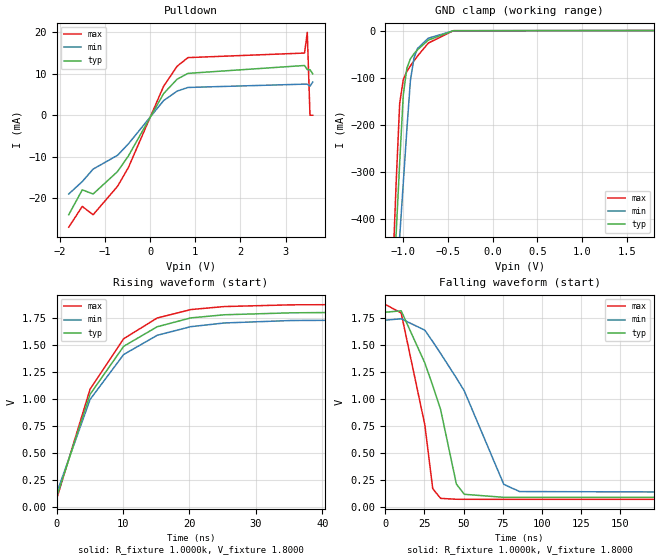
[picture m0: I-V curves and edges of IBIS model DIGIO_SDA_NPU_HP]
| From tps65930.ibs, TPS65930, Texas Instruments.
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|   Model DIGIO_SDA_NPU_HP
[Model]  DIGIO_SDA_NPU_HP
Model_type I/O_open_drain
Polarity   Non-Inverting
Enable   Active-Low
Vinl =   0.6300V
Vinh =   1.1700V
C_comp   1.3888pF   2.2766pF   1.3653pF
[Temperature Range]   25.0000   0.1250k   -40.0000
[Pullup Reference]   1.8000V   1.7280V   1.8720V
[Pulldown Reference]   0.0V   0.0V   0.0V
[POWER Clamp Reference]   1.8000V   1.7280V   1.8720V
[GND Clamp Reference]   0.0V   0.0V   0.0V
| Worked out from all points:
|   slope of the pulldown table from 0 to 0.27 V, typ, clamps not added: 56.7 ohm
|   GND clamp passes 1 mA (typ) near -0.48 V on its own axis
|   rising waveform, R_fixture 1.0000k, V_fixture 1.8000: 20-80 % time 7.98ns typ, 8.21ns min, 7.84ns max; typ from 0.089 V to 1.8 V
|   falling waveform, R_fixture 1.0000k, V_fixture 1.8000: 20-80 % time 20.7ns typ, 33.5ns min, 13.6ns max; typ from 1.8 V to 0.089 V
[Pulldown]
|Voltage   I(typ)   I(min)   I(max)
-1.8V     -24mA      -19mA      -27mA
-1.5V     -18mA      -16mA      -22mA
-1.26V    -19mA      -13mA      -24mA
-720mV    -13.59mA   -9.66mA    -17.16mA
-480mV    -9.841mA   -6.917mA   -12.63mA
300mV     5.219mA    3.531mA    6.988mA
600mV     8.705mA    5.824mA    11.83mA
840mV     10.1mA     6.7mA      13.9mA
3.42V     12mA       7.5mA      15mA
3.48V     11mA       7.5mA      20mA
3.54V     11mA       7mA        0A
3.6V      10mA       8mA        0A
[GND_clamp]
|Voltage   I(typ)   I(min)   I(max)
-1.8V     -3.217A    -2.637A    -3.872A
-1.12V    -586.2mA   -666.6mA   -520.9mA
-1.08V    -433.2mA   -552.2mA   -325.7mA
-1.04V    -280.6mA   -438.1mA   -154.5mA
-1V       -137.3mA   -324.2mA   -104.4mA
-960mV    -80.09mA   -210.6mA   -86.92mA
-920mV    -60.05mA   -105.9mA   -74.96mA
-880mV    -49.17mA   -57.98mA   -64.18mA
-840mV    -40.79mA   -38.01mA   -53.95mA
-720mV    -20.35mA   -16.3mA    -26.7mA
-440mV    -395.2uA   -580uA     -319uA
1.8V      20.09nA    79.65nA    15.47nA
[Ramp]
| variable   typ   min   max
dV/dt_r  1.0268/7.8959n   0.9617/8.1255n   1.0813/7.7656n
dV/dt_f  1.0268/20.4605n   0.9617/33.1830n   1.0813/13.5006n
R_load = 1.0000k
[Rising Waveform]
R_fixture= 1.0000k
V_fixture= 1.8000
V_fixture_min= 1.7280
V_fixture_max= 1.8720
|time   V(typ)   V(min)   V(max)
0s        88.62mV    124.1mV    69.75mV
5.051ns   1.041V     993.6mV    1.089V
10.1ns    1.485V     1.409V     1.555V
15.15ns   1.666V     1.587V     1.747V
20.2ns    1.748V     1.667V     1.825V
25.25ns   1.777V     1.701V     1.853V
35.35ns   1.795V     1.724V     1.869V
45.45ns   1.8V       1.727V     1.871V
500ns     1.8V       1.727V     1.872V
[Falling Waveform]
R_fixture= 1.0000k
V_fixture= 1.8000
V_fixture_min= 1.7280
V_fixture_max= 1.8720
|time   V(typ)   V(min)   V(max)
0s        1.8V       1.727V     1.872V
10.1ns    1.814V     1.74V      1.794V
25.25ns   1.331V     1.634V     758.1mV
30.3ns    1.122V     1.529V     168.4mV
35.35ns   899.7mV    1.419V     78.6mV
45.45ns   210.2mV    1.192V     70.51mV
50.51ns   116.2mV    1.072V     70.07mV
75.76ns   88.36mV    208.3mV    69.78mV
85.86ns   88.85mV    141.8mV    69.78mV
500ns     88.59mV    124.1mV    69.77mV
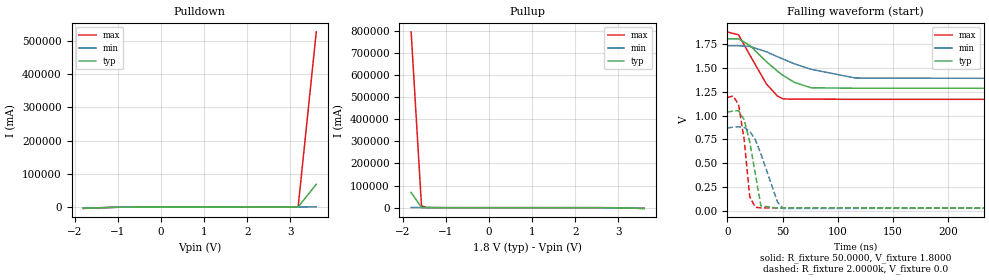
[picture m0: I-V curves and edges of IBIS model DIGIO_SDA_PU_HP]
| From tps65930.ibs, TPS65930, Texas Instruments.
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|   Model DIGIO_SDA_PU_HP
[Model]  DIGIO_SDA_PU_HP
Model_type Output
Polarity   Non-Inverting
Vinl =   0.6300V
Vinh =   1.1700V
C_comp   1.3888pF   2.2766pF   1.3653pF
[Temperature Range]   25.0000   0.1250k   -40.0000
[Pullup Reference]   1.8000V   1.7280V   1.8720V
[Pulldown Reference]   0.0V   0.0V   0.0V
[POWER Clamp Reference]   1.8000V   1.7280V   1.8720V
[GND Clamp Reference]   0.0V   0.0V   0.0V
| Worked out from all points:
|   slope of the pulldown table from 0 to 0.27 V, typ, clamps not added: 56.6 ohm
|   slope of the pullup table from 0 to 0.27 V, typ, clamps not added: 1.35 kohm
|   falling waveform, R_fixture 50.0000, V_fixture 1.8000: 20-80 % time 30.5ns typ, 48.1ns min, 20.8ns max; typ from 1.8 V to 1.28 V
|   falling waveform, R_fixture 2.0000k, V_fixture 0.0: 20-80 % time 9.79ns typ, 14.9ns min, 6.97ns max; typ from 1.03 V to 0.034 V
[Pulldown]
|Voltage   I(typ)   I(min)   I(max)
-1.8V     -3.242A    -2.657A    -3.9A
-1.08V    -451.5mA   -564.9mA   -348.9mA
-1.02V    -222.2mA   -393.4mA   -143.4mA
-960mV    -97.11mA   -222.5mA   -108.3mA
-900mV    -70.41mA   -87.93mA   -89.97mA
-600mV    -19.06mA   -14.77mA   -23.76mA
2.82V     20.66mA    12.68mA    22.74mA
2.94V     105.5mA    50.35mA    124.5mA
3.06V     288.1mA    171.1mA    333.6mA
3.12V     395.6mA    256mA      451.7mA
3.18V     508.5mA    350.3mA    574.2mA
3.6V      68.75A     1.194A     526A
[Pullup]
|Voltage   I(typ)   I(min)   I(max)
-1.8V     68.74A     978.5mA    794.4A
-1.56V    859.4mA    526.7mA    8.216A
-1.44V    613.7mA    323.4mA    854.8mA
-1.32V    384.4mA    148.2mA    583.6mA
-1.14V    94.32mA    12.8mA     228.5mA
-900mV    1.005mA    657.8uA    2.043mA
2.46V     -13.11mA   -18.23mA   -7.345mA
2.64V     -41.51mA   -92.9mA    -37.84mA
2.82V     -205.2mA   -587.1mA   -84.05mA
2.88V     -434mA     -758.8mA   -110.9mA
3V        -893.7mA   -1.103A    -561mA
3.6V      -3.218A    -2.849A    -3.516A
[Ramp]
| variable   typ   min   max
dV/dt_r  0.3744/7.4199n   0.2800/7.7792n   0.4731/6.8095n
dV/dt_f  1.0051/20.5753n   0.9382/33.9197n   1.0598/13.5810n
R_load = 1.0000k
[Falling Waveform]
R_fixture= 50.0000
V_fixture= 1.8000
V_fixture_min= 1.7280
V_fixture_max= 1.8720
|time   V(typ)   V(min)   V(max)
0s        1.8V       1.728V     1.872V
10.1ns    1.8V       1.728V     1.842V
20.2ns    1.733V     1.721V     1.633V
35.35ns   1.561V     1.665V     1.328V
45.45ns   1.461V     1.613V     1.201V
50.51ns   1.417V     1.588V     1.173V
60.61ns   1.346V     1.54V      1.171V
75.76ns   1.289V     1.482V     1.171V
116ns     1.285V     1.391V     1.169V
500ns     1.283V     1.382V     1.169V
[Falling Waveform]
R_fixture= 2.0000k
V_fixture= 0.0
V_fixture_min= 0.0
V_fixture_max= 0.0
|time   V(typ)   V(min)   V(max)
0s        1.034V     869.1mV    1.187V
5.051ns   1.048V     878.6mV    1.204V
10.1ns    1.05V      882.8mV    1.114V
15.15ns   956.8mV    876.1mV    749.8mV
20.2ns    726.7mV    835.4mV    153.1mV
25.25ns   392.6mV    748.1mV    42.46mV
30.3ns    57.51mV    599mV      35.75mV
45.45ns   33.68mV    94.1mV     35.86mV
50.51ns   36.51mV    29.85mV    34.25mV
500ns     34.49mV    37.28mV    34.61mV
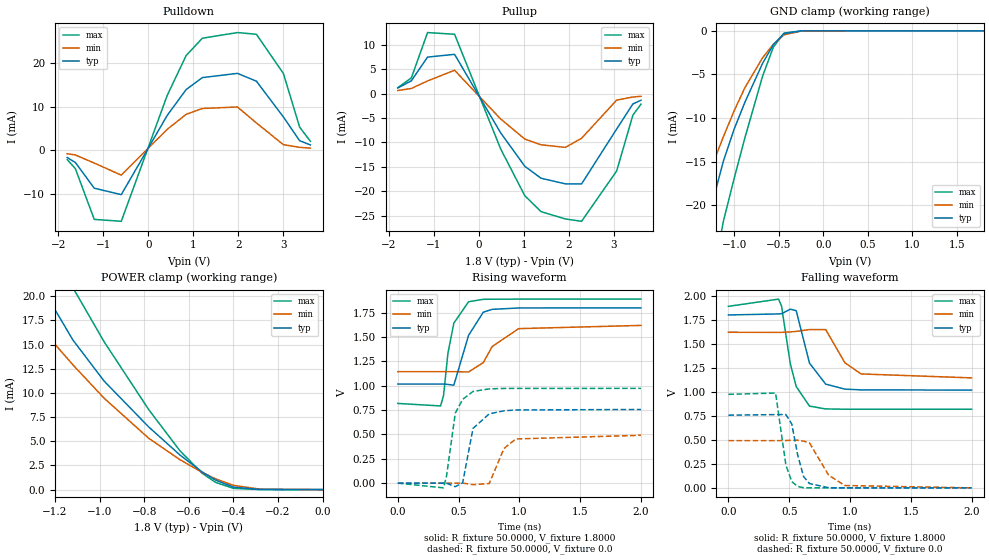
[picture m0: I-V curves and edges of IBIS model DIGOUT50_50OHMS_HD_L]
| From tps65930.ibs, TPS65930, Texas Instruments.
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|   Model DIGOUT50_50OHMS_HD_L
[Model]   DIGOUT50_50OHMS_HD_L
Model_type   3-state
Polarity   Non-Inverting
Enable   Active-Low
Vmeas =   0.9000V
Cref =   30.0000fF
Rref =   100.0000M
Vref =   0.0V
C_comp   0.9042pF   0.8577pF   0.9422pF
[Temperature Range]   25.0000   0.1250k   -40.0000
[Pullup Reference]   1.8000V   1.6200V   1.8900V
[Pulldown Reference]   0.0V   0.0V   0.0V
[POWER Clamp Reference]   1.8000V   1.6200V   1.8900V
[GND Clamp Reference]   0.0V   0.0V   0.0V
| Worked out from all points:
|   slope of the pulldown table from 0 to 0.27 V, typ, clamps not added: 50.5 ohm
|   slope of the pullup table from 0 to 0.27 V, typ, clamps not added: 57.9 ohm
|   GND clamp passes 1 mA (typ) near -0.52 V on its own axis
|   POWER clamp passes 1 mA (typ) near -0.48 V on its own axis
|   rising waveform, R_fixture 50.0000, V_fixture 1.8000: 20-80 % time 103ps typ, 191ps min, 81.3ps max; typ from 1.02 V to 1.8 V
|   rising waveform, R_fixture 50.0000, V_fixture 0.0: 20-80 % time 77.2ps typ, 101ps min, 80.4ps max; typ from 0 V to 0.757 V
|   falling waveform, R_fixture 50.0000, V_fixture 1.8000: 20-80 % time 114ps typ, 146ps min, 101ps max; typ from 1.8 V to 1.02 V
|   falling waveform, R_fixture 50.0000, V_fixture 0.0: 20-80 % time 79ps typ, 131ps min, 64.1ps max; typ from 0.757 V to 0 V
[Pulldown]
|Voltage   I(typ)   I(min)   I(max)
-1.8V     -1.678mA   -799.1uA   -2.152mA
-1.62V    -2.808mA   -1.084mA   -4.212mA
-1.2V     -8.722mA   -2.942mA   -15.89mA
-600mV    -10.2mA    -5.722mA   -16.33mA
420mV     8.006mA    4.812mA    12.6mA
840mV     13.94mA    8.244mA    21.76mA
1.2V      16.7mA     9.604mA    25.75mA
1.98V     17.67mA    9.943mA    27.05mA
2.4V      15.88mA    6.281mA    26.66mA
3V        7.647mA    1.287mA    17.65mA
3.36V     2.201mA    669.4uA    5.339mA
3.6V      1.22mA     501uA      2.046mA
[Pullup]
|Voltage   I(typ)   I(min)   I(max)
-1.8V     1.134mA    623.8uA    1.206mA
-1.5V     2.605mA    1.039mA    3.194mA
-1.14V    7.463mA    2.573mA    12.49mA
-540mV    8.033mA    4.77mA     12.14mA
480mV     -8.001mA   -5.177mA   -11.28mA
1.02V     -14.9mA    -9.331mA   -20.93mA
1.38V     -17.35mA   -10.5mA    -24.19mA
1.92V     -18.5mA    -11.03mA   -25.69mA
2.28V     -18.52mA   -9.169mA   -26.17mA
3.06V     -7.259mA   -1.342mA   -15.86mA
3.42V     -2.128mA   -710uA     -4.414mA
3.6V      -1.368mA   -569.8uA   -2.173mA
[GND_clamp]
|Voltage   I(typ)   I(min)   I(max)
-1.8V     -44.84mA   -30.91mA   -71.88mA
-1.48V    -29.89mA   -21.84mA   -45.51mA
-1.32V    -22.78mA   -17.43mA   -33.28mA
-1.28V    -21.09mA   -16.34mA   -30.5mA
-1.12V    -14.94mA   -12.14mA   -21.83mA
-1V       -11.29mA   -9.191mA   -16.95mA
-880mV    -8.217mA   -6.543mA   -12.31mA
-680mV    -3.723mA   -3.082mA   -5.189mA
-560mV    -1.583mA   -1.542mA   -1.867mA
-440mV    -312.2uA   -459.9uA   -257.5uA
-240mV    -649.1nA   -5.533uA   -133.4nA
1.8V      96.68pA    1.983uA    56.09pA
[POWER_clamp]
|Voltage   I(typ)   I(min)   I(max)
-1.8V     45.7mA     31.78mA    72.79mA
-1.42V    27.95mA    21mA       41.38mA
-1.26V    20.94mA    16.61mA    29.22mA
-1.12V    15.48mA    12.91mA    20.89mA
-980mV    11.23mA    9.456mA    15.3mA
-780mV    6.486mA    5.314mA    8.281mA
-640mV    3.584mA    3.099mA    4.022mA
-540mV    1.825mA    1.782mA    1.689mA
-480mV    980.7uA    1.113mA    750.8uA
-400mV    258.7uA    440.4uA    131uA
-280mV    9.388uA    45.01uA    1.622uA
0V        528.2pA    2.408nA    1.834nA
[Ramp]
| variable   typ   min   max
dV/dt_r   0.4540/88.5825p   0.2944/99.3483p   0.5841/79.6594p
dV/dt_f   0.4692/0.1205n   0.2840/0.1433n   0.6429/99.7342p
R_load =   50.0000
[Rising Waveform]
R_fixture=   50.0000
V_fixture=   1.8000
V_fixture_min=  1.6200
V_fixture_max=  1.8900
|time   V(typ)   V(min)   V(max)
0s        1.018V     1.145V     818.5mV
351.5ps   1.018V     1.145V     793.1mV
375.8ps   1.018V     1.145V     898.3mV
412.1ps   1.014V     1.145V     1.334V
460.6ps   1.006V     1.145V     1.643V
581.8ps   1.518V     1.142V     1.863V
703ps     1.756V     1.238V     1.888V
775.8ps   1.785V     1.403V     1.889V
993.9ps   1.799V     1.587V     1.89V
2ns       1.8V       1.62V      1.89V
[Rising Waveform]
R_fixture=   50.0000
V_fixture=   0.0
V_fixture_min=  0.0
V_fixture_max=  0.0
|time   V(typ)   V(min)   V(max)
0s        25.11nV    451.7nV    37.2nV
375.8ps   532.3uV    -26.23uV   -48.38mV
400ps     -759.5uV   -19.93uV   68.31mV
472.7ps   -36.47mV   39.97uV    719.7mV
533.3ps   3.654mV    389.4uV    860.6mV
618.2ps   561.9mV    -15.63mV   941.7mV
751.5ps   711.2mV    -4.566mV   968.2mV
872.7ps   743.1mV    355.2mV    972.4mV
969.7ps   751.5mV    453.7mV    973.2mV
2ns       756.7mV    491.7mV    973.5mV
[Falling Waveform]
R_fixture=   50.0000
V_fixture=   1.8000
V_fixture_min=  1.6200
V_fixture_max=  1.8900
|time   V(typ)   V(min)   V(max)
0s        1.8V       1.62V      1.89V
412.1ps   1.811V     1.619V     1.965V
436.4ps   1.813V     1.619V     1.895V
509.1ps   1.86V      1.624V     1.292V
557.6ps   1.845V     1.629V     1.055V
666.7ps   1.299V     1.648V     851.2mV
800ps     1.08V      1.648V     821.8mV
957.6ps   1.028V     1.303V     818.7mV
1.091ns   1.02V      1.186V     818.5mV
2ns       1.018V     1.145V     818.5mV
[Falling Waveform]
R_fixture=   50.0000
V_fixture=   0.0
V_fixture_min=  0.0
V_fixture_max=  0.0
|time   V(typ)   V(min)   V(max)
0s        756.7mV    491.7mV    973.5mV
387.9ps   762.6mV    491.4mV    987.2mV
472.7ps   763.3mV    492.8mV    236.8mV
521.2ps   664.3mV    496.1mV    65.09mV
569.7ps   342.7mV    495.5mV    14.7mV
618.2ps   117.9mV    486.6mV    1.581mV
666.7ps   44.71mV    468.2mV    151.1uV
824.2ps   1.447mV    131.7mV    -3.651uV
957.6ps   76.7uV     24.51mV    46.05nV
2ns       23.18nV    282.7nV    37.29nV
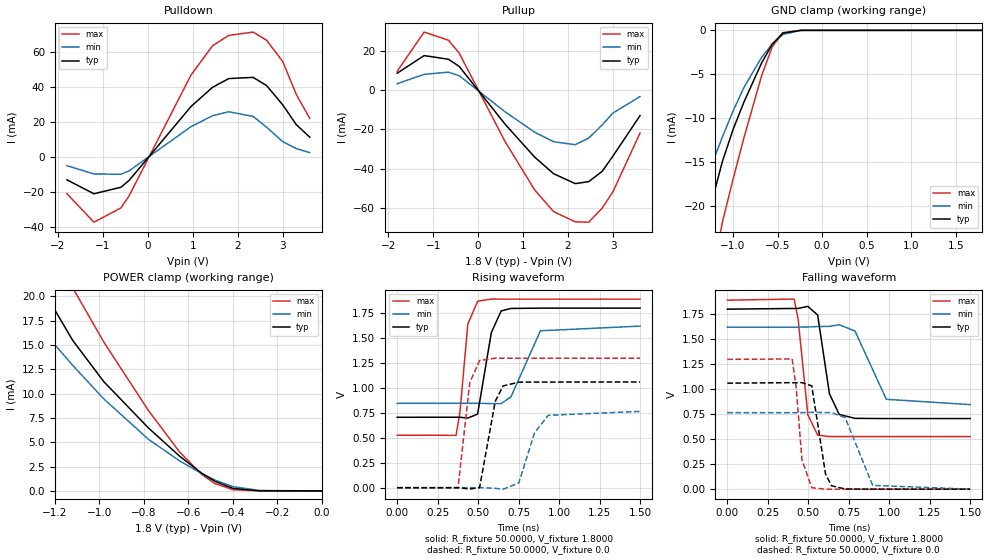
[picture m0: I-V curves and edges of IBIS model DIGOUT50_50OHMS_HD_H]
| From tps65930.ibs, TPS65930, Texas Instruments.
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|   Model DIGOUT50_50OHMS_HD_H
[Model]   DIGOUT50_50OHMS_HD_H
Model_type   3-state
Polarity   Non-Inverting
Enable   Active-Low
Vmeas =   0.9000V
Cref =   30.0000fF
Rref =   100.0000M
Vref =   0.0V
C_comp   0.2875pF   0.2678pF   0.3616pF
[Temperature Range]   25.0000   0.1250k   -40.0000
[Pullup Reference]   1.8000V   1.6200V   1.8900V
[Pulldown Reference]   0.0V   0.0V   0.0V
[POWER Clamp Reference]   1.8000V   1.6200V   1.8900V
[GND Clamp Reference]   0.0V   0.0V   0.0V
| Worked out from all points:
|   slope of the pulldown table from 0 to 0.27 V, typ, clamps not added: 31.1 ohm
|   slope of the pullup table from 0 to 0.27 V, typ, clamps not added: 34 ohm
|   GND clamp passes 1 mA (typ) near -0.52 V on its own axis
|   POWER clamp passes 1 mA (typ) near -0.48 V on its own axis
|   rising waveform, R_fixture 50.0000, V_fixture 1.8000: 20-80 % time 62.5ps typ, 94ps min, 44.6ps max; typ from 0.706 V to 1.8 V
|   rising waveform, R_fixture 50.0000, V_fixture 0.0: 20-80 % time 57.1ps typ, 88.1ps min, 45.6ps max; typ from 0 V to 1.06 V
|   falling waveform, R_fixture 50.0000, V_fixture 1.8000: 20-80 % time 56.5ps typ, 104ps min, 50ps max; typ from 1.8 V to 0.706 V
|   falling waveform, R_fixture 50.0000, V_fixture 0.0: 20-80 % time 53.9ps typ, 83.6ps min, 40.3ps max; typ from 1.06 V to 0 V
[Pulldown]
|Voltage   I(typ)   I(min)   I(max)
-1.8V     -13.13mA   -5.04mA    -21.03mA
-1.2V     -21.09mA   -9.761mA   -37.33mA
-600mV    -17.38mA   -9.966mA   -29.19mA
-420mV    -13.54mA   -8.035mA   -22.37mA
960mV     28.78mA    17.27mA    46.76mA
1.44V     39.77mA    23.5mA     63.52mA
1.8V      44.72mA    25.74mA    69.39mA
2.34V     45.4mA     23.1mA     71.27mA
2.64V     40.72mA    16.94mA    66.59mA
3V        29.65mA    8.647mA    54.4mA
3.3V      18.4mA     4.726mA    35.65mA
3.6V      11.22mA    2.42mA     21.93mA
[Pullup]
|Voltage   I(typ)   I(min)   I(max)
-1.8V     8.765mA    3.386mA    9.77mA
-1.2V     17.77mA    8.175mA    29.79mA
-660mV    15.9mA     9.298mA    25.65mA
-420mV    12.23mA    7.466mA    18.99mA
600mV     -17.3mA    -10.96mA   -26.2mA
1.26V     -34.19mA   -21.43mA   -50.98mA
1.68V     -42.63mA   -26.28mA   -62.04mA
2.16V     -47.69mA   -27.79mA   -67.22mA
2.46V     -46.68mA   -24.38mA   -67.41mA
2.76V     -41.39mA   -17.66mA   -60.2mA
3V        -33.55mA   -11.56mA   -51.75mA
3.6V      -12.93mA   -3.176mA   -21.85mA
[GND_clamp]
|Voltage   I(typ)   I(min)   I(max)
-1.8V     -44.84mA   -30.91mA   -71.88mA
-1.48V    -29.89mA   -21.84mA   -45.51mA
-1.32V    -22.78mA   -17.43mA   -33.28mA
-1.28V    -21.09mA   -16.34mA   -30.5mA
-1.12V    -14.94mA   -12.14mA   -21.83mA
-1V       -11.29mA   -9.191mA   -16.95mA
-880mV    -8.217mA   -6.543mA   -12.31mA
-680mV    -3.723mA   -3.082mA   -5.189mA
-560mV    -1.583mA   -1.542mA   -1.867mA
-440mV    -312.2uA   -459.9uA   -257.5uA
-240mV    -649.1nA   -5.533uA   -133.4nA
1.8V      96.68pA    1.983uA    56.09pA
[POWER_clamp]
|Voltage   I(typ)   I(min)   I(max)
-1.8V     45.7mA     31.78mA    72.79mA
-1.42V    27.95mA    21mA       41.38mA
-1.26V    20.94mA    16.61mA    29.22mA
-1.12V    15.48mA    12.91mA    20.89mA
-980mV    11.23mA    9.456mA    15.3mA
-780mV    6.486mA    5.314mA    8.281mA
-640mV    3.584mA    3.099mA    4.022mA
-540mV    1.825mA    1.782mA    1.689mA
-480mV    980.7uA    1.113mA    750.8uA
-400mV    258.7uA    440.4uA    131uA
-280mV    9.388uA    45.01uA    1.622uA
0V        528.2pA    2.408nA    1.834nA
[Ramp]
| variable   typ   min   max
dV/dt_r   0.6357/60.1719p   0.4588/87.5739p   0.7790/46.5678p
dV/dt_f   0.6564/67.9770p   0.4646/0.1029n   0.8185/49.8339p
R_load =   50.0000
[Rising Waveform]
R_fixture=   50.0000
V_fixture=   1.8000
V_fixture_min=  1.6200
V_fixture_max=  1.8900
|time   V(typ)   V(min)   V(max)
0s        706mV      845.6mV    525.9mV
363.6ps   706.2mV    845.6mV    525.1mV
387.9ps   706.1mV    845.6mV    756.7mV
436.4ps   698mV      845.6mV    1.64V
497ps     738.3mV    845.7mV    1.869V
581.8ps   1.555V     843.3mV    1.891V
642.4ps   1.772V     843mV      1.89V
703ps     1.797V     911.1mV    1.89V
884.8ps   1.8V       1.573V     1.89V
1.5ns     1.8V       1.62V      1.89V
[Rising Waveform]
R_fixture=   50.0000
V_fixture=   0.0
V_fixture_min=  0.0
V_fixture_max=  0.0
|time   V(typ)   V(min)   V(max)
0s        12.83nV    343.8nV    15.92nV
375.8ps   315.5uV    -9.993uV   -1.894mV
448.5ps   -12.77mV   10.77uV    1.053V
509.1ps   899.7uV    196.7uV    1.275V
606.1ps   866.6mV    -6.454mV   1.299V
654.5ps   1.02V      -14.7mV    1.298V
751.5ps   1.058V     48.32mV    1.298V
848.5ps   1.059V     551.4mV    1.298V
933.3ps   1.059V     725.8mV    1.298V
1.5ns     1.06V      764.7mV    1.298V
[Falling Waveform]
R_fixture=   50.0000
V_fixture=   1.8000
V_fixture_min=  1.6200
V_fixture_max=  1.8900
|time   V(typ)   V(min)   V(max)
0s        1.8V       1.62V      1.89V
412.1ps   1.807V     1.62V      1.901V
436.4ps   1.807V     1.62V      1.706V
497ps     1.828V     1.622V     743.7mV
557.6ps   1.741V     1.626V     540.4mV
630.3ps   954.3mV    1.628V     525.9mV
690.9ps   746.7mV    1.644V     525.9mV
787.9ps   708mV      1.582V     525.9mV
981.8ps   706mV      898.4mV    525.9mV
1.5ns     706mV      845.6mV    525.9mV
[Falling Waveform]
R_fixture=   50.0000
V_fixture=   0.0
V_fixture_min=  0.0
V_fixture_max=  0.0
|time   V(typ)   V(min)   V(max)
0s        1.06V      764.7mV    1.298V
400ps     1.065V     764.5mV    1.302V
424.2ps   1.064V     764.5mV    1.029V
460.6ps   1.065V     765.1mV    294.2mV
521.2ps   1.033V     768.3mV    14.09mV
606.1ps   152.8mV    765.9mV    -93.18uV
642.4ps   34.07mV    765.9mV    -62.4uV
727.3ps   1.505mV    715.9mV    -4.784uV
897ps     20.57uV    37.71mV    422nV
1.5ns     30.86nV    3.222uV    15.96nV
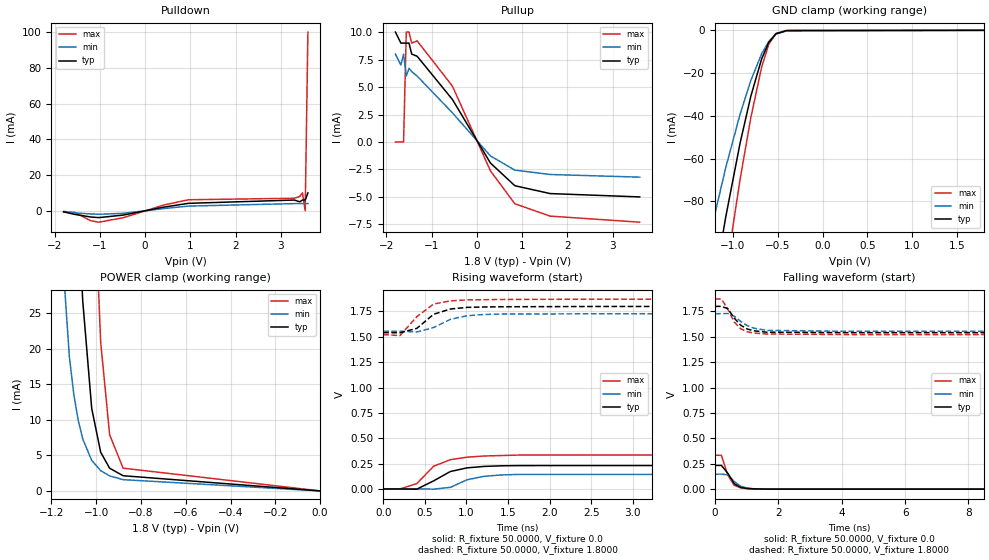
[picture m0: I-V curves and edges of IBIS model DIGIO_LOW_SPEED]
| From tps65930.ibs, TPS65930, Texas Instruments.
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|   Model DIGIO_LOW_SPEED
[Model]  DIGIO_LOW_SPEED
Model_type I/O
Polarity   Non-Inverting
Enable   Active-Low
Vinl =   0.6300V
Vinh =   1.1700V
C_comp   1.0177pF   1.9063pF   1.0043pF
[Temperature Range]   25.0000   0.1250k   -40.0000
[Pullup Reference]   1.8000V   1.7280V   1.8720V
[Pulldown Reference]   0.0V   0.0V   0.0V
[POWER Clamp Reference]   1.8000V   1.7280V   1.8720V
[GND Clamp Reference]   0.0V   0.0V   0.0V
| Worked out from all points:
|   slope of the pulldown table from 0 to 0.27 V, typ, clamps not added: 199 ohm
|   slope of the pullup table from 0 to 0.27 V, typ, clamps not added: 155 ohm
|   GND clamp passes 1 mA (typ) near -0.49 V on its own axis
|   POWER clamp passes 1 mA (typ) near -0.68 V on its own axis
|   rising waveform, R_fixture 50.0000, V_fixture 0.0: 20-80 % time 366ps typ, 328ps min, 322ps max; typ from 0 V to 0.234 V
|   rising waveform, R_fixture 50.0000, V_fixture 1.8000: 20-80 % time 290ps typ, 331ps min, 283ps max; typ from 1.54 V to 1.8 V
|   falling waveform, R_fixture 50.0000, V_fixture 0.0: 20-80 % time 320ps typ, 332ps min, 278ps max; typ from 0.234 V to 0 V
|   falling waveform, R_fixture 50.0000, V_fixture 1.8000: 20-80 % time 462ps typ, 545ps min, 426ps max; typ from 1.8 V to 1.54 V
[Pulldown]
|Voltage   I(typ)   I(min)   I(max)
-1.8V     -600uA     -700uA     -400uA
-1.56V    -2mA       -1.2mA     -900uA
-1.2V     -3.5mA     -1.77mA    -5.6mA
-1.02V    -3.83mA    -1.97mA    -6.4mA
-480mV    -2.414mA   -1.442mA   -3.883mA
420mV     2.056mA    1.253mA    3.24mA
960mV     4.161mA    2.612mA    6.16mA
3.3V      6mA        4mA        7mA
3.42V     5mA        4mA        8mA
3.48V     6mA        4mA        10mA
3.54V     6mA        4mA        0A
3.6V      10mA       4mA        100mA
[Pullup]
|Voltage   I(typ)   I(min)   I(max)
-1.8V     10mA       8mA        0A
-1.68V    9mA        7mA        0A
-1.62V    9mA        8mA        0A
-1.56V    9mA        6mA        10mA
-1.5V     9mA        6.7mA      10mA
-1.44V    8mA        6.4mA      9mA
-1.32V    7.8mA      6mA        9.2mA
-540mV    3.866mA    2.651mA    5.08mA
300mV     -1.916mA   -1.27mA    -2.627mA
840mV     -3.982mA   -2.56mA    -5.624mA
1.62V     -4.696mA   -2.959mA   -6.747mA
3.6V      -5mA       -3.2mA     -7.3mA
[GND_clamp]
|Voltage   I(typ)   I(min)   I(max)
-1.8V     -286.5mA   -213.5mA   -357.5mA
-1.6V     -226.1mA   -167.3mA   -285.5mA
-1.4V     -169.1mA   -124.3mA   -216.2mA
-1.24V    -126.4mA   -92.74mA   -163.3mA
-1.08V    -87.19mA   -64.13mA   -113.7mA
-920mV    -52.68mA   -39.16mA   -69.65mA
-800mV    -30.76mA   -23.41mA   -40.77mA
-680mV    -13.43mA   -10.98mA   -17.24mA
-600mV    -5.635mA   -5.197mA   -6.575mA
-520mV    -1.587mA   -1.839mA   -1.5mA
-400mV    -106.6uA   -219.9uA   -61.31uA
1.8V      18.31nA    90.01nA    14.64nA
[POWER_clamp]
|Voltage   I(typ)   I(min)   I(max)
-1.8V     70.11A     2.031A     796.1A
-1.18V    166.1mA    52.5mA     317.3mA
-1.16V    132.1mA    37.48mA    274.5mA
-1.12V    77.4mA     18.98mA    197.8mA
-1.1V     56.34mA    13.61mA    163mA
-1.08V    39.48mA    9.886mA    130.5mA
-1.06V    26.72mA    7.311mA    100.6mA
-1.02V    11.62mA    4.305mA    51.57mA
-980mV    5.447mA    2.851mA    20.97mA
-940mV    3.199mA    2.117mA    7.911mA
-880mV    2.141mA    1.586mA    3.206mA
0V        18.31nA    51.45nA    21.51nA
[Ramp]
| variable   typ   min   max
dV/dt_r  0.1402/0.3624n   88.5000m/0.3245n   0.2009/0.3191n
dV/dt_f  0.1554/0.4574n   0.1044/0.5400n   0.2100/0.4222n
R_load = 50.0000
[Rising Waveform]
R_fixture= 50.0000
V_fixture= 0.0
V_fixture_min= 0.0
V_fixture_max= 0.0
|time   V(typ)   V(min)   V(max)
0s        0V         0V         0V
202ps     213.6uV    20.47uV    324.7uV
404ps     -1.909mV   210uV      52.96mV
606ps     79.79mV    -1.659mV   224.1mV
808ps     172.3mV    16.01mV    288.7mV
1.01ns    208.3mV    91.31mV    313.7mV
1.212ns   222.3mV    124.6mV    325mV
1.414ns   228.2mV    138mV      329.5mV
1.616ns   230.5mV    143.2mV    334mV
20ns      233.7mV    147.5mV    334.8mV
[Rising Waveform]
R_fixture= 50.0000
V_fixture= 1.8000
V_fixture_min= 1.7280
V_fixture_max= 1.8720
|time   V(typ)   V(min)   V(max)
0s        1.541V     1.554V     1.522V
202ps     1.54V      1.555V     1.512V
404ps     1.583V     1.547V     1.698V
606ps     1.722V     1.591V     1.823V
808ps     1.774V     1.672V     1.854V
1.01ns    1.79V      1.708V     1.864V
1.212ns   1.794V     1.72V      1.866V
1.414ns   1.796V     1.724V     1.868V
2.626ns   1.799V     1.727V     1.871V
20ns      1.8V       1.728V     1.872V
[Falling Waveform]
R_fixture= 50.0000
V_fixture= 0.0
V_fixture_min= 0.0
V_fixture_max= 0.0
|time   V(typ)   V(min)   V(max)
0s        233.7mV    147.5mV    334.8mV
202ps     234mV      148.3mV    332.9mV
404ps     156.2mV    140.3mV    137.4mV
606ps     53.54mV    75.2mV     38.02mV
808ps     17.3mV     28.79mV    12.39mV
1.01ns    6.816mV    11.31mV    4.352mV
1.212ns   2.966mV    4.04mV     1.904mV
1.616ns   844.9uV    1.014mV    425.8uV
2.02ns    334uV      500.1uV    107.1uV
20ns      0V         656.5nV    0V
[Falling Waveform]
R_fixture= 50.0000
V_fixture= 1.8000
V_fixture_min= 1.7280
V_fixture_max= 1.8720
|time   V(typ)   V(min)   V(max)
0s        1.8V       1.728V     1.872V
202ps     1.8V       1.728V     1.872V
404ps     1.777V     1.729V     1.773V
606ps     1.685V     1.703V     1.646V
808ps     1.615V     1.652V     1.58V
1.01ns    1.578V     1.612V     1.55V
1.212ns   1.56V      1.586V     1.538V
1.616ns   1.546V     1.564V     1.528V
4.242ns   1.541V     1.554V     1.522V
20ns      1.541V     1.554V     1.522V
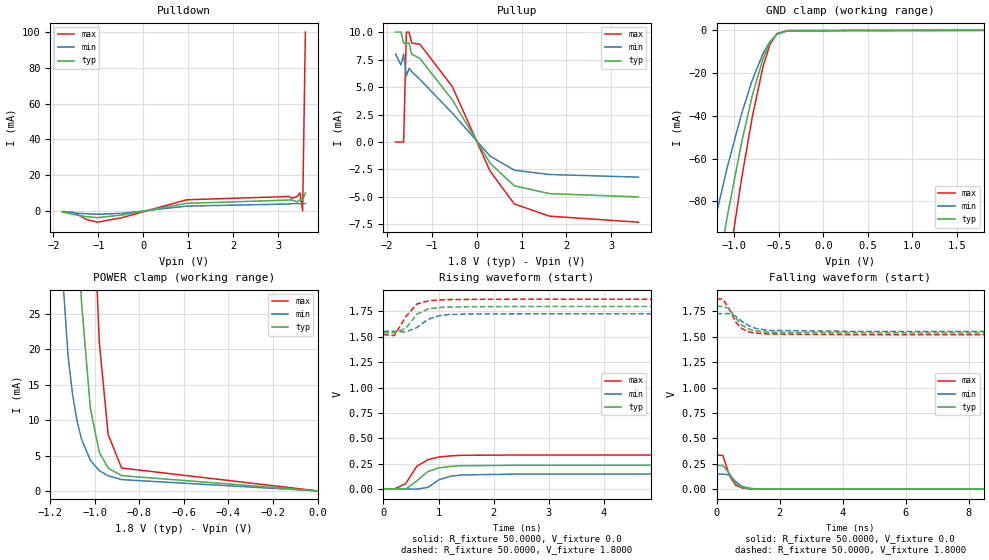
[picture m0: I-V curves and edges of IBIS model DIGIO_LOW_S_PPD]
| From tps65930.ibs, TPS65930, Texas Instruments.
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|   Model DIGIO_LOW_S_PPD
[Model]  DIGIO_LOW_S_PPD
Model_type I/O
Polarity   Non-Inverting
Enable   Active-Low
Vinl =   0.6300V
Vinh =   1.1700V
C_comp   1.0177pF   1.9063pF   1.0043pF
[Temperature Range]   25.0000   0.1250k   -40.0000
[Pullup Reference]   1.8000V   1.7280V   1.8720V
[Pulldown Reference]   0.0V   0.0V   0.0V
[POWER Clamp Reference]   1.8000V   1.7280V   1.8720V
[GND Clamp Reference]   0.0V   0.0V   0.0V
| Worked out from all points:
|   slope of the pulldown table from 0 to 0.27 V, typ, clamps not added: 200 ohm
|   slope of the pullup table from 0 to 0.27 V, typ, clamps not added: 155 ohm
|   GND clamp passes 1 mA (typ) near -0.49 V on its own axis
|   POWER clamp passes 1 mA (typ) near -0.67 V on its own axis
|   rising waveform, R_fixture 50.0000, V_fixture 0.0: 20-80 % time 367ps typ, 328ps min, 320ps max; typ from 0 V to 0.234 V
|   rising waveform, R_fixture 50.0000, V_fixture 1.8000: 20-80 % time 290ps typ, 331ps min, 283ps max; typ from 1.54 V to 1.8 V
|   falling waveform, R_fixture 50.0000, V_fixture 0.0: 20-80 % time 320ps typ, 327ps min, 278ps max; typ from 0.234 V to 0 V
|   falling waveform, R_fixture 50.0000, V_fixture 1.8000: 20-80 % time 462ps typ, 546ps min, 426ps max; typ from 1.8 V to 1.54 V
[Pulldown]
|Voltage   I(typ)   I(min)   I(max)
-1.8V     -600uA     -800uA     -400uA
-1.56V    -2mA       -1.2mA     -900uA
-1.26V    -3.3mA     -1.68mA    -4.9mA
-1.02V    -3.82mA    -1.97mA    -6.39mA
-480mV    -2.411mA   -1.439mA   -3.878mA
960mV     4.152mA    2.604mA    6.148mA
3.24V     6mA        3.8mA      8mA
3.3V      6mA        4mA        7mA
3.42V     5mA        4mA        8mA
3.48V     6mA        4mA        10mA
3.54V     6mA        4mA        0A
3.6V      10mA       4mA        100mA
[Pullup]
|Voltage   I(typ)   I(min)   I(max)
-1.8V     10mA       8mA        0A
-1.68V    10mA       7mA        0A
-1.62V    9mA        8mA        0A
-1.56V    9mA        6mA        10mA
-1.5V     9mA        6.7mA      10mA
-1.44V    8mA        6.4mA      9mA
-1.26V    7.6mA      5.7mA      8.9mA
-540mV    3.843mA    2.633mA    5.051mA
300mV     -1.93mA    -1.281mA   -2.647mA
840mV     -3.991mA   -2.567mA   -5.637mA
1.62V     -4.698mA   -2.96mA    -6.75mA
3.6V      -5mA       -3.2mA     -7.3mA
[GND_clamp]
|Voltage   I(typ)   I(min)   I(max)
-1.8V     -286.5mA   -213.5mA   -357.5mA
-1.6V     -226.1mA   -167.3mA   -285.5mA
-1.4V     -169.1mA   -124.3mA   -216.2mA
-1.24V    -126.4mA   -92.75mA   -163.3mA
-1.08V    -87.2mA    -64.14mA   -113.8mA
-920mV    -52.69mA   -39.16mA   -69.66mA
-800mV    -30.77mA   -23.42mA   -40.78mA
-680mV    -13.44mA   -10.99mA   -17.25mA
-600mV    -5.641mA   -5.201mA   -6.582mA
-520mV    -1.592mA   -1.843mA   -1.506mA
-400mV    -110.4uA   -223.1uA   -66.3uA
1.8V      17.11uA    14.47uA    22.48uA
[POWER_clamp]
|Voltage   I(typ)   I(min)   I(max)
-1.8V     70.11A     2.031A     796.1A
-1.18V    166.2mA    52.53mA    317.4mA
-1.16V    132.1mA    37.51mA    274.5mA
-1.12V    77.44mA    19.01mA    197.9mA
-1.1V     56.37mA    13.64mA    163mA
-1.08V    39.51mA    9.914mA    130.5mA
-1.06V    26.75mA    7.339mA    100.7mA
-1.02V    11.65mA    4.332mA    51.61mA
-980mV    5.479mA    2.877mA    21.01mA
-940mV    3.23mA     2.143mA    7.953mA
-880mV    2.172mA    1.611mA    3.246mA
0V        17.11uA    13.85uA    23.39uA
[Ramp]
| variable   typ   min   max
dV/dt_r  0.1402/0.3631n   88.5000m/0.3250n   0.2009/0.3173n
dV/dt_f  0.1554/0.4574n   0.1044/0.5408n   0.2100/0.4222n
R_load = 50.0000
[Rising Waveform]
R_fixture= 50.0000
V_fixture= 0.0
V_fixture_min= 0.0
V_fixture_max= 0.0
|time   V(typ)   V(min)   V(max)
0s        0V         0V         0V
202ps     213.6uV    20.5uV     308.6uV
404ps     -1.909mV   210uV      52.66mV
606ps     80.02mV    -1.658mV   223.9mV
808ps     172.3mV    16.01mV    289.5mV
1.01ns    208.1mV    91.28mV    315.3mV
1.212ns   222.1mV    124.5mV    325.9mV
1.414ns   228.9mV    137.9mV    331.7mV
2.424ns   233.5mV    147mV      334.7mV
20ns      233.7mV    147.5mV    334.8mV
[Rising Waveform]
R_fixture= 50.0000
V_fixture= 1.8000
V_fixture_min= 1.7280
V_fixture_max= 1.8720
|time   V(typ)   V(min)   V(max)
0s        1.541V     1.554V     1.522V
202ps     1.54V      1.555V     1.512V
404ps     1.583V     1.547V     1.697V
606ps     1.722V     1.591V     1.823V
808ps     1.774V     1.672V     1.854V
1.01ns    1.789V     1.708V     1.863V
1.212ns   1.794V     1.72V      1.867V
1.616ns   1.797V     1.725V     1.869V
2.626ns   1.799V     1.727V     1.871V
20ns      1.8V       1.728V     1.872V
[Falling Waveform]
R_fixture= 50.0000
V_fixture= 0.0
V_fixture_min= 0.0
V_fixture_max= 0.0
|time   V(typ)   V(min)   V(max)
0s        233.7mV    147.5mV    334.8mV
202ps     234mV      148.3mV    332.9mV
404ps     156.2mV    140.3mV    136.9mV
606ps     53.59mV    75.21mV    37.98mV
808ps     17.36mV    27.75mV    12.54mV
1.01ns    6.851mV    10.46mV    4.54mV
1.212ns   2.987mV    3.882mV    1.931mV
1.414ns   1.435mV    1.799mV    890.8uV
2.222ns   173.4uV    384.9uV    45.82uV
20ns      0V         689nV      0V
[Falling Waveform]
R_fixture= 50.0000
V_fixture= 1.8000
V_fixture_min= 1.7280
V_fixture_max= 1.8720
|time   V(typ)   V(min)   V(max)
0s        1.8V       1.728V     1.872V
202ps     1.8V       1.728V     1.872V
404ps     1.777V     1.729V     1.773V
606ps     1.685V     1.703V     1.646V
808ps     1.615V     1.652V     1.58V
1.01ns    1.578V     1.613V     1.55V
1.212ns   1.56V      1.586V     1.538V
1.616ns   1.546V     1.564V     1.528V
4.242ns   1.541V     1.554V     1.522V
20ns      1.541V     1.554V     1.522V
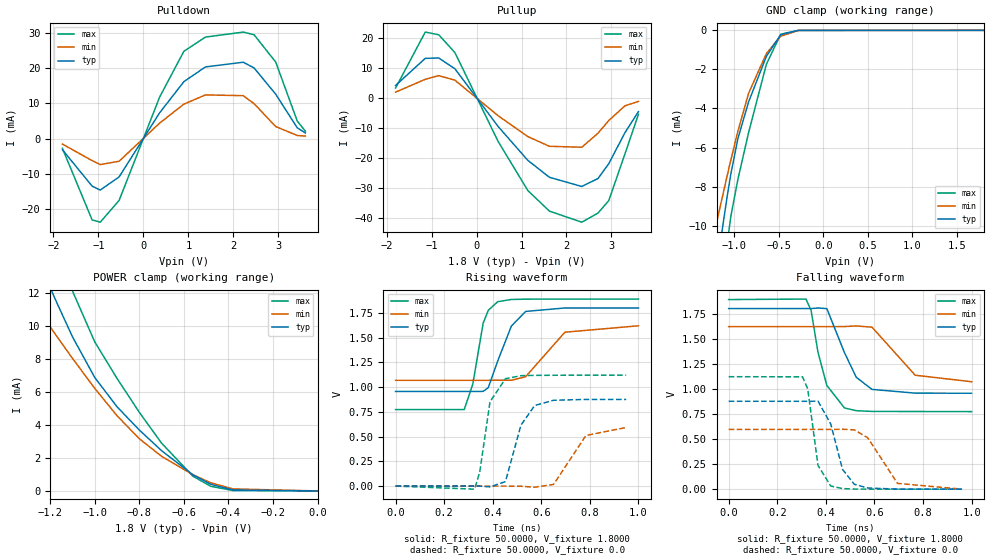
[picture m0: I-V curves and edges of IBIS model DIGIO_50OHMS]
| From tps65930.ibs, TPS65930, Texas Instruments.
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|   Model DIGIO_50OHMS
[Model]   DIGIO_50OHMS
Model_type   I/O
Polarity   Non-Inverting
Enable   Active-Low
Vinl =   0.6900V
Vinh =   1.0500V
Vmeas =   0.9000V
Cref =   30.0000pF
Rref =   100.0000M
Vref =   0.0V
C_comp   1.3575pF   1.3538pF   1.3884pF
[Temperature Range]   25.0000   0.1250k   -40.0000
[Pullup Reference]   1.8000V   1.6200V   1.8900V
[Pulldown Reference]   0.0V   0.0V   0.0V
[POWER Clamp Reference]   1.8000V   1.6200V   1.8900V
[GND Clamp Reference]   0.0V   0.0V   0.0V
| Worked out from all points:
|   slope of the pulldown table from 0 to 0.27 V, typ, clamps not added: 48.4 ohm
|   slope of the pullup table from 0 to 0.27 V, typ, clamps not added: 49.1 ohm
|   GND clamp passes 1 mA (typ) near -0.60 V on its own axis
|   POWER clamp passes 1 mA (typ) near -0.56 V on its own axis
|   rising waveform, R_fixture 50.0000, V_fixture 1.8000: 20-80 % time 78.9ps typ, 107ps min, 48.7ps max; typ from 0.956 V to 1.8 V
|   rising waveform, R_fixture 50.0000, V_fixture 0.0: 20-80 % time 63.5ps typ, 85.8ps min, 45.1ps max; typ from 0 V to 0.876 V
|   falling waveform, R_fixture 50.0000, V_fixture 1.8000: 20-80 % time 81.2ps typ, 102ps min, 62ps max; typ from 1.8 V to 0.956 V
|   falling waveform, R_fixture 50.0000, V_fixture 0.0: 20-80 % time 57.6ps typ, 81.1ps min, 38.3ps max; typ from 0.876 V to 0 V
[Pulldown]
|Voltage   I(typ)   I(min)   I(max)
-1.8V     -3.119mA   -1.519mA   -2.74mA
-1.14V    -13.4mA    -6.188mA   -22.95mA
-960mV    -14.52mA   -7.303mA   -23.6mA
-540mV    -10.8mA    -6.372mA   -17.45mA
360mV     7.32mA     4.409mA    11.75mA
900mV     16.14mA    9.778mA    24.72mA
1.38V     20.3mA     12.39mA    28.74mA
2.22V     21.63mA    12.17mA    30.15mA
2.46V     20.01mA    9.92mA     29.39mA
2.94V     12.61mA    3.44mA     21.71mA
3.42V     3.086mA    915.9uA    4.992mA
3.6V      1.642mA    754uA      2.136mA
[Pullup]
|Voltage   I(typ)   I(min)   I(max)
-1.8V     4.049mA    1.82mA     3.179mA
-1.14V    13.06mA    6.095mA    21.8mA
-840mV    13.19mA    7.322mA    20.91mA
-480mV    9.59mA     5.802mA    14.97mA
480mV     -9.593mA   -6.013mA   -14.56mA
1.14V     -20.85mA   -12.95mA   -30.88mA
1.62V     -26.49mA   -16.18mA   -37.74mA
2.34V     -29.54mA   -16.49mA   -41.42mA
2.7V      -26.9mA    -11.83mA   -38.39mA
2.94V     -21.95mA   -7.614mA   -34.24mA
3.3V      -11.63mA   -2.716mA   -18.68mA
3.6V      -4.632mA   -1.246mA   -5.526mA
[GND_clamp]
|Voltage   I(typ)   I(min)   I(max)
-1.8V     -34.14mA   -22.91mA   -56.09mA
-1.28V    -15.01mA   -11.55mA   -21.76mA
-1.24V    -13.63mA   -10.7mA    -19.32mA
-1.16V    -10.95mA   -9.044mA   -14.72mA
-1.08V    -8.484mA   -7.432mA   -10.91mA
-1.04V    -7.373mA   -6.652mA   -9.543mA
-960mV    -5.54mA    -5.162mA   -7.625mA
-840mV    -3.663mA   -3.222mA   -5.234mA
-640mV    -1.326mA   -1.186mA   -1.731mA
-480mV    -225.5uA   -300.7uA   -200uA
-280mV    -952.2nA   -5.334uA   -286.3nA
1.8V      185.2pA    1.257uA    274.5pA
[POWER_clamp]
|Voltage   I(typ)   I(min)   I(max)
-1.8V     32.87mA    22.14mA    54.5mA
-1.3V     15.56mA    11.92mA    22.77mA
-1.18V    11.71mA    9.568mA    15.92mA
-1.1V     9.352mA    8.045mA    12.13mA
-1V       6.882mA    6.226mA    9.046mA
-900mV    5.107mA    4.564mA    6.828mA
-800mV    3.698mA    3.167mA    4.771mA
-700mV    2.442mA    2.101mA    2.899mA
-560mV    987.6uA    987.5uA    899uA
-480mV    406uA      499.3uA    282.8uA
-380mV    56.76uA    122uA      23.73uA
0V        185.2pA    2.004nA    603.4pA
[Ramp]
| variable   typ   min   max
dV/dt_r   0.5257/62.9955p   0.3565/85.9286p   0.6727/50.1497p
dV/dt_f   0.5063/80.1647p   0.3296/0.1014n   0.6702/67.8789p
R_load =   50.0000
[Rising Waveform]
R_fixture=   50.0000
V_fixture=   1.8000
V_fixture_min=  1.6200
V_fixture_max=  1.8900
|time   V(typ)   V(min)   V(max)
0s        956.2mV    1.069V     773mV
282.8ps   956.2mV    1.069V     773.8mV
318.2ps   956.5mV    1.069V     1.033V
360.6ps   957.1mV    1.069V     1.646V
381.8ps   995mV      1.069V     1.776V
420.2ps   1.262V     1.07V      1.863V
476.8ps   1.617V     1.07V      1.886V
535.4ps   1.765V     1.105V     1.889V
697ps     1.8V       1.555V     1.89V
1ns       1.8V       1.62V      1.89V
[Rising Waveform]
R_fixture=   50.0000
V_fixture=   0.0
V_fixture_min=  0.0
V_fixture_max=  0.0
|time   V(typ)   V(min)   V(max)
0s        5.813nV    170.2nV    6.946nV
325.3ps   -30.67uV   1.094uV    -31.01mV
346.5ps   115uV      1.212uV    141mV
388.9ps   -7.993mV   -16.93uV   853mV
452.5ps   45.85mV    -28.16uV   1.085V
516.2ps   616mV      -1.672mV   1.116V
572.7ps   814.3mV    -11.17mV   1.119V
650.5ps   867.5mV    17.01mV    1.12V
783.8ps   875.8mV    511.7mV    1.121V
949.5ps   876.1mV    592.4mV    1.121V
[Falling Waveform]
R_fixture=   50.0000
V_fixture=   1.8000
V_fixture_min=  1.6200
V_fixture_max=  1.8900
|time   V(typ)   V(min)   V(max)
0s        1.8V       1.62V      1.89V
318.2ps   1.8V       1.62V      1.895V
339.4ps   1.8V       1.62V      1.781V
367.7ps   1.806V     1.62V      1.364V
404ps     1.8V       1.62V      1.034V
476.8ps   1.36V      1.621V     809.3mV
525.3ps   1.115V     1.627V     782.5mV
589.9ps   994.7mV    1.615V     774.8mV
767.7ps   957.2mV    1.136V     774.1mV
1ns       956.2mV    1.071V     773mV
[Falling Waveform]
R_fixture=   50.0000
V_fixture=   0.0
V_fixture_min=  0.0
V_fixture_max=  0.0
|time   V(typ)   V(min)   V(max)
0s        876.1mV    595.5mV    1.121V
304ps     875.9mV    595.5mV    1.12V
325.3ps   876.1mV    595.5mV    1.001V
367.7ps   877.4mV    595.5mV    237mV
420.2ps   649.9mV    595.5mV    31.35mV
468.7ps   196.9mV    597.3mV    5.872mV
517.2ps   48.71mV    591.1mV    1.118mV
572.7ps   11.54mV    511.7mV    176uV
694.9ps   518.7uV    57.63mV    9.653uV
959.6ps   7.306uV    228.4uV    3.221uV
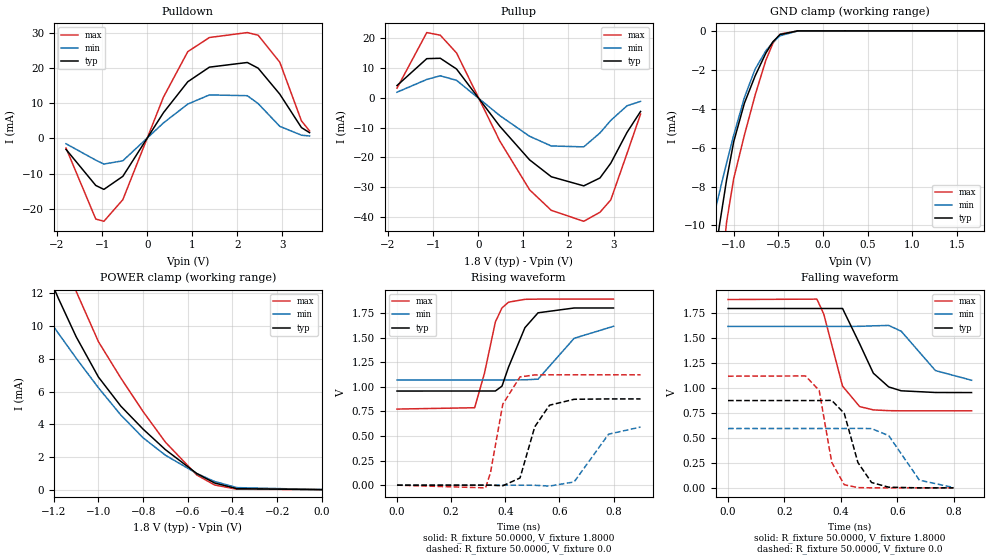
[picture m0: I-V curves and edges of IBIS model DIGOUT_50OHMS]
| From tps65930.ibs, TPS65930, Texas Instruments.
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|   Model DIGOUT_50OHMS
[Model]   DIGOUT_50OHMS
Model_type   3-state
Polarity   Non-Inverting
Enable   Active-Low
Vmeas =   0.9000V
Cref =   30.0000pF
Rref =   100.0000M
Vref =   0.0V
C_comp   1.2965pF   1.2891pF   1.3288pF
[Temperature Range]   25.0000   0.1250k   -40.0000
[Pullup Reference]   1.8000V   1.6200V   1.8900V
[Pulldown Reference]   0.0V   0.0V   0.0V
[POWER Clamp Reference]   1.8000V   1.6200V   1.8900V
[GND Clamp Reference]   0.0V   0.0V   0.0V
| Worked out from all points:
|   slope of the pulldown table from 0 to 0.27 V, typ, clamps not added: 48.4 ohm
|   slope of the pullup table from 0 to 0.27 V, typ, clamps not added: 49.1 ohm
|   GND clamp passes 1 mA (typ) near -0.62 V on its own axis
|   POWER clamp passes 1 mA (typ) near -0.56 V on its own axis
|   rising waveform, R_fixture 50.0000, V_fixture 1.8000: 20-80 % time 75.7ps typ, 101ps min, 54.2ps max; typ from 0.956 V to 1.8 V
|   rising waveform, R_fixture 50.0000, V_fixture 0.0: 20-80 % time 61.1ps typ, 83.8ps min, 48.5ps max; typ from 0 V to 0.876 V
|   falling waveform, R_fixture 50.0000, V_fixture 1.8000: 20-80 % time 78.4ps typ, 96.8ps min, 64ps max; typ from 1.8 V to 0.956 V
|   falling waveform, R_fixture 50.0000, V_fixture 0.0: 20-80 % time 55.5ps typ, 76.3ps min, 43.1ps max; typ from 0.876 V to 0 V
[Pulldown]
|Voltage   I(typ)   I(min)   I(max)
-1.8V     -3.117mA   -1.519mA   -2.738mA
-1.14V    -13.4mA    -6.188mA   -22.96mA
-960mV    -14.52mA   -7.304mA   -23.61mA
-540mV    -10.8mA    -6.372mA   -17.45mA
360mV     7.32mA     4.409mA    11.75mA
900mV     16.14mA    9.778mA    24.72mA
1.38V     20.3mA     12.39mA    28.74mA
2.22V     21.63mA    12.17mA    30.15mA
2.46V     20.01mA    9.92mA     29.39mA
2.94V     12.61mA    3.44mA     21.71mA
3.42V     3.086mA    915.9uA    4.992mA
3.6V      1.642mA    693.7uA    2.136mA
[Pullup]
|Voltage   I(typ)   I(min)   I(max)
-1.8V     4.049mA    1.82mA     3.179mA
-1.14V    13.06mA    6.095mA    21.8mA
-840mV    13.19mA    7.322mA    20.91mA
-480mV    9.59mA     5.802mA    14.97mA
480mV     -9.593mA   -6.013mA   -14.56mA
1.14V     -20.85mA   -12.95mA   -30.88mA
1.62V     -26.49mA   -16.18mA   -37.74mA
2.34V     -29.55mA   -16.49mA   -41.42mA
2.7V      -26.9mA    -11.83mA   -38.39mA
2.94V     -21.95mA   -7.614mA   -34.24mA
3.3V      -11.63mA   -2.715mA   -18.68mA
3.6V      -4.628mA   -1.246mA   -5.519mA
[GND_clamp]
|Voltage   I(typ)   I(min)   I(max)
-1.8V     -31.87mA   -21.26mA   -53.26mA
-1.24V    -12.54mA   -9.856mA   -17.9mA
-1.16V    -10.01mA   -8.305mA   -13.47mA
-1.08V    -7.671mA   -6.799mA   -9.84mA
-1V       -5.7mA     -5.36mA    -7.597mA
-880mV    -3.718mA   -3.424mA   -5.353mA
-760mV    -2.315mA   -1.966mA   -3.305mA
-640mV    -1.146mA   -1.028mA   -1.511mA
-560mV    -555.3uA   -579.2uA   -630.5uA
-480mV    -186.7uA   -253uA     -164.7uA
-280mV    -757.7nA   -4.254uA   -228.1nA
1.8V      133.3pA    1.256uA    189.8pA
[POWER_clamp]
|Voltage   I(typ)   I(min)   I(max)
-1.8V     32.87mA    22.14mA    54.5mA
-1.3V     15.56mA    11.92mA    22.77mA
-1.18V    11.71mA    9.568mA    15.92mA
-1.1V     9.352mA    8.045mA    12.13mA
-1V       6.882mA    6.226mA    9.046mA
-900mV    5.107mA    4.564mA    6.828mA
-800mV    3.698mA    3.167mA    4.771mA
-700mV    2.442mA    2.101mA    2.899mA
-560mV    987.6uA    987.5uA    899uA
-480mV    405.9uA    499.3uA    282.8uA
-380mV    56.76uA    122uA      23.73uA
0V        133.3pA    1.586nA    442.2pA
[Ramp]
| variable   typ   min   max
dV/dt_r   6.7907m/24.9711p   12.5846u/21.4463p  0.5561/33.9173p
dV/dt_f   6.1712m/22.2866p   98.5800u/10.6355p   0.4871/40.2381p
R_load =   50.0000
[Rising Waveform]
R_fixture=   50.0000
V_fixture=   1.8000
V_fixture_min=  1.6200
V_fixture_max=  1.8900
|time   V(typ)   V(min)   V(max)
0s        956.2mV    1.069V     773mV
286.9ps   956.3mV    1.069V     786.7mV
323.2ps   956.5mV    1.069V     1.137V
363.6ps   956.7mV    1.069V     1.659V
387.9ps   1.006V     1.069V     1.801V
412.1ps   1.199V     1.069V     1.859V
472.7ps   1.6V       1.07V      1.888V
521.2ps   1.751V     1.077V     1.89V
654.5ps   1.8V       1.492V     1.89V
800ps     1.8V       1.614V     1.89V
[Rising Waveform]
R_fixture=   50.0000
V_fixture=   0.0
V_fixture_min=  0.0
V_fixture_max=  0.0
|time   V(typ)   V(min)   V(max)
0s        5.687nV    158.7nV    6.917nV
327.3ps   -31.05uV   1.123uV    -27.48mV
345.5ps   102.8uV    1.241uV    128.6mV
390.9ps   -6.496mV   -14.23uV   822.5mV
454.5ps   72.72mV    -14.04uV   1.1V
509.1ps   593.3mV    -1.194mV   1.12V
563.6ps   812.5mV    -9.21mV    1.121V
654.5ps   872.4mV    32.73mV    1.121V
781.8ps   876.1mV    517.9mV    1.121V
900ps     876.1mV    590.2mV    1.121V
[Falling Waveform]
R_fixture=   50.0000
V_fixture=   1.8000
V_fixture_min=  1.6200
V_fixture_max=  1.8900
|time   V(typ)   V(min)   V(max)
0s        1.8V       1.62V      1.89V
315.2ps   1.8V       1.62V      1.894V
339.4ps   1.8V       1.62V      1.745V
406.1ps   1.8V       1.62V      1.021V
466.7ps   1.446V     1.621V     815.8mV
515.2ps   1.151V     1.626V     782.4mV
569.7ps   1.013V     1.63V      774.7mV
614.1ps   974mV      1.572V     773.2mV
735.4ps   957.1mV    1.177V     773mV
863.6ps   956.2mV    1.08V      773mV
[Falling Waveform]
R_fixture=   50.0000
V_fixture=   0.0
V_fixture_min=  0.0
V_fixture_max=  0.0
|time   V(typ)   V(min)   V(max)
0s        876.1mV    595.5mV    1.121V
274.7ps   876.1mV    595.5mV    1.123V
323.2ps   876.2mV    595.5mV    978.2mV
367.7ps   878mV      595.5mV    256.5mV
412.1ps   748mV      595.4mV    31.4mV
460.6ps   254.1mV    597.1mV    2.686mV
509.1ps   53.38mV    594.5mV    199.2uV
569.7ps   6.777mV    524.5mV    6.862uV
678.8ps   59.03uV    76.55mV    39.79nV
800ps     237.1nV    3.582mV    -3.71nV
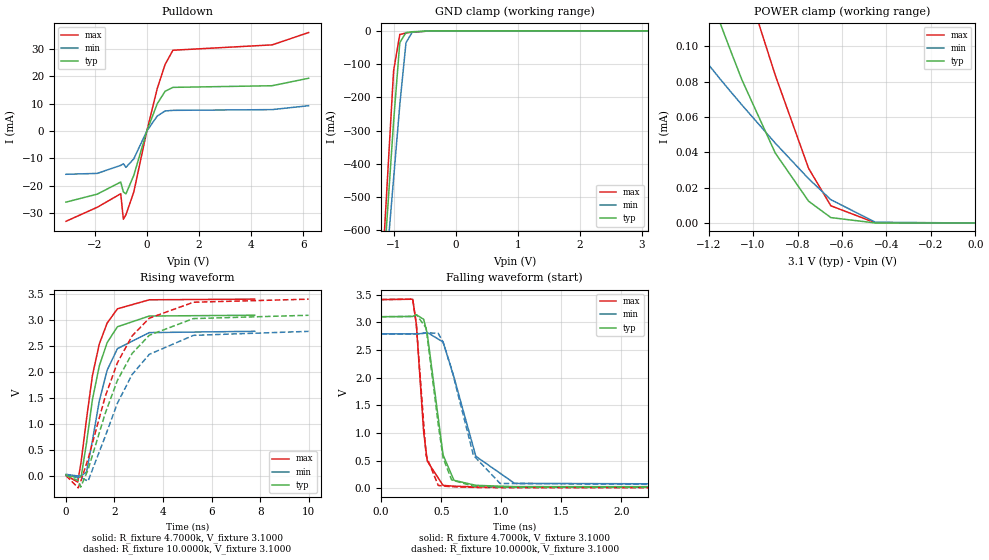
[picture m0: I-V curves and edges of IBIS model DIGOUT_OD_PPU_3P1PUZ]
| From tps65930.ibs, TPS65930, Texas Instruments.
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|   Model DIGOUT_OD_PPU_3P1PUZ
[Model]   DIGOUT_OD_PPU_3P1PUZ
Model_type   I/O_open_drain
Polarity   Non-Inverting
Enable   Active-Low
Vmeas =   1.6500V
Cref =  30.0000pF
Rref = 1000
Vref =  3.100V
C_comp   0.6131pF   0.5020pF   0.7285pF
[Temperature Range]   25.0000   0.1250k   -40.0000
[Pullup Reference]   3.1000V   2.7900V   3.4100V
[Pulldown Reference]   0.000V   0.000V   0.000V
[POWER Clamp Reference]   3.1000V   2.7900V   3.4100V
[GND Clamp Reference]   0.000V   0.000V   0.000V
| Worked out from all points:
|   slope of the pulldown table from 0 to 0.465 V, typ, clamps not added: 41.5 ohm
|   GND clamp passes 1 mA (typ) near -0.56 V on its own axis
|   rising waveform, R_fixture 4.7000k, V_fixture 3.1000: 20-80 % time 770ps typ, 805ps min, 760ps max; typ from 0.022 V to 3.1 V
|   rising waveform, R_fixture 10.0000k, V_fixture 3.1000: 20-80 % time 1.67ns typ, 1.71ns min, 1.65ns max; typ from 0.01 V to 3.1 V
|   falling waveform, R_fixture 4.7000k, V_fixture 3.1000: 20-80 % time 107ps typ, 208ps min, 68.4ps max; typ from 3.1 V to 0.022 V
|   falling waveform, R_fixture 10.0000k, V_fixture 3.1000: 20-80 % time 105ps typ, 196ps min, 67.1ps max; typ from 3.1 V to 0.01 V
[Pulldown]
| voltage   I(typ)   I(min)   I(max)
-3.1V     -26.05mA   -15.85mA   -33.07mA
-1.9V     -23.12mA   -15.53mA   -27.93mA
-1V       -18.68mA   -12.58mA   -22.97mA
-900mV    -22.31mA   -12mA      -32.34mA
-800mV    -23mA      -13.31mA   -30.65mA
-500mV    -16.26mA   -10.19mA   -22.35mA
0V        -146.7pA   -36.82pA   -768pA
400mV     10.01mA    5.501mA    15.6mA
700mV     14.55mA    7.328mA    24.37mA
1V        15.98mA    7.563mA    29.58mA
4.8V      16.58mA    7.832mA    31.54mA
6.2V      19.32mA    9.265mA    36.05mA
[GND_clamp]
| voltage   I(typ)   I(min)   I(max)
-3.1V     -6.084A    -5.118A    -7.02A
-1.2V     -826.2mA   -889.7mA   -777.2mA
-1.1V     -549.7mA   -667.3mA   -448.8mA
-1V       -273.2mA   -444.9mA   -120.4mA
-900mV    -35.33mA   -222.6mA   -10.99mA
-800mV    -5.277mA   -35.67mA   -6.678mA
-700mV    -2.813mA   -4.302mA   -4.117mA
-400mV    -77.1uA    -125.1uA   -88.54uA
3.1V      61.08pA    12.52nA    25.64pA
[POWER_clamp]
| voltage   I(typ)   I(min)   I(max)
-3.1V     475.1uA    389.9uA    555.7uA
-1.65V    227.1uA    165.1uA    277.5uA
-1.35V    167.7uA    113.5uA    216.2uA
-1.3V     156.2uA    105.3uA    205.4uA
-1.15V    113.9uA    81.87uA    170.6uA
-1.1V     97.31uA    74.31uA    157.5uA
-1.05V    81.11uA    66.87uA    142.8uA
-900mV    39.64uA    45.25uA    83.71uA
-750mV    12.36uA    25.09uA    30.93uA
-650mV    3.093uA    13.22uA    9.764uA
-450mV    42.59nA    479.5nA    142.8nA
0V        61.08pA    3.177nA    29.12pA
[Ramp]
| variable   typ   min   max
dV/dt_r   1.7079n/0.6712p   0.5287n/0.2990p   7.1901n/3.7159p
dV/dt_f   0.4848/0.2607n   0.2278/0.3808n   0.9267/0.2003n
R_load = 50.0000
[Rising Waveform]
R_fixture = 4.7000k
V_fixture = 3.1000
V_fixture_min = 2.7900
V_fixture_max = 3.4100
| time   V(typ)   V(min)   V(max)
0s        22.04mV    33.68mV    16.54mV
484.8ps   -31.24mV   2.818mV    -115.5mV
626.3ps   -12.91mV   3.998mV    278.1mV
848.5ps   640.1mV    81.74mV    1.104V
1.091ns   1.474V     685.1mV    1.939V
1.374ns   2.123V     1.449V     2.545V
1.697ns   2.571V     2.04V      2.948V
2.121ns   2.878V     2.456V     3.223V
3.434ns   3.084V     2.765V     3.397V
7.778ns   3.1V       2.79V      3.41V
[Rising Waveform]
R_fixture = 10.0000k
V_fixture = 3.1000
V_fixture_min = 2.7900
V_fixture_max = 3.4100
| time   V(typ)   V(min)   V(max)
0s        10.35mV    15.78mV    7.777mV
505.1ps   -86mV      -20.04mV   -226.6mV
606.1ps   -212.5mV   -27.01mV   -106.2mV
909.1ps   121.5mV    -97.61mV   326mV
1.616ns   1.205V     762.8mV    1.531V
2.121ns   1.845V     1.405V     2.185V
2.727ns   2.364V     1.958V     2.702V
3.434ns   2.714V     2.346V     3.043V
5.253ns   3.035V     2.712V     3.35V
10ns      3.099V     2.789V     3.409V
[Falling Waveform]
R_fixture = 4.7000k
V_fixture = 3.1000
V_fixture_min = 2.7900
V_fixture_max = 3.4100
| time   V(typ)   V(min)   V(max)
0s        3.1V       2.79V      3.41V
262.6ps   3.105V     2.79V      3.416V
292.9ps   3.135V     2.789V     2.959V
353.5ps   3.054V     2.799V     1.022V
383.8ps   2.791V     2.816V     489.7mV
515.2ps   602.6mV    2.643V     52.37mV
606.1ps   144.1mV    2.006V     37.94mV
787.9ps   53.28mV    578.7mV    24.73mV
1.111ns   29.96mV    88.5mV     17.52mV
10ns      22.04mV    33.68mV    16.54mV
[Falling Waveform]
R_fixture = 10.0000k
V_fixture = 3.1000
V_fixture_min = 2.7900
V_fixture_max = 3.4100
| time   V(typ)   V(min)   V(max)
0s        3.1V       2.79V      3.41V
262.6ps   3.105V     2.79V      3.418V
292.9ps   3.136V     2.789V     2.954V
373.7ps   2.899V     2.81V      593.7mV
474.7ps   1.163V     2.801V     52.57mV
515.2ps   552.9mV    2.643V     39.26mV
585.9ps   151.2mV    2.159V     29.37mV
767.7ps   38.65mV    595.6mV    16.28mV
989.9ps   21.62mV    87.54mV    10.35mV
6.566ns   10.35mV    15.78mV    7.777mV
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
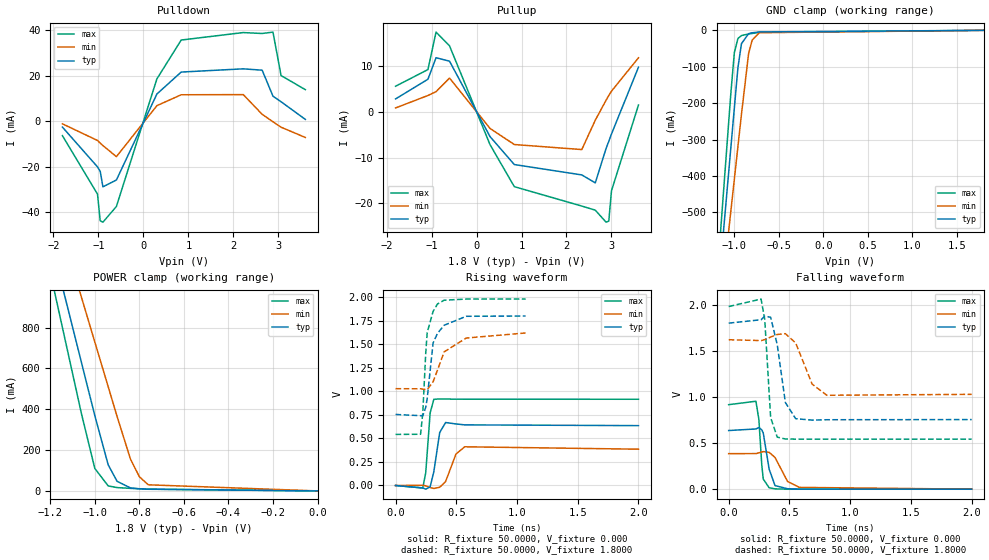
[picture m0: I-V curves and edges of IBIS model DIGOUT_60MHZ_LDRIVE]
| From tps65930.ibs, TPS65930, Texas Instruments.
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|   Model DIGOUT_60MHZ_LDRIVE
[Model]   DIGOUT_60MHZ_LDRIVE
Model_type   3-state
Polarity   Non-Inverting
Enable   Active-Low
Vmeas =   0.9000V
Cref =  10.0000pF
Rref = 100.0000M
Vref =  0.000V
C_comp   0.8973pF   0.9606pF   0.8462pF
[Temperature Range]   25.0000   0.1250k   -40.0000
[Pullup Reference]   1.8000V   1.6200V   1.9800V
[Pulldown Reference]   0.000V   0.000V   0.000V
[POWER Clamp Reference]   1.8000V   1.6200V   1.9800V
[GND Clamp Reference]   0.000V   0.000V   0.000V
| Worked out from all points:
|   slope of the pulldown table from 0 to 0.27 V, typ, clamps not added: 24.7 ohm
|   slope of the pullup table from 0 to 0.27 V, typ, clamps not added: 55 ohm
|   GND clamp passes 1 mA (typ) near -0.54 V on its own axis
|   POWER clamp passes 1 mA (typ) near -0.48 V on its own axis
|   rising waveform, R_fixture 50.0000, V_fixture 0.000: 20-80 % time 41.7ps typ, 61.2ps min, 30.4ps max; typ from 0 V to 0.636 V
|   rising waveform, R_fixture 50.0000, V_fixture 1.8000: 20-80 % time 67.2ps typ, 161ps min, 43.7ps max; typ from 0.754 V to 1.8 V
|   falling waveform, R_fixture 50.0000, V_fixture 0.000: 20-80 % time 43ps typ, 88ps min, 27.8ps max; typ from 0.636 V to 0 V
|   falling waveform, R_fixture 50.0000, V_fixture 1.8000: 20-80 % time 64.8ps typ, 104ps min, 38.7ps max; typ from 1.8 V to 0.754 V
[Pulldown]
| voltage   I(typ)   I(min)   I(max)
-1.8V     -2.64mA    -1.19mA    -6.4mA
-1.02V    -20.13mA   -8.52mA    -32.09mA
-960mV    -22.08mA   -9.664mA   -43.8mA
-900mV    -28.89mA   -10.74mA   -44.43mA
-600mV    -25.88mA   -15.61mA   -37.51mA
300mV     11.91mA    6.791mA    18.56mA
840mV     21.56mA    11.58mA    35.64mA
2.22V     22.98mA    11.65mA    38.92mA
2.64V     22.38mA    2.988mA    38.51mA
2.88V     10.96mA    -280.5uA   39.13mA
3.06V     8.516mA    -2.674mA   20.03mA
3.6V      747.9uA    -7.192mA   13.82mA
[Pullup]
| voltage   I(typ)   I(min)   I(max)
-1.8V     2.845mA    866.7uA    5.625mA
-1.08V    7.158mA    3.598mA    9.274mA
-900mV    11.87mA    4.437mA    17.48mA
-600mV    11.11mA    7.411mA    14.46mA
300mV     -5.404mA   -3.614mA   -7.16mA
840mV     -11.52mA   -7.136mA   -16.36mA
2.34V     -13.79mA   -8.241mA   -20.61mA
2.64V     -15.53mA   -1.8mA     -21.51mA
2.88V     -7.984mA   2.573mA    -24.14mA
2.94V     -6.438mA   3.583mA    -23.9mA
3V        -4.827mA   4.551mA    -17.26mA
3.6V      9.794mA    11.85mA    1.517mA
[GND_clamp]
| voltage   I(typ)   I(min)   I(max)
-1.8V     -2.438A    -2.194A    -2.686A
-1.16V    -658.2mA   -766.7mA   -570.6mA
-1.12V    -546.9mA   -677.4mA   -438.6mA
-1.08V    -435.7mA   -588mA     -306.8mA
-1.04V    -324.5mA   -498.6mA   -175.3mA
-1V       -213.5mA   -409.2mA   -61.21mA
-960mV    -102.9mA   -319.9mA   -22.61mA
-920mV    -36.65mA   -230.5mA   -14.3mA
-840mV    -9.105mA   -63.74mA   -10.05mA
-800mV    -6.79mA    -26.97mA   -8.546mA
-720mV    -4.387mA   -6.56mA    -5.718mA
1.8V      48pA       1.418uA    54.09pA
[POWER_clamp]
| voltage   I(typ)   I(min)   I(max)
-1.8V     3.846A     3.652A     4.045A
-1.18V    1.151A     1.387A     971.7mA
-1.14V    976.8mA    1.241A     773.8mA
-1.12V    890mA      1.168A     674.9mA
-1.06V    629.4mA    949mA      378.3mA
-1V       369mA      729.9mA    110.2mA
-940mV    128.1mA    510.9mA    24.63mA
-900mV    47.15mA    364.9mA    16.38mA
-840mV    14.84mA    156.3mA    12.52mA
-800mV    10.29mA    69.73mA    10.66mA
-760mV    8.221mA    30mA       8.914mA
0V        283.7pA    1.253nA    2.035nA
[Ramp]
| variable   typ   min   max
dV/dt_r   0.3851/41.8721p   0.2472/66.9411p   0.5497/30.1121p
dV/dt_f   0.6287/64.4494p   0.1290/35.7092p   0.8625/41.3396p
R_load = 50.0000
[Rising Waveform]
R_fixture = 50.0000
V_fixture = 0.000
V_fixture_min = 0.000
V_fixture_max = 0.000
| time   V(typ)   V(min)   V(max)
0s        16.86nV    377nV      33.14nV
224.2ps   -25.83mV   2.292mV    -26.38mV
248.5ps   -38.98mV   -3.676mV   135.6mV
284.8ps   -13.87mV   -22.12mV   771.3mV
315.2ps   146.4mV    -31.71mV   915.4mV
363.6ps   562.9mV    -18.81mV   919.6mV
412.1ps   668.8mV    41.92mV    918.3mV
497ps     653.6mV    333.4mV    916.8mV
569.7ps   643.8mV    411.1mV    916.2mV
2ns       635.8mV    385.5mV    915.9mV
[Rising Waveform]
R_fixture = 50.0000
V_fixture = 1.8000
V_fixture_min = 1.6200
V_fixture_max = 1.9800
| time   V(typ)   V(min)   V(max)
0s        754.4mV    1.028V     542.6mV
206.1ps   741.5mV    1.027V     544.1mV
224.2ps   740.4mV    1.024V     769.6mV
248.5ps   830.3mV    1.018V     1.406V
260.6ps   923.3mV    1.018V     1.625V
309.1ps   1.514V     1.101V     1.849V
345.5ps   1.616V     1.226V     1.928V
400ps     1.702V     1.419V     1.968V
581.8ps   1.797V     1.566V     1.98V
1.071ns   1.8V       1.62V      1.98V
[Falling Waveform]
R_fixture = 50.0000
V_fixture = 0.000
V_fixture_min = 0.000
V_fixture_max = 0.000
| time   V(typ)   V(min)   V(max)
0s        635.7mV    385mV      915.9mV
224.2ps   652.7mV    386mV      953.5mV
248.5ps   667.8mV    393.3mV    757.5mV
272.7ps   642.7mV    403.1mV    258.5mV
284.8ps   608.6mV    407.4mV    109.8mV
333.3ps   216.6mV    398.9mV    15.41mV
381.8ps   38.42mV    343.4mV    3.332mV
484.8ps   4.442mV    83.69mV    120uV
581.8ps   484uV      19.29mV    6.844uV
2ns       13.86nV    231.5nV    32.8nV
[Falling Waveform]
R_fixture = 50.0000
V_fixture = 1.8000
V_fixture_min = 1.6200
V_fixture_max = 1.9800
| time   V(typ)   V(min)   V(max)
0s        1.8V       1.62V      1.98V
266.7ps   1.837V     1.611V     2.061V
297ps     1.875V     1.621V     1.84V
345.5ps   1.864V     1.649V     775.6mV
400ps     1.565V     1.677V     563.8mV
466.7ps   939.5mV    1.686V     544.3mV
551.5ps   764.1mV    1.585V     542.4mV
686.9ps   748.7mV    1.139V     542.5mV
808.1ps   752.7mV    1.018V     542.6mV
2ns       754.4mV    1.028V     542.6mV
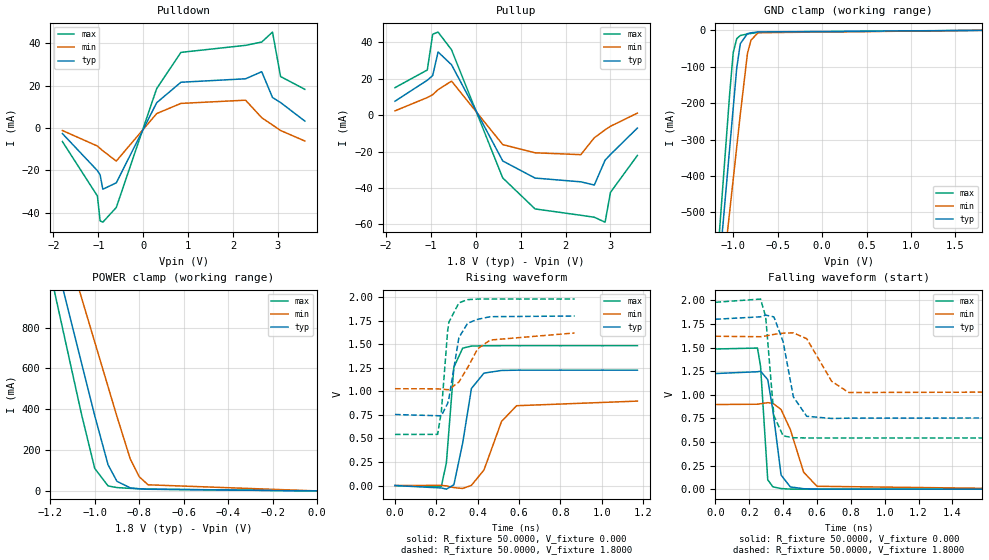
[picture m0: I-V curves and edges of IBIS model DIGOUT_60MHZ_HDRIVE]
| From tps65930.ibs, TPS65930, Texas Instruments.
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|   Model DIGOUT_60MHZ_HDRIVE
[Model]   DIGOUT_60MHZ_HDRIVE
Model_type   3-state
Polarity   Non-Inverting
Enable   Active-Low
Vmeas =   0.9000V
Cref =  30.0000pF
Rref = 100.0000M
Vref =  0.000V
C_comp   0.6924pF   0.7413pF   0.6578pF
[Temperature Range]   25.0000   0.1250k   -40.0000
[Pullup Reference]   1.8000V   1.6200V   1.9800V
[Pulldown Reference]   0.000V   0.000V   0.000V
[POWER Clamp Reference]   1.8000V   1.6200V   1.9800V
[GND Clamp Reference]   0.000V   0.000V   0.000V
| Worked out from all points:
|   slope of the pulldown table from 0 to 0.27 V, typ, clamps not added: 24.7 ohm
|   slope of the pullup table from 0 to 0.27 V, typ, clamps not added: 20.7 ohm
|   GND clamp passes 1 mA (typ) near -0.54 V on its own axis
|   POWER clamp passes 1 mA (typ) near -0.48 V on its own axis
|   rising waveform, R_fixture 50.0000, V_fixture 0.000: 20-80 % time 49.6ps typ, 91.7ps min, 30.2ps max; typ from 0 V to 1.23 V
|   rising waveform, R_fixture 50.0000, V_fixture 1.8000: 20-80 % time 47.3ps typ, 101ps min, 31.8ps max; typ from 0.754 V to 1.8 V
|   falling waveform, R_fixture 50.0000, V_fixture 0.000: 20-80 % time 48.6ps typ, 97.1ps min, 28.6ps max; typ from 1.23 V to 0 V
|   falling waveform, R_fixture 50.0000, V_fixture 1.8000: 20-80 % time 65.9ps typ, 106ps min, 39.1ps max; typ from 1.8 V to 0.754 V
[Pulldown]
| voltage   I(typ)   I(min)   I(max)
-1.8V     -2.64mA    -1.19mA    -6.4mA
-1.02V    -20.13mA   -8.52mA    -32.09mA
-960mV    -22.08mA   -9.664mA   -43.8mA
-900mV    -28.89mA   -10.74mA   -44.43mA
-600mV    -25.88mA   -15.61mA   -37.51mA
300mV     11.91mA    6.791mA    18.56mA
840mV     21.56mA    11.58mA    35.64mA
2.28V     23.19mA    13.1mA     38.96mA
2.64V     26.53mA    4.827mA    40.52mA
2.88V     14.35mA    1.404mA    45.21mA
3.06V     11.98mA    -1.193mA   24.24mA
3.6V      3.246mA    -6.148mA   18.23mA
[Pullup]
| voltage   I(typ)   I(min)   I(max)
-1.8V     7.601mA    2.312mA    15.03mA
-1.08V    19.11mA    9.608mA    24.73mA
-960mV    21.67mA    11.16mA    44.33mA
-840mV    34.62mA    13.94mA    45.51mA
-540mV    27.58mA    18.61mA    35.8mA
600mV     -25.16mA   -16.19mA   -34.47mA
1.32V     -34.55mA   -20.69mA   -51.47mA
2.34V     -36.61mA   -21.71mA   -54.95mA
2.64V     -38.37mA   -12.44mA   -56.03mA
2.88V     -24.74mA   -8.104mA   -58.75mA
3V        -21.61mA   -6.144mA   -42.39mA
3.6V      -7.107mA   1.084mA    -22.15mA
[GND_clamp]
| voltage   I(typ)   I(min)   I(max)
-1.8V     -2.438A    -2.194A    -2.686A
-1.16V    -658.2mA   -766.7mA   -570.6mA
-1.12V    -546.9mA   -677.4mA   -438.6mA
-1.08V    -435.7mA   -588mA     -306.8mA
-1.04V    -324.5mA   -498.6mA   -175.3mA
-1V       -213.5mA   -409.2mA   -61.21mA
-960mV    -102.9mA   -319.9mA   -22.61mA
-920mV    -36.65mA   -230.5mA   -14.3mA
-840mV    -9.105mA   -63.74mA   -10.05mA
-800mV    -6.79mA    -26.97mA   -8.546mA
-720mV    -4.387mA   -6.56mA    -5.718mA
1.8V      48pA       1.418uA    54.09pA
[POWER_clamp]
| voltage   I(typ)   I(min)   I(max)
-1.8V     3.846A     3.652A     4.045A
-1.18V    1.151A     1.387A     971.7mA
-1.14V    976.8mA    1.241A     773.8mA
-1.12V    890mA      1.168A     674.9mA
-1.06V    629.4mA    949mA      378.3mA
-1V       369mA      729.9mA    110.2mA
-940mV    128.1mA    510.9mA    24.63mA
-900mV    47.15mA    364.9mA    16.38mA
-840mV    14.84mA    156.3mA    12.52mA
-800mV    10.29mA    69.73mA    10.66mA
-760mV    8.221mA    30mA       8.914mA
0V        283.7pA    1.253nA    2.035nA
[Ramp]
| variable   typ   min   max
dV/dt_r   0.7349/52.6421p   0.5380/93.7376p   0.8908/32.5783p
dV/dt_f   0.6274/66.1997p   0.3550/98.4677p   0.8625/43.5084p
R_load = 50.0000
[Rising Waveform]
R_fixture = 50.0000
V_fixture = 0.000
V_fixture_min = 0.000
V_fixture_max = 0.000
| time   V(typ)   V(min)   V(max)
0s        19.49nV    595nV      33.17nV
224.2ps   -25.51mV   2.269mV    -7.277mV
248.5ps   -38.22mV   -3.633mV   240.4mV
284.8ps   8.588mV    -21.86mV   1.257V
327.3ps   451.5mV    -30.76mV   1.459V
369.7ps   1.031V     2.37mV     1.481V
430.3ps   1.194V     165.9mV    1.484V
515.2ps   1.222V     680.7mV    1.485V
587.9ps   1.225V     847.7mV    1.485V
1.172ns   1.225V     896.7mV    1.485V
[Rising Waveform]
R_fixture = 50.0000
V_fixture = 1.8000
V_fixture_min = 1.6200
V_fixture_max = 1.9800
| time   V(typ)   V(min)   V(max)
0s        754.4mV    1.028V     542.6mV
206.1ps   741.6mV    1.027V     543.7mV
224.2ps   740.5mV    1.024V     783.1mV
254.5ps   871.8mV    1.018V     1.639V
260.6ps   922.6mV    1.018V     1.734V
309.1ps   1.571V     1.1V       1.94V
351.5ps   1.724V     1.253V     1.974V
400ps     1.765V     1.453V     1.98V
460.6ps   1.793V     1.545V     1.98V
868.7ps   1.8V       1.62V      1.98V
[Falling Waveform]
R_fixture = 50.0000
V_fixture = 0.000
V_fixture_min = 0.000
V_fixture_max = 0.000
| time   V(typ)   V(min)   V(max)
0s        1.225V     896.7mV    1.485V
248.5ps   1.244V     899.9mV    1.495V
266.7ps   1.25V      905.1mV    1.301V
309.1ps   1.161V     916.5mV    99.61mV
339.4ps   837mV      909.7mV    25.17mV
387.9ps   150mV      844mV      6.174mV
442.4ps   24.18mV    633.2mV    1.1mV
521.2ps   4.69mV     180mV      93.16uV
600ps     805.5uV    30.67mV    9.346uV
2ns       19.09nV    607.2nV    30.98nV
[Falling Waveform]
R_fixture = 50.0000
V_fixture = 1.8000
V_fixture_min = 1.6200
V_fixture_max = 1.9800
| time   V(typ)   V(min)   V(max)
0s        1.8V       1.62V      1.98V
266.7ps   1.826V     1.615V     2.014V
297ps     1.844V     1.623V     1.826V
345.5ps   1.825V     1.64V      777.9mV
400ps     1.563V     1.653V     564.4mV
460.6ps   977.6mV    1.656V     545mV
539.4ps   772.2mV    1.594V     542.4mV
686.9ps   749mV      1.143V     542.5mV
787.9ps   752.2mV    1.024V     542.6mV
1.636ns   754.4mV    1.028V     542.6mV
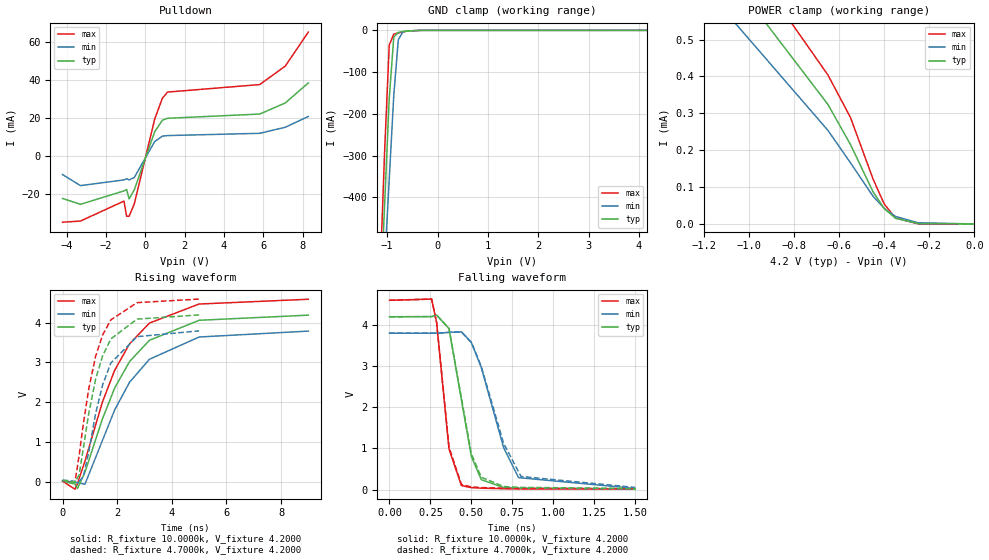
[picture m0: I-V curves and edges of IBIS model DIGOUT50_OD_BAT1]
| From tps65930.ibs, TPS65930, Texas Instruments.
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|   Model DIGOUT50_OD_BAT1
[Model]   DIGOUT50_OD_BAT1
Model_type   3-state
Polarity   Non-Inverting
Enable   Active-Low
Vmeas =   2.1000V
Cref =  10.0000pF
Rref =  4.7k
Vref =  2.1V
C_comp   0.3728pF   0.3513pF   0.3868pF
[Temperature Range]   25.0000   0.1250k   -40.0000
[Pullup Reference]   4.2000V   3.8000V   4.6000V
[Pulldown Reference]   0.000V   0.000V   0.000V
[POWER Clamp Reference]   4.2000V   3.8000V   4.6000V
[GND Clamp Reference]   0.000V   0.000V   0.000V
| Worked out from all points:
|   slope of the pulldown table from 0 to 0.63 V, typ, clamps not added: 40.4 ohm
|   GND clamp passes 1 mA (typ) near -0.55 V on its own axis
|   POWER clamp passes 1 mA (typ) near -1.51 V on its own axis
|   rising waveform, R_fixture 10.0000k, V_fixture 4.2000: 20-80 % time 1.74ns typ, 1.79ns min, 1.7ns max; typ from 0.013 V to 4.19 V
|   rising waveform, R_fixture 4.7000k, V_fixture 4.2000: 20-80 % time 821ps typ, 842ps min, 800ps max; typ from 0.029 V to 4.2 V
|   falling waveform, R_fixture 10.0000k, V_fixture 4.2000: 20-80 % time 104ps typ, 168ps min, 67.9ps max; typ from 4.2 V to 0.014 V
|   falling waveform, R_fixture 4.7000k, V_fixture 4.2000: 20-80 % time 106ps typ, 174ps min, 69.5ps max; typ from 4.2 V to 0.03 V
[Pulldown]
| voltage   I(typ)   I(min)   I(max)
-4.2V     -22.4mA    -9.831mA   -34.87mA
-3.29V    -25.47mA   -15.63mA   -34.27mA
-1.08V    -18.41mA   -12.63mA   -23.77mA
-950mV    -17.64mA   -12.02mA   -31.75mA
-820mV    -22.64mA   -12.63mA   -31.75mA
-560mV    -17.87mA   -11.38mA   -25.3mA
480mV     12.73mA    7.55mA     19.39mA
870mV     18.76mA    10.4mA     30.37mA
1.13V     19.77mA    10.67mA    33.55mA
5.81V     21.99mA    11.86mA    37.49mA
7.11V     27.83mA    15.05mA    47.21mA
8.28V     38.36mA    20.73mA    65.09mA
[Pullup]
| voltage   I(typ)   I(min)   I(max)
-4.08V    0A         0A         0A
-3.95V    0A         0A         0A
-3.82V    0A         0A         0A
8.27V     0A         0A         0A
[GND_clamp]
| voltage   I(typ)   I(min)   I(max)
-4.2V     -9.127A    -7.565A    -10.63A
-1.14V    -660.9mA   -756.8mA   -580.6mA
-1.05V    -412mA     -556.6mA   -284.9mA
-960mV    -163.1mA   -356.4mA   -35.2mA
-870mV    -16.36mA   -156.3mA   -9.175mA
-780mV    -4.887mA   -22.5mA    -6.13mA
-690mV    -2.882mA   -3.933mA   -3.727mA
-600mV    -1.51mA    -1.525mA   -1.795mA
-330mV    -10.63uA   -34.24uA   -4.29uA
4.17V     -42.93pA   27.71uA    28.93pA
[POWER_clamp]
| voltage   I(typ)   I(min)   I(max)
-4.2V     2.663mA    2.284mA    3.048mA
-1.65V    1.108mA    945.9uA    1.262mA
-1.6V     1.07mA     912.7uA    1.22mA
-1.4V     918.8uA    778.9uA    1.053mA
-1.25V    804.7uA    677.9uA    927.1uA
-650mV    324.1uA    253.8uA    404uA
-550mV    215.5uA    165.9uA    288.9uA
-450mV    87.38uA    75.28uA    122.3uA
-400mV    41.6uA     42.06uA    53.85uA
-350mV    15.43uA    20.38uA    15.97uA
-250mV    1.136uA    3.235uA    513.5nA
0V        75.26pA    3.944nA    50.92pA
[Ramp]
| variable   typ   min   max
dV/dt_r   0.7376n/84.3828f  8.2453n/53.6964p   0.6717n/22.8074p
dV/dt_f   0.6000/0.2248n   0.3199/0.3251n   1.0305/0.1665n
R_load = 50.0000
[Rising Waveform]
R_fixture = 10.0000k
V_fixture = 4.2000
V_fixture_min = 3.8000
V_fixture_max = 4.6000
| time   V(typ)   V(min)   V(max)
0s        13.44mV    19.47mV    10.09mV
454.5ps   -62.02mV   -21.37mV   -190.6mV
545.5ps   -172.8mV   -28.35mV   -49.51mV
818.2ps   230.2mV    -66.58mV   510.2mV
1.455ns   1.57V      1.027V     1.993V
1.909ns   2.357V     1.807V     2.803V
2.455ns   3.023V     2.502V     3.469V
3.182ns   3.557V     3.079V     3.99V
5ns       4.06V      3.639V     4.469V
9ns       4.189V     3.788V     4.589V
[Rising Waveform]
R_fixture = 4.7000k
V_fixture = 4.2000
V_fixture_min = 3.8000
V_fixture_max = 4.6000
| time   V(typ)   V(min)   V(max)
0s        28.61mV    41.52mV    21.46mV
454.5ps   -22.43mV   4.466mV    -11.67mV
606.1ps   166mV      9.796mV    654.8mV
757.6ps   826.6mV    115.2mV    1.438V
959.6ps   1.72V      750.8mV    2.34V
1.212ns   2.583V     1.717V     3.158V
1.465ns   3.162V     2.43V      3.687V
1.768ns   3.591V     2.984V     4.07V
2.727ns   4.089V     3.648V     4.504V
5ns       4.195V     3.794V     4.594V
[Falling Waveform]
R_fixture = 10.0000k
V_fixture = 4.2000
V_fixture_min = 3.8000
V_fixture_max = 4.6000
| time   V(typ)   V(min)   V(max)
0s        4.2V       3.8V       4.6V
257.6ps   4.203V     3.8V       4.63V
287.9ps   4.243V     3.799V     4.056V
363.6ps   3.912V     3.821V     982.4mV
439.4ps   2.174V     3.834V     97.29mV
500ps     804.1mV    3.575V     46.67mV
560.6ps   241.4mV    2.965V     34.78mV
697ps     50.38mV    1.019V     21.23mV
787.9ps   35.54mV    290.4mV    16.07mV
1.5ns     14.41mV    28.32mV    10.25mV
[Falling Waveform]
R_fixture = 4.7000k
V_fixture = 4.2000
V_fixture_min = 3.8000
V_fixture_max = 4.6000
| time   V(typ)   V(min)   V(max)
0s        4.2V       3.8V       4.6V
257.6ps   4.203V     3.8V       4.629V
287.9ps   4.242V     3.799V     4.061V
363.6ps   3.914V     3.821V     1.032V
439.4ps   2.226V     3.831V     126.3mV
500ps     869.1mV    3.578V     64.13mV
560.6ps   300.3mV    2.992V     48.93mV
697ps     74.38mV    1.122V     33.47mV
803ps     52.83mV    318.7mV    27.28mV
1.5ns     29.69mV    52.43mV    21.63mV
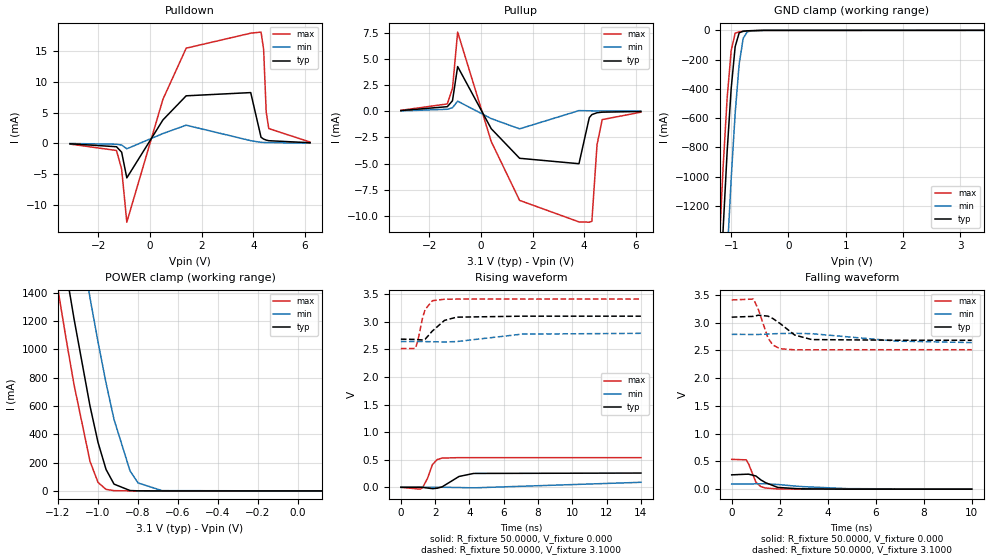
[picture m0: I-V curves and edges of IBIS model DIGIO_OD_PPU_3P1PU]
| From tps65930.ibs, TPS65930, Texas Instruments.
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|   Model DIGIO_OD_PPU_3P1PU
[Model]   DIGIO_OD_PPU_3P1PU
Model_type   I/O
Polarity   Non-Inverting
Enable   Active-Low
Vinl =   1.1935V
Vinh =   1.8135V
Vmeas =   1.6500V
Cref =  30.0000pF
Rref = 100.0000M
Vref =  0.000V
C_comp   1.0815pF   1.5672pF   1.3441pF
[Temperature Range]   25.0000   0.1250k   -40.0000
[Pullup Reference]   3.1000V   2.7900V   3.4100V
[Pulldown Reference]   0.000V   0.000V   0.000V
[POWER Clamp Reference]   3.1000V   2.7900V   3.4100V
[GND Clamp Reference]   0.000V   0.000V   0.000V
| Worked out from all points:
|   slope of the pulldown table from 0 to 0.465 V, typ, clamps not added: 135 ohm
|   slope of the pullup table from 0 to 0.465 V, typ, clamps not added: 245 ohm
|   GND clamp passes 1 mA (typ) near -0.54 V on its own axis
|   POWER clamp passes 1 mA (typ) near -0.81 V on its own axis
|   rising waveform, R_fixture 50.0000, V_fixture 0.000: 20-80 % time 793ps typ, 2.31ns min, 411ps max; typ from 0 V to 0.258 V
|   rising waveform, R_fixture 50.0000, V_fixture 3.1000: 20-80 % time 809ps typ, 2.38ns min, 421ps max; typ from 2.68 V to 3.1 V
|   falling waveform, R_fixture 50.0000, V_fixture 0.000: 20-80 % time 629ps typ, 1.87ns min, 324ps max; typ from 0.258 V to 0 V
|   falling waveform, R_fixture 50.0000, V_fixture 3.1000: 20-80 % time 753ps typ, 1.96ns min, 438ps max; typ from 3.1 V to 2.68 V
[Pulldown]
| voltage   I(typ)   I(min)   I(max)
-3.1V     -65uA      -19uA      -115uA
-1.3V     -545.9uA   -136.2uA   -1.159mA
-1.1V     -1.439mA   -275.5uA   -4.202mA
-900mV    -5.622mA   -882.6uA   -12.84mA
500mV     3.828mA    1.605mA    7.195mA
1.4V      7.749mA    2.964mA    15.51mA
3.9V      8.273mA    442.4uA    17.95mA
4.3V      991.9uA    170.7uA    18.13mA
4.4V      699.7uA    147.2uA    15.34mA
4.5V      536.9uA    129.3uA    5.129mA
4.6V      434.3uA    115.2uA    2.409mA
6.2V      104uA      42uA       217uA
[Pullup]
| voltage   I(typ)   I(min)   I(max)
-3.1V     69uA       39uA       92uA
-1.3V     442.3uA    195.9uA    704.6uA
-1.1V     1.01mA     344.3uA    2.19mA
-900mV    4.277mA    967.5uA    7.573mA
400mV     -1.66mA    -696.7uA   -2.883mA
1.5V      -4.491mA   -1.676mA   -8.515mA
3.8V      -5.01mA    66.7uA     -10.57mA
4.2V      -607.2uA   49.9uA     -10.6mA
4.3V      -314.4uA   44.7uA     -10.51mA
4.5V      -137.5uA   37.1uA     -3.192mA
4.7V      -81.6uA    31.8uA     -793.1uA
6.2V      -15uA      16uA       -82uA
[GND_clamp]
| voltage   I(typ)   I(min)   I(max)
-3.1V     -20.18A    -20.88A    -19.81A
-1.21V    -1.944A    -2.722A    -1.496A
-1.14V    -1.358A    -2.119A    -931.7mA
-1.07V    -828.2mA   -1.545A    -463.2mA
-1V       -400.1mA   -1.017A    -139.5mA
-930mV    -111.5mA   -566.8mA   -19.63mA
-860mV    -17.2mA    -230.7mA   -9.756mA
-790mV    -5.711mA   -54.5mA    -7.195mA
-720mV    -3.473mA   -10.96mA   -5.135mA
-650mV    -2.254mA   -3.258mA   -3.378mA
-440mV    -340.6uA   -330.5uA   -480.4uA
3.41V     0A         0A         0A
[POWER_clamp]
| voltage   I(typ)   I(min)   I(max)
-3.08V    20.1A      20.83A     19.69A
-1.2V     1.902A     2.726A     1.422A
-1.16V    1.554A     2.374A     1.078A
-1.12V    1.217A     2.028A     750.9mA
-1.04V    599.1mA    1.364A     208.6mA
-1V       342.7mA    1.053A     60.09mA
-960mV    152mA      763.2mA    10.89mA
-920mV    48.17mA    505mA      1.914mA
-840mV    2.737mA    141.5mA    328.4uA
-800mV    698.6uA    56.57mA    251.6uA
-680mV    95.12uA    2.068mA    134.3uA
120mV     0A         0A         0A
|  3.1000   0.0000pA   0.0000nA   00.0000pA
[Ramp]
| variable   typ   min   max
dV/dt_r   0.1549/0.7903n   54.5893m/2.3351n  0.3223/0.4208n
dV/dt_f   0.2496/0.7535n   89.4222m/2.0654n  0.5383/0.4503n
R_load = 50.0000
[Rising Waveform]
R_fixture = 50.0000
V_fixture = 0.000
V_fixture_min = 0.000
V_fixture_max = 0.000
| time   V(typ)   V(min)   V(max)
0s        251.6pV    597.4pV    205pV
1.131ns   1.53mV     698.7uV    -33.74mV
1.273ns   -1.703mV   945.8uV    -2.746mV
1.556ns   -13.33mV   1.247mV    164.4mV
1.838ns   -24.58mV   1.327mV    409.7mV
2.121ns   -16.63mV   1.2mV      502.9mV
2.404ns   7.902mV    652.7uV    529.6mV
3.394ns   196.4mV    -4.251mV   537.4mV
4.242ns   251.1mV    -10.11mV   537.1mV
14ns      258.1mV    90.6mV     537.1mV
[Rising Waveform]
R_fixture = 50.0000
V_fixture = 3.1000
V_fixture_min = 2.7900
V_fixture_max = 3.4100
| time   V(typ)   V(min)   V(max)
0s        2.684V     2.641V     2.513V
848.5ps   2.679V     2.642V     2.515V
989.9ps   2.674V     2.642V     2.655V
1.273ns   2.669V     2.641V     3.081V
1.414ns   2.682V     2.64V      3.219V
1.838ns   2.831V     2.637V     3.38V
2.546ns   3.024V     2.633V     3.407V
3.253ns   3.082V     2.64V      3.41V
7.071ns   3.1V       2.775V     3.41V
14ns      3.1V       2.789V     3.41V
[Falling Waveform]
R_fixture = 50.0000
V_fixture = 0.000
V_fixture_min = 0.000
V_fixture_max = 0.000
| time   V(typ)   V(min)   V(max)
0s        258.1mV    90.99mV    537.1mV
606.1ps   269.3mV    92.22mV    528.5mV
707.1ps   269.8mV    93.4mV     452.3mV
1.01ns    237.2mV    96.19mV    125.6mV
1.212ns   167.6mV    97.08mV    45.67mV
1.414ns   116.4mV    96.79mV    21.06mV
1.919ns   31.26mV    84.16mV    3.812mV
2.828ns   6.601mV    48.45mV    40.9uV
4.848ns   122.7uV    9.062mV    4.306uV
10ns      53.32nV    434.7uV    1.503uV
[Falling Waveform]
R_fixture = 50.0000
V_fixture = 3.1000
V_fixture_min = 2.7900
V_fixture_max = 3.4100
| time   V(typ)   V(min)   V(max)
0s        3.1V       2.79V      3.41V
909.1ps   3.114V     2.788V     3.426V
1.111ns   3.135V     2.788V     3.237V
1.515ns   3.118V     2.794V     2.721V
1.717ns   3.075V     2.8V       2.597V
2.02ns    2.984V     2.805V     2.53V
2.626ns   2.777V     2.808V     2.511V
3.333ns   2.696V     2.802V     2.512V
6.869ns   2.684V     2.668V     2.513V
10ns      2.684V     2.642V     2.513V
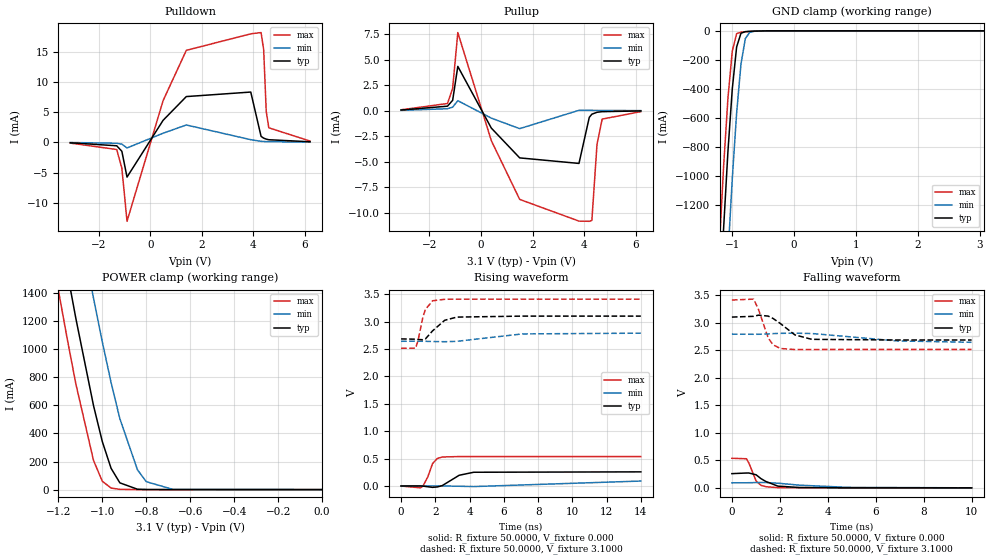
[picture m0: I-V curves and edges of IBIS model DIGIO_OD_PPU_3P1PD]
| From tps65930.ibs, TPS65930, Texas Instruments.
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|   Model DIGIO_OD_PPU_3P1PD
[Model]   DIGIO_OD_PPU_3P1PD
Model_type   I/O
Polarity   Non-Inverting
Enable   Active-Low
Vinl =   1.1935V
Vinh =   1.8135V
Vmeas =   1.6500V
Cref =  30.0000pF
Rref = 100.0000M
Vref =  0.000V
C_comp   1.0815pF   1.5672pF   1.3441pF
[Temperature Range]   25.0000   0.1250k   -40.0000
[Pullup Reference]   3.1000V   2.7900V   3.4100V
[Pulldown Reference]   0.000V   0.000V   0.000V
[POWER Clamp Reference]   3.1000V   2.7900V   3.4100V
[GND Clamp Reference]   0.000V   0.000V   0.000V
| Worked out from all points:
|   slope of the pulldown table from 0 to 0.465 V, typ, clamps not added: 135 ohm
|   slope of the pullup table from 0 to 0.465 V, typ, clamps not added: 239 ohm
|   GND clamp passes 1 mA (typ) near -0.56 V on its own axis
|   POWER clamp passes 1 mA (typ) near -0.81 V on its own axis
|   rising waveform, R_fixture 50.0000, V_fixture 0.000: 20-80 % time 793ps typ, 2.31ns min, 411ps max; typ from 0 V to 0.258 V
|   rising waveform, R_fixture 50.0000, V_fixture 3.1000: 20-80 % time 809ps typ, 2.38ns min, 421ps max; typ from 2.68 V to 3.1 V
|   falling waveform, R_fixture 50.0000, V_fixture 0.000: 20-80 % time 629ps typ, 1.87ns min, 324ps max; typ from 0.258 V to 0 V
|   falling waveform, R_fixture 50.0000, V_fixture 3.1000: 20-80 % time 753ps typ, 1.96ns min, 438ps max; typ from 3.1 V to 2.68 V
[Pulldown]
| voltage   I(typ)   I(min)   I(max)
-3.1V     -67uA      -21uA      -118uA
-1.3V     -561.8uA   -144.3uA   -1.184mA
-1.1V     -1.479mA   -290.8uA   -4.29mA
-900mV    -5.76mA    -925uA     -13.1mA
500mV     3.668mA    1.522mA    6.94mA
1.4V      7.603mA    2.888mA    15.28mA
3.9V      8.355mA    448.7uA    18.02mA
4.3V      1.002mA    173.1uA    18.23mA
4.4V      706.6uA    149.3uA    15.42mA
4.5V      542.2uA    131.1uA    5.157mA
4.6V      438.5uA    116.8uA    2.422mA
6.2V      105uA      42uA       218uA
[Pullup]
| voltage   I(typ)   I(min)   I(max)
-3.1V     70uA       40uA       93uA
-1.3V     449.2uA    199.5uA    712.5uA
-1.1V     1.026mA    350.9uA    2.215mA
-900mV    4.353mA    987.7uA    7.674mA
400mV     -1.702mA   -725.2uA   -2.936mA
1.5V      -4.626mA   -1.755mA   -8.701mA
3.8V      -5.17mA    43.5uA     -10.83mA
4.2V      -647uA     43.5uA     -10.85mA
4.3V      -337.6uA   39.4uA     -10.76mA
4.5V      -149.3uA   33.2uA     -3.287mA
4.7V      -89.4uA    28.7uA     -819.4uA
6.2V      -17uA      15uA       -86uA
[GND_clamp]
| voltage   I(typ)   I(min)   I(max)
-3.1V     -20.18A    -20.88A    -19.81A
-1.21V    -1.944A    -2.722A    -1.496A
-1.14V    -1.358A    -2.119A    -931.7mA
-1.07V    -828.1mA   -1.545A    -463.1mA
-1V       -400mA     -1.017A    -139.3mA
-930mV    -111.4mA   -566.8mA   -19.38mA
-860mV    -17.05mA   -230.7mA   -9.5mA
-790mV    -5.551mA   -54.43mA   -6.939mA
-720mV    -3.312mA   -10.88mA   -4.878mA
-650mV    -2.094mA   -3.175mA   -3.122mA
-440mV    -180.1uA   -246.9uA   -223.5uA
3.06V     76.1pA     18.64nA    39.43pA
[POWER_clamp]
| voltage   I(typ)   I(min)   I(max)
-3.08V    20.1A      20.83A     19.69A
-1.2V     1.902A     2.726A     1.422A
-1.16V    1.554A     2.374A     1.078A
-1.12V    1.217A     2.028A     750.9mA
-1.04V    599.1mA    1.364A     208.6mA
-1V       342.7mA    1.053A     60.01mA
-960mV    151.9mA    763.2mA    10.8mA
-920mV    48.1mA     505mA      1.813mA
-840mV    2.655mA    141.5mA    228.9uA
-800mV    616.6uA    56.53mA    153.6uA
-680mV    20.28uA    2.023mA    44.21uA
0V        77.81pA    3.209nA    47.54pA
[Ramp]
| variable   typ   min   max
dV/dt_r   0.1549/0.7903n   54.5893m/2.3351n  0.3223/0.4208n
dV/dt_f   0.2496/0.7535n   89.4222m/2.0654n  0.5383/0.4503n
R_load = 50.0000
[Rising Waveform]
R_fixture = 50.0000
V_fixture = 0.000
V_fixture_min = 0.000
V_fixture_max = 0.000
| time   V(typ)   V(min)   V(max)
0s        251.6pV    597.4pV    205pV
1.131ns   1.53mV     698.7uV    -33.74mV
1.273ns   -1.703mV   945.8uV    -2.746mV
1.556ns   -13.33mV   1.247mV    164.4mV
1.838ns   -24.58mV   1.327mV    409.7mV
2.121ns   -16.63mV   1.2mV      502.9mV
2.404ns   7.902mV    652.7uV    529.6mV
3.394ns   196.4mV    -4.251mV   537.4mV
4.242ns   251.1mV    -10.11mV   537.1mV
14ns      258.1mV    90.6mV     537.1mV
[Rising Waveform]
R_fixture = 50.0000
V_fixture = 3.1000
V_fixture_min = 2.7900
V_fixture_max = 3.4100
| time   V(typ)   V(min)   V(max)
0s        2.684V     2.641V     2.513V
848.5ps   2.679V     2.642V     2.515V
989.9ps   2.674V     2.642V     2.655V
1.273ns   2.669V     2.641V     3.081V
1.414ns   2.682V     2.64V      3.219V
1.838ns   2.831V     2.637V     3.38V
2.546ns   3.024V     2.633V     3.407V
3.253ns   3.082V     2.64V      3.41V
7.071ns   3.1V       2.775V     3.41V
14ns      3.1V       2.789V     3.41V
[Falling Waveform]
R_fixture = 50.0000
V_fixture = 0.000
V_fixture_min = 0.000
V_fixture_max = 0.000
| time   V(typ)   V(min)   V(max)
0s        258.1mV    90.99mV    537.1mV
606.1ps   269.3mV    92.22mV    528.5mV
707.1ps   269.8mV    93.4mV     452.3mV
1.01ns    237.2mV    96.19mV    125.6mV
1.212ns   167.6mV    97.08mV    45.67mV
1.414ns   116.4mV    96.79mV    21.06mV
1.919ns   31.26mV    84.16mV    3.812mV
2.828ns   6.601mV    48.45mV    40.9uV
4.848ns   122.7uV    9.062mV    4.306uV
10ns      54.22nV    434.7uV    1.503uV
[Falling Waveform]
R_fixture = 50.0000
V_fixture = 3.1000
V_fixture_min = 2.7900
V_fixture_max = 3.4100
| time   V(typ)   V(min)   V(max)
0s        3.1V       2.79V      3.41V
909.1ps   3.114V     2.788V     3.426V
1.111ns   3.135V     2.788V     3.237V
1.515ns   3.118V     2.794V     2.721V
1.717ns   3.075V     2.8V       2.597V
2.02ns    2.984V     2.805V     2.53V
2.626ns   2.777V     2.808V     2.511V
3.333ns   2.696V     2.802V     2.512V
6.869ns   2.684V     2.668V     2.513V
10ns      2.684V     2.642V     2.513V
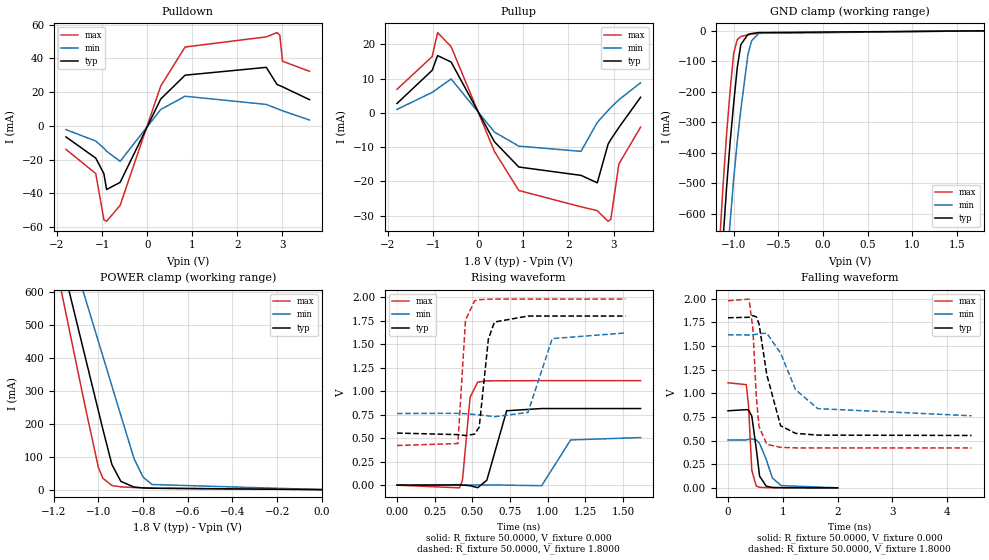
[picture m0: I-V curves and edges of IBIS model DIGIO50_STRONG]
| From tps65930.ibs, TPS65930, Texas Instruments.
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|   Model DIGIO50_STRONG
[Model]   DIGIO50_STRONG
Model_type   I/O
Polarity   Non-Inverting
Enable   Active-Low
Vinl =   0.6900V
Vinh =   1.0500V
Vmeas =   0.9000V
Cref =  30.0000pF
Rref = 100.0000M
Vref =  0.000V
C_comp   0.7478pF   0.7771pF   0.7160pF
[Temperature Range]   25.0000   0.1250k   -40.0000
[Pullup Reference]   1.8000V   1.6200V   1.9800V
[Pulldown Reference]   0.000V   0.000V   0.000V
[POWER Clamp Reference]   1.8000V   1.6200V   1.9800V
[GND Clamp Reference]   0.000V   0.000V   0.000V
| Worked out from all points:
|   slope of the pulldown table from 0 to 0.27 V, typ, clamps not added: 18.5 ohm
|   slope of the pullup table from 0 to 0.27 V, typ, clamps not added: 41.2 ohm
|   GND clamp passes 1 mA (typ) near -0.52 V on its own axis
|   POWER clamp passes 1 mA (typ) near -0.54 V on its own axis
|   rising waveform, R_fixture 50.0000, V_fixture 0.000: 20-80 % time 54.7ps typ, 78.9ps min, 35.2ps max; typ from 0 V to 0.816 V
|   rising waveform, R_fixture 50.0000, V_fixture 1.8000: 20-80 % time 44.1ps typ, 81.3ps min, 28.5ps max; typ from 0.554 V to 1.8 V
|   falling waveform, R_fixture 50.0000, V_fixture 0.000: 20-80 % time 92.6ps typ, 181ps min, 58.4ps max; typ from 0.816 V to 0 V
|   falling waveform, R_fixture 50.0000, V_fixture 1.8000: 20-80 % time 212ps typ, 440ps min, 93.4ps max; typ from 1.8 V to 0.554 V
[Pulldown]
| voltage   I(typ)   I(min)   I(max)
-1.8V     -6.538mA   -2.225mA   -13.94mA
-1.14V    -19.12mA   -8.983mA   -28.28mA
-960mV    -28.34mA   -13.25mA   -55.64mA
-900mV    -37.7mA    -15.06mA   -56.54mA
-600mV    -33.48mA   -21mA      -47.09mA
300mV     15.91mA    9.708mA    23.59mA
840mV     30.03mA    17.56mA    46.73mA
2.64V     34.68mA    12.71mA    52.74mA
2.88V     24.47mA    10.19mA    55.29mA
2.94V     23.84mA    9.558mA    53.81mA
3V        23.15mA    8.937mA    38.29mA
3.6V      15.52mA    3.451mA    32.34mA
[Pullup]
| voltage   I(typ)   I(min)   I(max)
-1.8V     2.734mA    1.001mA    6.864mA
-1.02V    12.41mA    5.965mA    16.41mA
-900mV    16.71mA    7.093mA    23.42mA
-600mV    14.82mA    9.896mA    19.3mA
360mV     -8.437mA   -5.603mA   -11.25mA
900mV     -15.81mA   -9.712mA   -22.66mA
2.28V     -18.25mA   -11.24mA   -27.42mA
2.64V     -20.42mA   -2.805mA   -28.54mA
2.88V     -9.156mA   691.5uA    -31.65mA
2.94V     -7.782mA   1.518mA    -31.11mA
3.12V     -4.259mA   3.835mA    -14.91mA
3.6V      4.535mA    8.759mA    -4.187mA
[GND_clamp]
| voltage   I(typ)   I(min)   I(max)
-1.8V     -3.632A    -3.389A    -3.871A
-1.16V    -861.2mA   -1.064A    -707.3mA
-1.12V    -688mA     -918.7mA   -510.6mA
-1.08V    -515.2mA   -773.3mA   -340.9mA
-1.04V    -365.1mA   -627.9mA   -196mA
-1V       -237.8mA   -484.7mA   -73.6mA
-960mV    -120.7mA   -363mA     -28.7mA
-920mV    -44.96mA   -258.1mA   -18.58mA
-840mV    -11.78mA   -76.65mA   -13.15mA
-800mV    -8.863mA   -33.19mA   -11.19mA
-720mV    -5.756mA   -8.338mA   -7.497mA
1.8V      136.1pA    711.8nA    181.7pA
[POWER_clamp]
| voltage   I(typ)   I(min)   I(max)
-1.8V     2.459A     2.236A     2.691A
-1.16V    681.8mA    806.5mA    582mA
-1.12V    570.8mA    717.1mA    450.5mA
-1.06V    404.3mA    583mA      253.4mA
-1V       238mA      449mA      66mA
-980mV    182.5mA    404.3mA    34.32mA
-940mV    76.38mA    315mA      12.57mA
-900mV    25.1mA     225.7mA    8.233mA
-840mV    7.491mA    92.62mA    6.278mA
-800mV    5.165mA    37.76mA    5.344mA
-760mV    4.119mA    15.48mA    4.467mA
0V        389.6pA    2.073nA    2.781nA
[Ramp]
| variable   typ   min   max
dV/dt_r   0.4894/56.4862p   0.3038/88.4186p   0.6674/36.6604p
dV/dt_f   0.7469/0.2097n   0.4994/0.4136n   0.9347/0.1044n
R_load = 50.0000
[Rising Waveform]
R_fixture = 50.0000
V_fixture = 0.000
V_fixture_min = 0.000
V_fixture_max = 0.000
| time   V(typ)   V(min)   V(max)
0s        10.39nV    251.3nV    19.71nV
414.1ps   2.707mV    669.8uV    -28.84mV
434.3ps   1.045mV    775.2uV    52.58mV
484.8ps   -5.299mV   971.8uV    933.5mV
535.4ps   -27.56mV   1.331mV    1.097V
596ps     52.46mV    1.973mV    1.11V
727.3ps   791.7mV    198.1uV    1.111V
959.6ps   815.6mV    -6.061mV   1.112V
1.152ns   815.6mV    481.2mV    1.112V
1.616ns   815.6mV    506.4mV    1.112V
[Rising Waveform]
R_fixture = 50.0000
V_fixture = 1.8000
V_fixture_min = 1.6200
V_fixture_max = 1.9800
| time   V(typ)   V(min)   V(max)
0s        554.4mV    762.7mV    422.1mV
404ps     537.7mV    764.9mV    443.1mV
454.5ps   528.1mV    760.4mV    1.758V
515.2ps   543.4mV    752mV      1.963V
545.5ps   618mV      747.7mV    1.974V
606.1ps   1.554V     737.2mV    1.979V
646.5ps   1.736V     728.6mV    1.98V
868.7ps   1.8V       773.9mV    1.98V
1.03ns    1.8V       1.56V      1.98V
1.515ns   1.8V       1.62V      1.98V
[Falling Waveform]
R_fixture = 50.0000
V_fixture = 0.000
V_fixture_min = 0.000
V_fixture_max = 0.000
| time   V(typ)   V(min)   V(max)
0s        815.6mV    506.4mV    1.112V
333.3ps   827.5mV    507.1mV    1.092V
373.7ps   823.6mV    513.6mV    876.4mV
434.3ps   758.7mV    517.7mV    184.7mV
515.2ps   415.7mV    507.4mV    18.86mV
575.8ps   123.9mV    470.2mV    5.644mV
697ps     18.19mV    302.4mV    2.401mV
808.1ps   4.483mV    105.2mV    1.228mV
969.7ps   2.154mV    24.08mV    456.4uV
2ns       26.21uV    393.7uV    1.165uV
[Falling Waveform]
R_fixture = 50.0000
V_fixture = 1.8000
V_fixture_min = 1.6200
V_fixture_max = 1.9800
| time   V(typ)   V(min)   V(max)
0s        1.8V       1.62V      1.98V
383.8ps   1.805V     1.618V     1.997V
454.5ps   1.822V     1.621V     1.681V
515.2ps   1.81V      1.624V     975.9mV
565.7ps   1.736V     1.631V     648.6mV
707.1ps   1.198V     1.637V     461.3mV
959.6ps   656.8mV    1.425V     428.4mV
1.232ns   576.9mV    1.039V     423.1mV
1.636ns   558mV      838.5mV    422.2mV
4.444ns   554.4mV    762.7mV    422.1mV
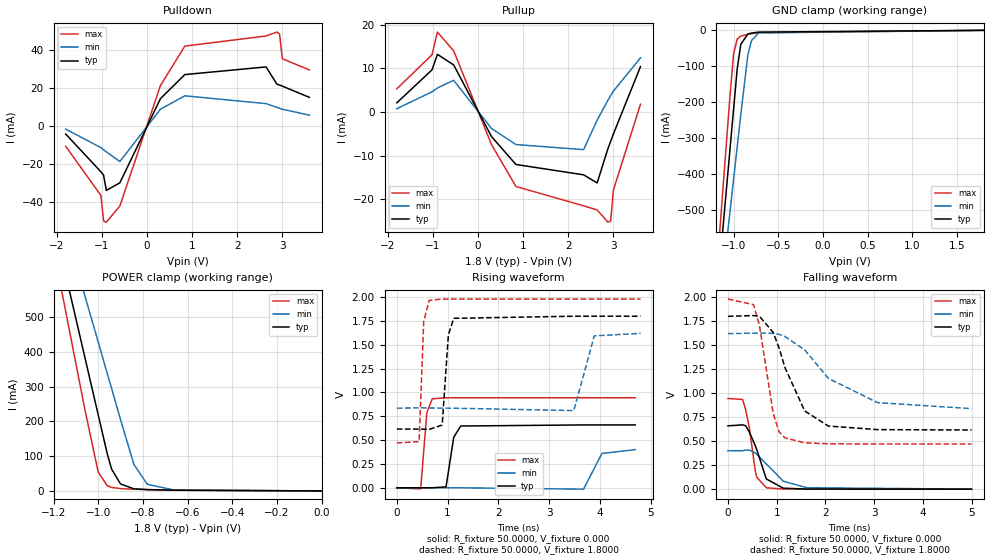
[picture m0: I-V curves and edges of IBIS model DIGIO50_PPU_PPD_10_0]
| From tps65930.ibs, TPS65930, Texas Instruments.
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|   Model DIGIO50_PPU_PPD_10_0
[Model]   DIGIO50_PPU_PPD_10_0
Model_type   I/O
Polarity   Non-Inverting
Enable   Active-Low
Vinl =   0.6900V
Vinh =   1.0500V
Vmeas =   0.9000V
Cref =  30.0000pF
Rref = 100.0000M
Vref =  0.000V
|C_comp   1.4494pF   1.4784pF   1.3799pF
C_comp   30fF   30fF   30fF
[Temperature Range]   25.0000   0.1250k   -40.0000
[Pullup Reference]   1.8000V   1.6200V   1.9800V
[Pulldown Reference]   0.000V   0.000V   0.000V
[POWER Clamp Reference]   1.8000V   1.6200V   1.9800V
[GND Clamp Reference]   0.000V   0.000V   0.000V
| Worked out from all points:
|   slope of the pulldown table from 0 to 0.27 V, typ, clamps not added: 20.7 ohm
|   slope of the pullup table from 0 to 0.27 V, typ, clamps not added: 52.8 ohm
|   GND clamp passes 1 mA (typ) near -0.53 V on its own axis
|   POWER clamp passes 1 mA (typ) near -0.56 V on its own axis
|   rising waveform, R_fixture 50.0000, V_fixture 0.000: 20-80 % time 96.7ps typ, 163ps min, 63.7ps max; typ from 0 V to 0.66 V
|   rising waveform, R_fixture 50.0000, V_fixture 1.8000: 20-80 % time 80.9ps typ, 148ps min, 50.7ps max; typ from 0.616 V to 1.8 V
|   falling waveform, R_fixture 50.0000, V_fixture 0.000: 20-80 % time 260ps typ, 463ps min, 167ps max; typ from 0.66 V to 0 V
|   falling waveform, R_fixture 50.0000, V_fixture 1.8000: 20-80 % time 535ps typ, 971ps min, 280ps max; typ from 1.8 V to 0.616 V
[Pulldown]
| voltage   I(typ)   I(min)   I(max)
-1.8V     -4.367mA   -1.778mA   -10.81mA
-1.02V    -24.17mA   -11.51mA   -36.61mA
-960mV    -26.02mA   -12.66mA   -50.05mA
-900mV    -33.97mA   -13.72mA   -50.66mA
-600mV    -29.98mA   -18.8mA    -42.17mA
300mV     14.24mA    8.688mA    21.12mA
840mV     26.87mA    15.71mA    41.82mA
2.64V     30.88mA    11.61mA    47.13mA
2.88V     21.84mA    9.642mA    49.18mA
2.94V     21.35mA    9.152mA    48.15mA
3V        20.81mA    8.67mA     35.2mA
3.6V      14.89mA    5.551mA    29.32mA
[Pullup]
| voltage   I(typ)   I(min)   I(max)
-1.8V     2.116mA    778.5uA    5.325mA
-1.02V    9.679mA    4.64mA     13.14mA
-900mV    13.23mA    5.525mA    18.33mA
-540mV    10.81mA    7.289mA    14.04mA
300mV     -5.629mA   -3.764mA   -7.458mA
840mV     -12mA      -7.434mA   -17.04mA
2.34V     -14.37mA   -8.6mA     -21.47mA
2.64V     -16.23mA   -1.853mA   -22.42mA
2.88V     -8.337mA   2.739mA    -25.22mA
2.94V     -6.705mA   3.796mA    -24.95mA
3V        -5.003mA   4.808mA    -17.88mA
3.6V      10.42mA    12.43mA    1.793mA
[GND_clamp]
| voltage   I(typ)   I(min)   I(max)
-1.8V     -2.446A    -2.203A    -2.695A
-1.16V    -664.4mA   -773.1mA   -576.5mA
-1.12V    -553mA     -683.6mA   -444.4mA
-1.08V    -441.6mA   -594.1mA   -312.5mA
-1.04V    -330.2mA   -504.6mA   -180.9mA
-1V       -219mA     -415.1mA   -65.11mA
-960mV    -108.2mA   -325.6mA   -24.81mA
-920mV    -39.27mA   -236.2mA   -15.98mA
-840mV    -10.15mA   -67.48mA   -11.31mA
-800mV    -7.638mA   -28.88mA   -9.626mA
-720mV    -4.97mA    -7.224mA   -6.465mA
1.8V      135.9pA    901.2nA    181.6pA
[POWER_clamp]
| voltage   I(typ)   I(min)   I(max)
-1.8V     2.436A     2.211A     2.668A
-1.16V    661.7mA    784.8mA    563.5mA
-1.12V    550.9mA    695.6mA    432.1mA
-1.06V    384.8mA    561.8mA    235.3mA
-1V       218.7mA    428.1mA    54.32mA
-960mV    108.1mA    338.9mA    15.32mA
-940mV    62.71mA    294.4mA    10.02mA
-900mV    20.03mA    205.2mA    6.59mA
-840mV    5.984mA    75.8mA     5.047mA
-780mV    3.686mA    19.04mA    3.959mA
-660mV    2.016mA    2.553mA    2.053mA
0V        360.2pA    1.961nA    2.555nA
[Ramp]
| variable   typ   min   max
dV/dt_r   0.3958/0.1489n   0.2403/0.1747n   0.5668/0.5156n
dV/dt_f   0.7102/0.5330n   0.4709/1.0196n   0.9057/0.2904n
R_load = 50.0000
[Rising Waveform]
R_fixture = 50.0000
V_fixture = 0.000
V_fixture_min = 0.000
V_fixture_max = 0.000
| time   V(typ)   V(min)   V(max)
0s        11.15nV    278.2nV    20.93nV
469.7ps   154.4uV    53.64uV    -11.34mV
590.9ps   197.5uV    44.33uV    786.2mV
697ps     433.7uV    38.36uV    933.2mV
969.7ps   9.316mV    26.45uV    944.5mV
1.121ns   530.3mV    22.66uV    944.6mV
1.258ns   648.2mV    19.55uV    944.6mV
3.677ns   659.6mV    -14.36mV   944.7mV
4.04ns    659.6mV    360.7mV    944.7mV
4.697ns   659.6mV    400.4mV    944.7mV
[Rising Waveform]
R_fixture = 50.0000
V_fixture = 1.8000
V_fixture_min = 1.6200
V_fixture_max = 1.9800
| time   V(typ)   V(min)   V(max)
0s        616.3mV    835.2mV    470.5mV
439.4ps   616.1mV    839mV      484.9mV
530.3ps   614.6mV    838.2mV    1.746V
636.4ps   612.5mV    837.4mV    1.966V
893.9ps   658.8mV    835.9mV    1.98V
1.015ns   1.604V     835.4mV    1.98V
1.121ns   1.778V     834.9mV    1.98V
3.485ns   1.8V       809.8mV    1.98V
3.889ns   1.8V       1.594V     1.98V
4.798ns   1.8V       1.62V      1.98V
[Falling Waveform]
R_fixture = 50.0000
V_fixture = 0.000
V_fixture_min = 0.000
V_fixture_max = 0.000
| time   V(typ)   V(min)   V(max)
0s        659.6mV    400.4mV    944.7mV
303ps     669.9mV    401mV      933.8mV
363.6ps   660.8mV    407.3mV    827.9mV
439.4ps   595.4mV    407.5mV    640.5mV
560.6ps   453.5mV    376.8mV    193.8mV
590.9ps   414mV      363.8mV    125.2mV
787.9ps   106.2mV    262.7mV    14.25mV
1.136ns   10.32mV    83.3mV     1.304mV
1.616ns   1.208mV    15.17mV    301uV
5ns       815nV      28.54uV    191.6nV
[Falling Waveform]
R_fixture = 50.0000
V_fixture = 1.8000
V_fixture_min = 1.6200
V_fixture_max = 1.9800
| time   V(typ)   V(min)   V(max)
0s        1.8V       1.62V      1.98V
525.3ps   1.808V     1.625V     1.922V
646.5ps   1.801V     1.626V     1.708V
929.3ps   1.633V     1.623V     788mV
1.051ns   1.469V     1.612V     596.5mV
1.172ns   1.264V     1.589V     533.4mV
1.576ns   814.3mV    1.45V      482.9mV
2.061ns   657.5mV    1.154V     472.6mV
3.071ns   620.3mV    901.3mV    470.6mV
5ns       616.3mV    838.8mV    470.5mV
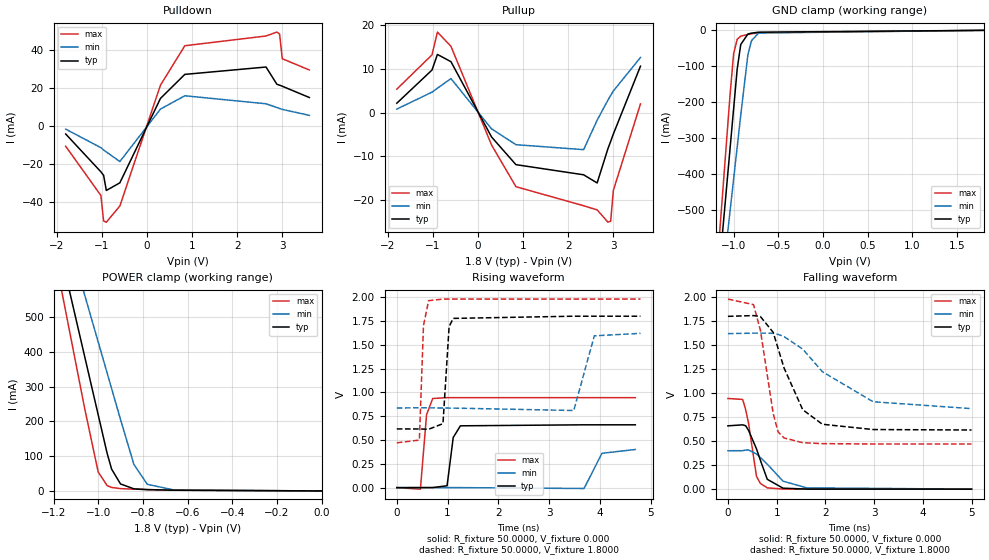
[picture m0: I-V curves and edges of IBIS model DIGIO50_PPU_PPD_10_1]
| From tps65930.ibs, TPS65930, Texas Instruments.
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|   Model DIGIO50_PPU_PPD_10_1
[Model]   DIGIO50_PPU_PPD_10_1
Model_type   I/O
Polarity   Non-Inverting
Enable   Active-Low
Vinl =   0.6900V
Vinh =   1.0500V
Vmeas =   0.9000V
Cref =  30.0000pF
Rref = 100.0000M
Vref =  0.000V
|C_comp   1.4494pF   1.4784pF   1.3799pF
C_comp   30fF   30fF   30fF
[Temperature Range]   25.0000   0.1250k   -40.0000
[Pullup Reference]   1.8000V   1.6200V   1.9800V
[Pulldown Reference]   0.000V   0.000V   0.000V
[POWER Clamp Reference]   1.8000V   1.6200V   1.9800V
[GND Clamp Reference]   0.000V   0.000V   0.000V
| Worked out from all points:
|   slope of the pulldown table from 0 to 0.27 V, typ, clamps not added: 20.7 ohm
|   slope of the pullup table from 0 to 0.27 V, typ, clamps not added: 53.2 ohm
|   GND clamp passes 1 mA (typ) near -0.52 V on its own axis
|   POWER clamp passes 1 mA (typ) near -0.56 V on its own axis
|   rising waveform, R_fixture 50.0000, V_fixture 0.000: 20-80 % time 93.4ps typ, 168ps min, 64.4ps max; typ from 0 V to 0.66 V
|   rising waveform, R_fixture 50.0000, V_fixture 1.8000: 20-80 % time 72ps typ, 148ps min, 51ps max; typ from 0.616 V to 1.8 V
|   falling waveform, R_fixture 50.0000, V_fixture 0.000: 20-80 % time 276ps typ, 458ps min, 169ps max; typ from 0.66 V to 0 V
|   falling waveform, R_fixture 50.0000, V_fixture 1.8000: 20-80 % time 512ps typ, 1.01ns min, 277ps max; typ from 1.8 V to 0.616 V
[Pulldown]
| voltage   I(typ)   I(min)   I(max)
-1.8V     -4.238mA   -1.671mA   -10.66mA
-1.02V    -24.04mA   -11.4mA    -36.45mA
-960mV    -25.89mA   -12.55mA   -49.83mA
-900mV    -33.8mA    -13.62mA   -50.43mA
-600mV    -29.8mA    -18.66mA   -41.94mA
300mV     14.42mA    8.823mA    21.35mA
840mV     27.01mA    15.8mA     42.02mA
2.64V     30.87mA    11.61mA    47.12mA
2.88V     21.84mA    9.641mA    49.17mA
2.94V     21.35mA    9.152mA    48.15mA
3V        20.81mA    8.669mA    35.2mA
3.6V      14.89mA    5.537mA    29.32mA
[Pullup]
| voltage   I(typ)   I(min)   I(max)
-1.8V     2.116mA    777.9uA    5.324mA
-1.02V    9.678mA    4.639mA    13.14mA
-900mV    13.23mA    5.524mA    18.32mA
-600mV    11.58mA    7.731mA    15.08mA
300mV     -5.585mA   -3.727mA   -7.407mA
840mV     -11.88mA   -7.331mA   -16.9mA
2.34V     -14.19mA   -8.465mA   -21.24mA
2.64V     -16.05mA   -1.747mA   -22.19mA
2.88V     -8.208mA   2.845mA    -24.99mA
2.94V     -6.576mA   3.903mA    -24.73mA
3V        -4.873mA   4.914mA    -17.72mA
3.6V      10.55mA    12.54mA    1.948mA
[GND_clamp]
| voltage   I(typ)   I(min)   I(max)
-1.8V     -2.446A    -2.203A    -2.695A
-1.16V    -664.5mA   -773.2mA   -576.7mA
-1.12V    -553.1mA   -683.7mA   -444.6mA
-1.08V    -441.7mA   -594.2mA   -312.6mA
-1.04V    -330.4mA   -504.7mA   -181mA
-1V       -219.2mA   -415.2mA   -65.29mA
-960mV    -108.3mA   -325.8mA   -25.04mA
-920mV    -39.43mA   -236.3mA   -16.21mA
-840mV    -10.33mA   -67.6mA    -11.54mA
-800mV    -7.816mA   -29.01mA   -9.856mA
-720mV    -5.148mA   -7.36mA    -6.694mA
1.8V      144.3pA    23.01uA    -30.42uA
[POWER_clamp]
| voltage   I(typ)   I(min)   I(max)
-1.8V     2.436A     2.211A     2.668A
-1.16V    661.7mA    784.8mA    563.5mA
-1.12V    550.9mA    695.6mA    432.1mA
-1.06V    384.8mA    561.9mA    235.3mA
-1V       218.7mA    428.1mA    54.32mA
-960mV    108.1mA    338.9mA    15.32mA
-940mV    62.71mA    294.4mA    10.02mA
-900mV    20.03mA    205.2mA    6.592mA
-840mV    5.986mA    75.8mA     5.049mA
-780mV    3.688mA    19.05mA    3.962mA
-660mV    2.019mA    2.556mA    2.058mA
0V        368.6pA    1.98nA     2.569nA
[Ramp]
| variable   typ   min   max
dV/dt_r   0.3958/0.1489n   0.2403/0.1747n   0.5668/0.5156n
dV/dt_f   0.7102/0.5330n   0.4709/1.0196n   0.9057/0.2904n
R_load = 50.0000
[Rising Waveform]
R_fixture = 50.0000
V_fixture = 0.000
V_fixture_min = 0.000
V_fixture_max = 0.000
| time   V(typ)   V(min)   V(max)
0s        11.15nV    278.2nV    20.93nV
464.6ps   154uV      54.62uV    -16.22mV
585.9ps   194.8uV    44.61uV    766.7mV
707.1ps   530.5uV    37.78uV    935.8mV
989.9ps   19.62mV    26.25uV    944.6mV
1.111ns   526.6mV    22.84uV    944.6mV
1.252ns   649mV      19.53uV    944.6mV
3.687ns   659.6mV    -9.229mV   944.7mV
4.04ns    659.6mV    360.7mV    944.7mV
4.697ns   659.6mV    400.4mV    944.7mV
[Rising Waveform]
R_fixture = 50.0000
V_fixture = 1.8000
V_fixture_min = 1.6200
V_fixture_max = 1.9800
| time   V(typ)   V(min)   V(max)
0s        616.3mV    835.2mV    470.5mV
444.4ps   616mV      839mV      499.3mV
525.3ps   614.6mV    838.3mV    1.703V
626.3ps   612.7mV    837.5mV    1.963V
909.1ps   671.9mV    835.9mV    1.98V
1.03ns    1.692V     835.3mV    1.98V
1.111ns   1.777V     835mV      1.98V
3.485ns   1.8V       809.8mV    1.98V
3.889ns   1.8V       1.594V     1.98V
4.798ns   1.8V       1.62V      1.98V
[Falling Waveform]
R_fixture = 50.0000
V_fixture = 0.000
V_fixture_min = 0.000
V_fixture_max = 0.000
| time   V(typ)   V(min)   V(max)
0s        659.6mV    400.4mV    944.7mV
303ps     669.9mV    401mV      934.4mV
363.6ps   660.8mV    407.3mV    828.9mV
424.2ps   611.2mV    408mV      683.7mV
585.9ps   420.4mV    366.3mV    133.9mV
666.7ps   300.1mV    329.1mV    59.24mV
808.1ps   102.5mV    260.4mV    13.46mV
1.131ns   10.31mV    83.48mV    1.305mV
1.616ns   1.161mV    13.79mV    289.9uV
5ns       815nV      28.54uV    191.8nV
[Falling Waveform]
R_fixture = 50.0000
V_fixture = 1.8000
V_fixture_min = 1.6200
V_fixture_max = 1.9800
| time   V(typ)   V(min)   V(max)
0s        1.8V       1.62V      1.98V
525.3ps   1.808V     1.625V     1.922V
666.7ps   1.798V     1.626V     1.656V
929.3ps   1.633V     1.623V     786.9mV
1.03ns    1.465V     1.612V     596.1mV
1.152ns   1.262V     1.589V     533.3mV
1.535ns   827.4mV    1.459V     484mV
1.939ns   676mV      1.223V     474mV
2.98ns    621mV      910.4mV    470.6mV
5ns       616.3mV    838.8mV    470.5mV
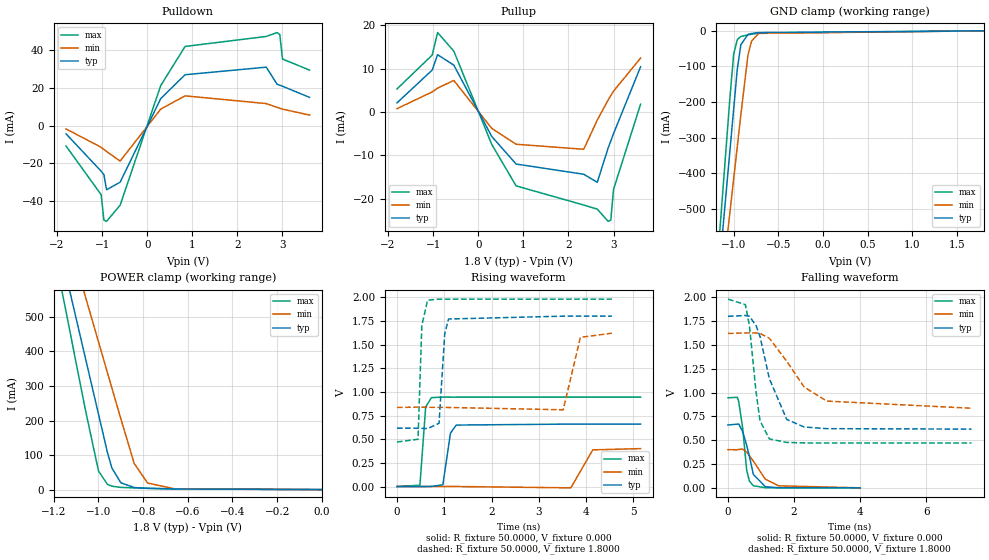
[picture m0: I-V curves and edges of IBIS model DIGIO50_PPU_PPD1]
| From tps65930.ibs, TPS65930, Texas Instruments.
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|   Model DIGIO50_PPU_PPD1
[Model]   DIGIO50_PPU_PPD1
Model_type   I/O
Polarity   Non-Inverting
Enable   Active-Low
Vinl =   0.6900V
Vinh =   1.0500V
Vmeas =   0.9000V
Cref =  10.0000pF
Rref = 100.0000M
Vref =  0.000V
C_comp   30fF   30fF   30fF
[Temperature Range]   25.0000   0.1250k   -40.0000
[Pullup Reference]   1.8000V   1.6200V   1.9800V
[Pulldown Reference]   0.000V   0.000V   0.000V
[POWER Clamp Reference]   1.8000V   1.6200V   1.9800V
[GND Clamp Reference]   0.000V   0.000V   0.000V
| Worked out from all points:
|   slope of the pulldown table from 0 to 0.27 V, typ, clamps not added: 20.7 ohm
|   slope of the pullup table from 0 to 0.27 V, typ, clamps not added: 52.8 ohm
|   GND clamp passes 1 mA (typ) near -0.53 V on its own axis
|   POWER clamp passes 1 mA (typ) near -0.57 V on its own axis
|   rising waveform, R_fixture 50.0000, V_fixture 0.000: 20-80 % time 101ps typ, 163ps min, 71ps max; typ from 0 V to 0.66 V
|   rising waveform, R_fixture 50.0000, V_fixture 1.8000: 20-80 % time 86ps typ, 144ps min, 56.1ps max; typ from 0.616 V to 1.8 V
|   falling waveform, R_fixture 50.0000, V_fixture 0.000: 20-80 % time 278ps typ, 478ps min, 170ps max; typ from 0.66 V to 0 V
|   falling waveform, R_fixture 50.0000, V_fixture 1.8000: 20-80 % time 535ps typ, 981ps min, 280ps max; typ from 1.8 V to 0.616 V
[Pulldown]
| voltage   I(typ)   I(min)   I(max)
-1.8V     -4.357mA   -1.77mA    -10.8mA
-1.02V    -24.16mA   -11.5mA    -36.59mA
-960mV    -26.01mA   -12.65mA   -50.03mA
-900mV    -33.95mA   -13.72mA   -50.64mA
-600mV    -29.96mA   -18.79mA   -42.15mA
300mV     14.26mA    8.698mA    21.14mA
840mV     26.88mA    15.71mA    41.84mA
2.64V     30.88mA    11.61mA    47.13mA
2.88V     21.84mA    9.642mA    49.18mA
2.94V     21.35mA    9.152mA    48.15mA
3V        20.81mA    8.67mA     35.19mA
3.6V      14.89mA    5.551mA    29.32mA
[Pullup]
| voltage   I(typ)   I(min)   I(max)
-1.8V     2.116mA    778.5uA    5.325mA
-1.02V    9.679mA    4.64mA     13.14mA
-900mV    13.23mA    5.525mA    18.33mA
-540mV    10.81mA    7.289mA    14.04mA
300mV     -5.626mA   -3.762mA   -7.453mA
840mV     -11.99mA   -7.427mA   -17.03mA
2.34V     -14.35mA   -8.59mA    -21.45mA
2.64V     -16.21mA   -1.845mA   -22.4mA
2.88V     -8.327mA   2.747mA    -25.2mA
2.94V     -6.695mA   3.804mA    -24.93mA
3V        -4.993mA   4.815mA    -17.87mA
3.6V      10.43mA    12.44mA    1.808mA
[GND_clamp]
| voltage   I(typ)   I(min)   I(max)
-1.8V     -2.446A    -2.203A    -2.695A
-1.16V    -664.4mA   -773.1mA   -576.5mA
-1.12V    -552.9mA   -683.6mA   -444.4mA
-1.08V    -441.5mA   -594.1mA   -312.4mA
-1.04V    -330.2mA   -504.6mA   -180.8mA
-1V       -219mA     -415.1mA   -65.07mA
-960mV    -108.1mA   -325.6mA   -24.77mA
-920mV    -39.23mA   -236.2mA   -15.94mA
-840mV    -10.12mA   -67.46mA   -11.28mA
-800mV    -7.613mA   -28.86mA   -9.606mA
-720mV    -4.954mA   -7.206mA   -6.454mA
1.8V      144.4pA    1.988uA    -2.619uA
[POWER_clamp]
| voltage   I(typ)   I(min)   I(max)
-1.8V     2.435A     2.211A     2.668A
-1.16V    661.6mA    784.7mA    563.4mA
-1.12V    550.8mA    695.5mA    432mA
-1.06V    384.7mA    561.8mA    235.2mA
-1V       218.6mA    428mA      54.19mA
-960mV    108mA      338.9mA    15.18mA
-940mV    62.6mA     294.3mA    9.881mA
-900mV    19.91mA    205.2mA    6.453mA
-840mV    5.873mA    75.72mA    4.919mA
-780mV    3.583mA    18.96mA    3.841mA
-660mV    1.93mA     2.479mA    1.957mA
0V        368.7pA    1.981nA    2.569nA
[Ramp]
| variable   typ   min   max
dV/dt_r   0.3958/0.1489n   0.2403/0.1745n   0.5668/0.5156n
dV/dt_f   0.7102/0.5329n   0.4708/1.0194n   0.9057/0.2903n
R_load = 50.0000
[Rising Waveform]
R_fixture = 50.0000
V_fixture = 0.000
V_fixture_min = 0.000
V_fixture_max = 0.000
| time   V(typ)   V(min)   V(max)
0s        11.15nV    277.6nV    20.93nV
484.8ps   157.4uV    52.86uV    13.34mV
606.1ps   225.8uV    43.4uV     839.2mV
727.3ps   1.084mV    36.73uV    939.3mV
969.7ps   18.1mV     26.86uV    944.7mV
1.131ns   564mV      22.82uV    944.6mV
1.252ns   649.1mV    19.89uV    944.6mV
3.677ns   659.6mV    -14.36mV   944.7mV
4.141ns   659.6mV    387.1mV    944.7mV
5.152ns   659.6mV    400.4mV    944.7mV
[Rising Waveform]
R_fixture = 50.0000
V_fixture = 1.8000
V_fixture_min = 1.6200
V_fixture_max = 1.9800
| time   V(typ)   V(min)   V(max)
0s        616.3mV    835.2mV    470.5mV
444.4ps   616mV      839mV      499.1mV
525.3ps   614.6mV    838.3mV    1.703V
646.5ps   611.7mV    837.4mV    1.969V
888.9ps   668.4mV    836mV      1.98V
1.01ns    1.616V     835.4mV    1.98V
1.091ns   1.77V      835.1mV    1.98V
3.515ns   1.8V       810.5mV    1.98V
3.879ns   1.8V       1.576V     1.98V
4.546ns   1.8V       1.62V      1.98V
[Falling Waveform]
R_fixture = 50.0000
V_fixture = 0.000
V_fixture_min = 0.000
V_fixture_max = 0.000
| time   V(typ)   V(min)   V(max)
0s        659.6mV    400.4mV    944.7mV
282.8ps   668.3mV    399.9mV    950.2mV
323.2ps   670mV      403.5mV    906.7mV
444.4ps   589.7mV    407.2mV    625.7mV
565.7ps   446.3mV    375mV      185.5mV
646.5ps   332.3mV    338.7mV    71.57mV
767.7ps   140.3mV    280.5mV    21.88mV
1.131ns   12.13mV    89.87mV    1.367mV
1.535ns   1.42mV     21.38mV    394.8uV
4ns       9.373uV    120.4uV    4.224uV
[Falling Waveform]
R_fixture = 50.0000
V_fixture = 1.8000
V_fixture_min = 1.6200
V_fixture_max = 1.9800
| time   V(typ)   V(min)   V(max)
0s        1.8V       1.62V      1.98V
525.3ps   1.808V     1.625V     1.922V
646.5ps   1.801V     1.626V     1.708V
848.5ps   1.703V     1.625V     1.006V
969.7ps   1.587V     1.621V     703.2mV
1.252ns   1.145V     1.569V     513.7mV
1.778ns   717.7mV    1.329V     476.7mV
2.303ns   638.7mV    1.058V     471.5mV
2.99ns    621.1mV    910.3mV    470.6mV
7.374ns   616.3mV    835.3mV    470.5mV
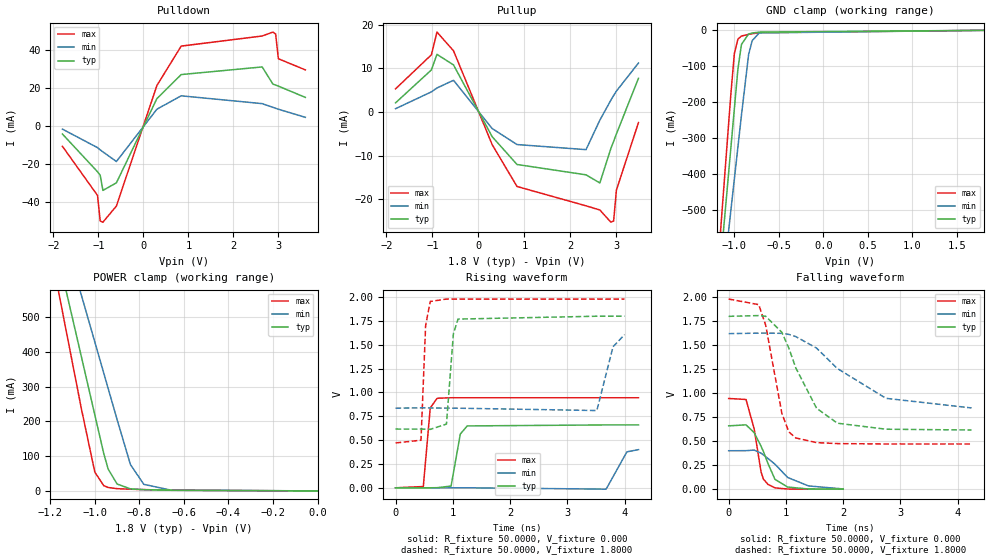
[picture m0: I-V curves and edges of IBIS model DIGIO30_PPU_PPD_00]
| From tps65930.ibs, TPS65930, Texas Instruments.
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|   Model DIGIO30_PPU_PPD_00
[Model]   DIGIO30_PPU_PPD_00
Model_type   I/O
Polarity   Non-Inverting
Enable   Active-Low
Vinl =   0.6900V
Vinh =   1.0500V
Vmeas =   0.9000V
Cref =  10.0000pF
Rref = 100.0000M
Vref =  0.000V
C_comp   1.4434pF   1.4724pF   1.3744pF
[Temperature Range]   25.0000   0.1250k   -40.0000
[Pullup Reference]   1.8000V   1.6200V   1.9800V
[Pulldown Reference]   0.000V   0.000V   0.000V
[POWER Clamp Reference]   1.8000V   1.6200V   1.9800V
[GND Clamp Reference]   0.000V   0.000V   0.000V
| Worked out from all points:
|   slope of the pulldown table from 0 to 0.27 V, typ, clamps not added: 20.7 ohm
|   slope of the pullup table from 0 to 0.27 V, typ, clamps not added: 52.8 ohm
|   GND clamp passes 1 mA (typ) near -0.53 V on its own axis
|   POWER clamp passes 1 mA (typ) near -0.57 V on its own axis
|   rising waveform, R_fixture 50.0000, V_fixture 0.000: 20-80 % time 101ps typ, 163ps min, 71ps max; typ from 0 V to 0.66 V
|   rising waveform, R_fixture 50.0000, V_fixture 1.8000: 20-80 % time 86ps typ, 141ps min, 56.1ps max; typ from 0.616 V to 1.8 V
|   falling waveform, R_fixture 50.0000, V_fixture 0.000: 20-80 % time 276ps typ, 453ps min, 167ps max; typ from 0.66 V to 0.001 V
|   falling waveform, R_fixture 50.0000, V_fixture 1.8000: 20-80 % time 535ps typ, 951ps min, 280ps max; typ from 1.8 V to 0.616 V
[Pulldown]
| voltage   I(typ)   I(min)   I(max)
-1.8V     -4.367mA   -1.778mA   -10.81mA
-1.02V    -24.17mA   -11.51mA   -36.61mA
-960mV    -26.02mA   -12.66mA   -50.05mA
-900mV    -33.97mA   -13.72mA   -50.66mA
-600mV    -29.98mA   -18.8mA    -42.17mA
300mV     14.24mA    8.688mA    21.12mA
840mV     26.87mA    15.71mA    41.82mA
2.64V     30.88mA    11.61mA    47.13mA
2.88V     21.84mA    9.642mA    49.18mA
2.94V     21.35mA    9.152mA    48.15mA
3V        20.81mA    8.67mA     35.19mA
3.6V      14.89mA    4.417mA    29.32mA
[Pullup]
| voltage   I(typ)   I(min)   I(max)
-1.8V     2.116mA    778.5uA    5.325mA
-1.02V    9.679mA    4.64mA     13.14mA
-900mV    13.23mA    5.525mA    18.33mA
-540mV    10.81mA    7.289mA    14.04mA
300mV     -5.629mA   -3.764mA   -7.458mA
840mV     -12mA      -7.434mA   -17.04mA
2.34V     -14.37mA   -8.6mA     -21.47mA
2.64V     -16.23mA   -1.853mA   -22.42mA
2.88V     -8.337mA   2.739mA    -25.22mA
2.94V     -6.705mA   3.796mA    -24.95mA
3V        -5.002mA   4.808mA    -17.88mA
3.48V     7.74mA     11.24mA    -2.391mA
[GND_clamp]
| voltage   I(typ)   I(min)   I(max)
-1.8V     -2.446A    -2.203A    -2.695A
-1.16V    -664.3mA   -773.1mA   -576.5mA
-1.12V    -552.9mA   -683.6mA   -444.3mA
-1.08V    -441.5mA   -594.1mA   -312.4mA
-1.04V    -330.2mA   -504.6mA   -180.8mA
-1V       -219mA     -415.1mA   -65.05mA
-960mV    -108.1mA   -325.6mA   -24.75mA
-920mV    -39.22mA   -236.2mA   -15.92mA
-840mV    -10.11mA   -67.45mA   -11.26mA
-800mV    -7.6mA     -28.85mA   -9.584mA
-720mV    -4.94mA    -7.196mA   -6.432mA
1.8V      135.9pA    791.5nA    181.6pA
[POWER_clamp]
| voltage   I(typ)   I(min)   I(max)
-1.8V     2.435A     2.211A     2.668A
-1.16V    661.6mA    784.7mA    563.4mA
-1.12V    550.8mA    695.5mA    432mA
-1.06V    384.7mA    561.8mA    235.2mA
-1V       218.6mA    428mA      54.19mA
-960mV    108mA      338.9mA    15.17mA
-940mV    62.6mA     294.3mA    9.874mA
-900mV    19.91mA    205.2mA    6.446mA
-840mV    5.868mA    75.72mA    4.913mA
-780mV    3.578mA    18.96mA    3.835mA
-660mV    1.926mA    2.476mA    1.951mA
0V        360.2pA    1.961nA    2.555nA
[Ramp]
| variable   typ   min   max
dV/dt_r   0.3958/99.8354p   0.1918/0.1185n   0.5668/70.3078p
dV/dt_f   0.7099/0.5292n   0.4613/0.9686n   0.9057/0.2768n
R_load = 50.0000
[Rising Waveform]
R_fixture = 50.0000
V_fixture = 0.000
V_fixture_min = 0.000
V_fixture_max = 0.000
| time   V(typ)   V(min)   V(max)
0s        11.15nV    276.9nV    20.93nV
484.8ps   157.4uV    52.86uV    13.34mV
606.1ps   225.8uV    43.4uV     839.2mV
727.3ps   1.084mV    36.73uV    939.4mV
969.7ps   18.1mV     26.86uV    944.7mV
1.131ns   564mV      22.82uV    944.6mV
1.252ns   649.1mV    19.89uV    944.6mV
3.677ns   659.6mV    -14.36mV   944.7mV
4.04ns    659.6mV    377.1mV    944.7mV
4.242ns   659.6mV    400.3mV    944.7mV
[Rising Waveform]
R_fixture = 50.0000
V_fixture = 1.8000
V_fixture_min = 1.6200
V_fixture_max = 1.9800
| time   V(typ)   V(min)   V(max)
0s        616.3mV    835.2mV    470.5mV
444.4ps   616mV      839mV      499.1mV
525.3ps   614.6mV    838.3mV    1.703V
606.1ps   613mV      837.6mV    1.955V
888.9ps   668.4mV    836mV      1.98V
1.01ns    1.616V     835.4mV    1.98V
1.091ns   1.77V      835.1mV    1.98V
3.515ns   1.8V       810.5mV    1.98V
3.798ns   1.8V       1.48V      1.98V
4ns       1.8V       1.607V     1.98V
[Falling Waveform]
R_fixture = 50.0000
V_fixture = 0.000
V_fixture_min = 0.000
V_fixture_max = 0.000
| time   V(typ)   V(min)   V(max)
0s        659.6mV    400.4mV    944.7mV
303ps     669.9mV    401mV      934.2mV
444.4ps   589.6mV    407.2mV    629.1mV
565.7ps   446.7mV    374.9mV    179.2mV
606.1ps   392.4mV    357.2mV    105mV
686.9ps   266.3mV    319.4mV    49.56mV
808.1ps   102.4mV    260.3mV    13.44mV
1.03ns    22.13mV    122mV      1.756mV
1.394ns   1.872mV    33.77mV    585.9uV
2ns       529.6uV    2.312mV    86.25uV
[Falling Waveform]
R_fixture = 50.0000
V_fixture = 1.8000
V_fixture_min = 1.6200
V_fixture_max = 1.9800
| time   V(typ)   V(min)   V(max)
0s        1.8V       1.62V      1.98V
525.3ps   1.808V     1.625V     1.922V
646.5ps   1.801V     1.626V     1.708V
929.3ps   1.633V     1.623V     787.5mV
1.051ns   1.469V     1.612V     596.3mV
1.172ns   1.263V     1.589V     533.4mV
1.535ns   842.6mV    1.469V     484.9mV
1.899ns   687mV      1.256V     474.6mV
2.748ns   624.4mV    945.9mV    470.8mV
4.242ns   616.2mV    846mV      470.5mV
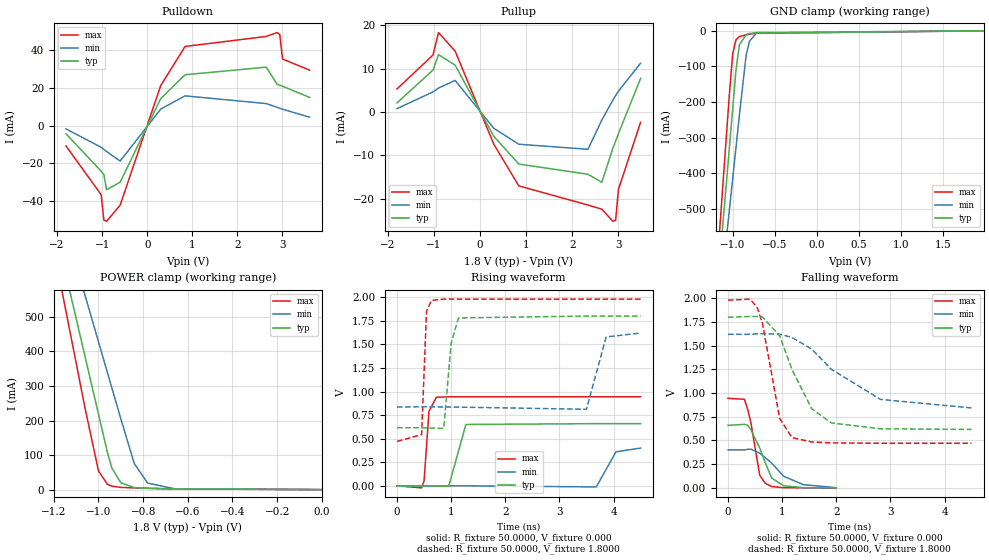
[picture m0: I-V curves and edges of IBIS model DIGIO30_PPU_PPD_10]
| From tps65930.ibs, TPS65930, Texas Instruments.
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|   Model DIGIO30_PPU_PPD_10
[Model]   DIGIO30_PPU_PPD_10
Model_type   I/O
Polarity   Non-Inverting
Enable   Active-Low
Vinl =   0.6900V
Vinh =   1.0500V
Vmeas =   0.9000V
Cref =  10.0000pF
Rref = 100.0000M
Vref =  0.000V
C_comp   1.4434pF   1.4724pF   1.3744pF
[Temperature Range]   25.0000   0.1250k   -40.0000
[Pullup Reference]   1.8000V   1.6200V   1.9800V
[Pulldown Reference]   0.000V   0.000V   0.000V
[POWER Clamp Reference]   1.8000V   1.6200V   1.9800V
[GND Clamp Reference]   0.000V   0.000V   0.000V
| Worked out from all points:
|   slope of the pulldown table from 0 to 0.27 V, typ, clamps not added: 20.7 ohm
|   slope of the pullup table from 0 to 0.27 V, typ, clamps not added: 52.8 ohm
|   GND clamp passes 1 mA (typ) near -0.53 V on its own axis
|   POWER clamp passes 1 mA (typ) near -0.57 V on its own axis
|   rising waveform, R_fixture 50.0000, V_fixture 0.000: 20-80 % time 105ps typ, 165ps min, 71.3ps max; typ from 0 V to 0.66 V
|   rising waveform, R_fixture 50.0000, V_fixture 1.8000: 20-80 % time 86.7ps typ, 144ps min, 63.1ps max; typ from 0.616 V to 1.8 V
|   falling waveform, R_fixture 50.0000, V_fixture 0.000: 20-80 % time 276ps typ, 453ps min, 169ps max; typ from 0.66 V to 0.001 V
|   falling waveform, R_fixture 50.0000, V_fixture 1.8000: 20-80 % time 535ps typ, 953ps min, 281ps max; typ from 1.8 V to 0.616 V
[Pulldown]
| voltage   I(typ)   I(min)   I(max)
-1.8V     -4.363mA   -1.774mA   -10.81mA
-1.02V    -24.16mA   -11.51mA   -36.6mA
-960mV    -26.02mA   -12.65mA   -50.04mA
-900mV    -33.96mA   -13.72mA   -50.65mA
-600mV    -29.97mA   -18.8mA    -42.16mA
300mV     14.25mA    8.692mA    21.13mA
840mV     26.87mA    15.71mA    41.83mA
2.64V     30.88mA    11.61mA    47.13mA
2.88V     21.84mA    9.642mA    49.18mA
2.94V     21.35mA    9.152mA    48.15mA
3V        20.81mA    8.67mA     35.19mA
3.6V      14.89mA    4.417mA    29.32mA
[Pullup]
| voltage   I(typ)   I(min)   I(max)
-1.8V     2.116mA    778.5uA    5.325mA
-1.02V    9.679mA    4.64mA     13.14mA
-900mV    13.23mA    5.525mA    18.33mA
-540mV    10.81mA    7.289mA    14.04mA
300mV     -5.627mA   -3.763mA   -7.456mA
840mV     -12mA      -7.431mA   -17.04mA
2.34V     -14.36mA   -8.596mA   -21.46mA
2.64V     -16.22mA   -1.849mA   -22.41mA
2.88V     -8.332mA   2.743mA    -25.21mA
2.94V     -6.7mA     3.8mA      -24.94mA
3V        -4.998mA   4.811mA    -17.87mA
3.48V     7.745mA    11.25mA    -2.384mA
[GND_clamp]
| voltage   I(typ)   I(min)   I(max)
-1.8V     -2.446A    -2.203A    -2.695A
-1.16V    -664.4mA   -773.1mA   -576.5mA
-1.12V    -552.9mA   -683.6mA   -444.4mA
-1.08V    -441.5mA   -594.1mA   -312.4mA
-1.04V    -330.2mA   -504.6mA   -180.8mA
-1V       -219mA     -415.1mA   -65.06mA
-960mV    -108.1mA   -325.6mA   -24.76mA
-920mV    -39.23mA   -236.2mA   -15.93mA
-840mV    -10.12mA   -67.45mA   -11.27mA
-800mV    -7.606mA   -28.85mA   -9.594mA
-720mV    -4.947mA   -7.2mA     -6.443mA
1.98V     0A         0A         0A
[POWER_clamp]
| voltage   I(typ)   I(min)   I(max)
-1.8V     2.435A     2.211A     2.668A
-1.16V    661.6mA    784.7mA    563.4mA
-1.12V    550.8mA    695.5mA    432mA
-1.06V    384.7mA    561.8mA    235.2mA
-1V       218.6mA    428mA      54.19mA
-960mV    108mA      338.9mA    15.17mA
-940mV    62.6mA     294.3mA    9.874mA
-900mV    19.91mA    205.2mA    6.446mA
-840mV    5.868mA    75.72mA    4.913mA
-780mV    3.578mA    18.96mA    3.835mA
-660mV    1.926mA    2.476mA    1.951mA
0V        368.7pA    1.981nA    2.569nA
[Ramp]
| variable   typ   min   max
dV/dt_r   0.3958/0.1041n   0.2404/0.1634n   0.5668/71.3020p
dV/dt_f   0.7101/0.5301n   0.4660/0.9887n   0.9057/0.2781n
R_load = 50.0000
[Rising Waveform]
R_fixture = 50.0000
V_fixture = 0.000
V_fixture_min = 0.000
V_fixture_max = 0.000
| time   V(typ)   V(min)   V(max)
0s        11.15nV    276.9nV    20.93nV
454.5ps   153.3uV    55.87uV    -21.33mV
500ps     160.7uV    51.35uV    51.4mV
590.9ps   211.6uV    44.33uV    789.6mV
727.3ps   905.2uV    36.64uV    939.3mV
954.5ps   -5.756mV   27.33uV    944.7mV
1.273ns   650.8mV    19.46uV    944.6mV
3.682ns   659.6mV    -11.58mV   944.7mV
4.045ns   659.6mV    360.7mV    944.7mV
4.5ns     659.6mV    400.6mV    944.7mV
[Rising Waveform]
R_fixture = 50.0000
V_fixture = 1.8000
V_fixture_min = 1.6200
V_fixture_max = 1.9800
| time   V(typ)   V(min)   V(max)
0s        616.3mV    835.2mV    470.5mV
454.5ps   615.8mV    838.9mV    543.3mV
545.5ps   614.2mV    838.1mV    1.851V
636.4ps   612.2mV    837.4mV    1.966V
863.6ps   610.1mV    836.1mV    1.98V
1ns       1.51V      835.5mV    1.98V
1.136ns   1.781V     834.9mV    1.98V
3.5ns     1.8V       812.1mV    1.98V
3.864ns   1.8V       1.579V     1.98V
4.5ns     1.8V       1.62V      1.98V
[Falling Waveform]
R_fixture = 50.0000
V_fixture = 0.000
V_fixture_min = 0.000
V_fixture_max = 0.000
| time   V(typ)   V(min)   V(max)
0s        659.6mV    400.4mV    944.7mV
303ps     669.9mV    401mV      934.3mV
363.6ps   660.8mV    407.3mV    828.6mV
424.2ps   611.1mV    408mV      683.3mV
585.9ps   420.2mV    366.2mV    133.6mV
686.9ps   266.3mV    319.4mV    49.17mV
808.1ps   102.4mV    260.3mV    13.46mV
1.03ns    22.13mV    122mV      1.753mV
1.394ns   1.872mV    33.77mV    586.3uV
2ns       529.6uV    2.312mV    86.36uV
[Falling Waveform]
R_fixture = 50.0000
V_fixture = 1.8000
V_fixture_min = 1.6200
V_fixture_max = 1.9800
| time   V(typ)   V(min)   V(max)
0s        1.8V       1.62V      1.98V
409.1ps   1.808V     1.62V      1.991V
545.5ps   1.808V     1.625V     1.896V
636.4ps   1.803V     1.626V     1.735V
954.5ps   1.605V     1.622V     732.3mV
1.182ns   1.248V     1.587V     530.3mV
1.546ns   835.4mV    1.464V     484.3mV
1.909ns   685mV      1.251V     474.4mV
2.818ns   623.2mV    933.2mV    470.7mV
4.5ns     616.5mV    843.3mV    470.5mV
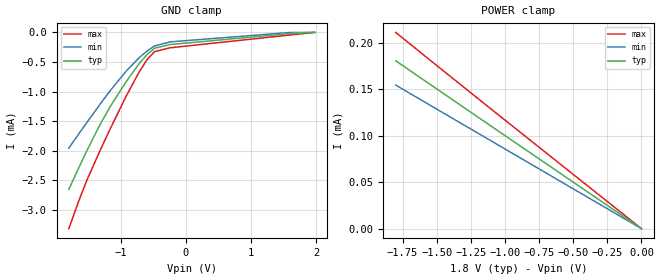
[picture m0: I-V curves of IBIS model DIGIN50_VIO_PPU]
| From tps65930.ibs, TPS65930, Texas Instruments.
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|   Model DIGIN50_VIO_PPU
[Model]   DIGIN50_VIO_PPU
Model_type   Input
Polarity   Non-Inverting
Vinl =   0.6930V
Vinh =   1.0530V
C_comp   88.2060fF   91.8277fF   84.044fF
[Temperature Range]   25.0000   0.1250k   -40.0000
[Pullup Reference]   1.8000V   1.6200V   1.9800V
[Pulldown Reference]   0.000V   0.000V   0.000V
[POWER Clamp Reference]   1.8000V   1.6200V   1.9800V
[GND Clamp Reference]   0.000V   0.000V   0.000V
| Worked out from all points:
|   GND clamp passes 1 mA (typ) near -1.02 V on its own axis
[GND_clamp]
| voltage   I(typ)   I(min)   I(max)
-1.8V     -2.651mA   -1.955mA   -3.315mA
-1.64V    -2.271mA   -1.704mA   -2.827mA
-1.52V    -1.993mA   -1.518mA   -2.491mA
-1.32V    -1.557mA   -1.214mA   -1.997mA
-1.16V    -1.247mA   -979.3uA   -1.622mA
-920mV    -835uA     -656.6uA   -1.082mA
-720mV    -530.8uA   -429.8uA   -672.6uA
-600mV    -378uA     -316.6uA   -463.1uA
-480mV    -267.3uA   -227.8uA   -323.4uA
-240mV    -204.4uA   -159.8uA   -259.7uA
1.6V      -20uA      -1.713uA   -44.32uA
1.98V     0A         0A         0A
[POWER_clamp]
| voltage   I(typ)   I(min)   I(max)
-1.8V     180.5uA    154.4uA    211uA
-1.52V    152.3uA    130.3uA    177.8uA
-1.04V    104.1uA    89.13uA    121.4uA
0V        64.69pA    430pA      321.7pA
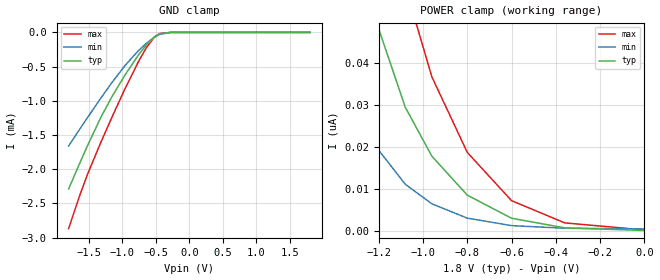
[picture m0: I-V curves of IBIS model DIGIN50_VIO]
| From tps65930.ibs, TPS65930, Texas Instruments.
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|   Model DIGIN50_VIO
[Model]   DIGIN50_VIO
Model_type   Input
Polarity   Non-Inverting
Vinl =   0.6930V
Vinh =   1.0530V
C_comp   61.0594fF   64.6518fF   22.5728fF
[Temperature Range]   25.0000   0.1250k   -40.0000
[Pullup Reference]   1.8000V   1.6200V   1.8900V
[Pulldown Reference]   0.000V   0.000V   0.000V
[POWER Clamp Reference]   1.8000V   1.6200V   1.8900V
[GND Clamp Reference]   0.000V   0.000V   0.000V
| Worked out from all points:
|   GND clamp passes 1 mA (typ) near -1.19 V on its own axis
[GND_clamp]
| voltage   I(typ)   I(min)   I(max)
-1.8V     -2.29mA    -1.661mA   -2.87mA
-1.64V    -1.926mA   -1.424mA   -2.401mA
-1.52V    -1.66mA    -1.249mA   -2.08mA
-1.32V    -1.244mA   -961.6uA   -1.609mA
-1.16V    -950.5uA   -741.1uA   -1.254mA
-960mV    -624uA     -485.9uA   -824.7uA
-760mV    -331uA     -267.7uA   -429.3uA
-640mV    -181uA     -158.4uA   -221uA
-520mV    -65.3uA    -70.57uA   -66.12uA
-440mV    -19.98uA   -29.3uA    -16.29uA
-280mV    -194.6nA   -1.081uA   -58.26nA
1.8V      64.69pA    474pA      96.05pA
[POWER_clamp]
| voltage   I(typ)   I(min)   I(max)
-1.8V     308.6nA    153.2nA    511.1nA
-1.5V     130.3nA    58.33nA    229.7nA
-1.48V    122.4nA    54.37nA    216.7nA
-1.36V    82.67nA    35.01nA    150.8nA
-1.26V    58.3nA     23.68nA    109.3nA
-1.24V    54.23nA    21.84nA    102.2nA
-1.08V    29.36nA    11.06nA    58.14nA
-960mV    17.74nA    6.407nA    36.62nA
-800mV    8.472nA    3nA        18.63nA
-600mV    2.97nA     1.217nA    7.157nA
-360mV    688.6pA    591.7pA    1.874nA
0V        64.69pA    430pA      174.5pA
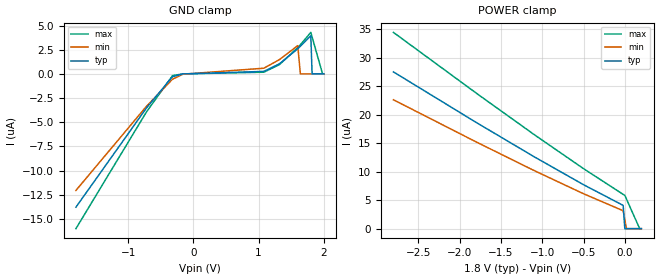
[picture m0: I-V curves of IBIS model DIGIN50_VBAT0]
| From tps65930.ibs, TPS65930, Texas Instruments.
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|   Model DIGIN50_VBAT0
[Model]   DIGIN50_VBAT0
Model_type   Input
Polarity   Non-Inverting
Vinl =   0.6930V
Vinh =   1.0530V
C_comp   84.1290fF   75.7959fF   80.8330fF
[Temperature Range]   25.0000   0.1250k   -40.0000
[Voltage Range]   1.8000V   1.6200V   1.9800V
[GND_clamp]
| voltage   I(typ)   I(min)   I(max)
-1.8V     -13.78uA   -12.05uA   -16uA
-720mV    -3.533uA   -3.362uA   -3.947uA
-320mV    -291nA     -551.8nA   -183.3nA
-160mV    -1.785nA   -32.41nA   -341.8pA
1.08V     256.6nA    586.7nA    173.5nA
1.32V     1.045uA    1.48uA     961.7nA
1.6V      2.601uA    2.921uA    2.712uA
1.64V     2.858uA    0A         3.011uA
1.8V      3.945uA    0A         4.289uA
1.82V     0A         0A         3.813uA
1.98V     0A         0A         0A
2V        0A         0A         0A
[POWER_clamp]
| voltage   I(typ)   I(min)   I(max)
-2.8V     27.55uA    22.65uA    34.49uA
-1.8V     18.68uA    15.25uA    23.84uA
-1.1V     12.66uA    10.23uA    16.56uA
-500mV    7.726uA    6.137uA    10.55uA
-20mV     4.087uA    3.149uA    6.024uA
0V        0A         1.574uA    5.845uA
20mV      0A         0A         5.196uA
180mV     0A         0A         0A
200mV     0A         0A         0A
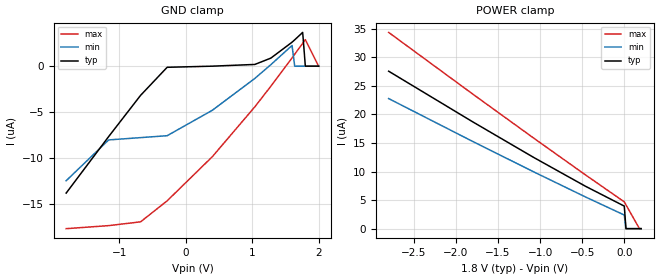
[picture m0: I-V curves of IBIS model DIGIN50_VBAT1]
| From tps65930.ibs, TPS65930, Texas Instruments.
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|   Model DIGIN50_VBAT1
[Model]   DIGIN50_VBAT1
Model_type   Input
Polarity   Non-Inverting
Vinl =   0.6930V
Vinh =   1.0530V
C_comp   14.9310fF   16.9850fF   9.4560fF
[Temperature Range]   25.0000   0.1250k   -40.0000
[Voltage Range]   1.8000V   1.6200V   1.9800V
[GND_clamp]
| voltage   I(typ)   I(min)   I(max)
-1.8V     -13.78uA   -12.44uA   -17.64uA
-1.16V    -7.642uA   -8.007uA   -17.31uA
-680mV    -3.171uA   -7.757uA   -16.9uA
-280mV    -122.8nA   -7.549uA   -14.62uA
400mV     186.9pA    -4.788uA   -9.828uA
1.04V     187.1nA    -1.329uA   -4.414uA
1.28V     871.3nA    157.2nA    -2.186uA
1.6V      2.601uA    2.247uA    899.4nA
1.64V     2.858uA    0A         1.292uA
1.76V     3.666uA    0A         2.48uA
1.8V      0A         0A         2.879uA
2V        0A         0A         0A
[POWER_clamp]
| voltage   I(typ)   I(min)   I(max)
-2.8V     27.55uA    22.76uA    34.34uA
-1.8V     18.68uA    15.25uA    23.54uA
-1.08V    12.49uA    9.965uA    15.88uA
-460mV    7.409uA    5.539uA    9.393uA
0V        3.945uA    2.381uA    4.686uA
20mV      0A         0A         4.166uA
180mV     0A         0A         0A
200mV     0A         0A         0A
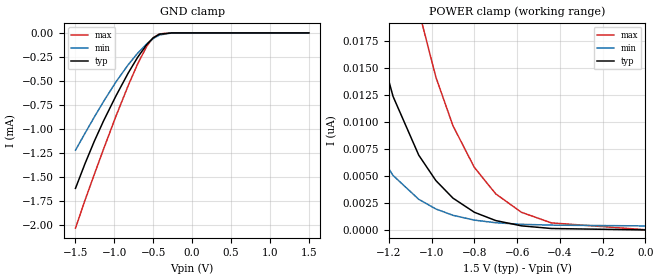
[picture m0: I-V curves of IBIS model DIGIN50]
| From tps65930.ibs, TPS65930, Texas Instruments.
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|   Model DIGIN50
[Model]   DIGIN50
Model_type   Input
Polarity   Non-Inverting
Vinl =   0.5775V
Vinh =   0.8775V
C_comp   61.1600fF   64.7000fF   28.0140fF
[Temperature Range]   25.0000   0.1250k   -40.0000
[Voltage Range]   1.5000V   1.3500V   1.6500V
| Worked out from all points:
|   GND clamp passes 1 mA (typ) near -1.19 V on its own axis
[GND_clamp]
| voltage   I(typ)   I(min)   I(max)
-1.5V     -1.616mA   -1.219mA   -2.03mA
-1.38V    -1.364mA   -1.047mA   -1.745mA
-1.26V    -1.13mA    -877.7uA   -1.475mA
-1.14V    -916.2uA   -714.3uA   -1.21mA
-980mV    -655.2uA   -510uA     -866.5uA
-820mV    -414.3uA   -328.7uA   -543.2uA
-700mV    -252.9uA   -210.8uA   -321uA
-580mV    -117.4uA   -111.3uA   -133.7uA
-500mV    -51.16uA   -58.69uA   -49.23uA
-420mV    -13.39uA   -21.9uA    -10.34uA
-260mV    -91.39nA   -630.2nA   -21.99nA
1.5V      22.23pA    415.2pA    24.12pA
[POWER_clamp]
| voltage   I(typ)   I(min)   I(max)
-1.5V     46.79nA    20.97nA    109.3nA
-1.38V    29.36nA    12.62nA    72.31nA
-1.3V     21.08nA    8.842nA    53.96nA
-1.18V    12.38nA    5.066nA    33.78nA
-1.06V    6.95nA     2.861nA    20.35nA
-980mV    4.598nA    1.966nA    14.18nA
-900mV    2.97nA     1.378nA    9.672nA
-800mV    1.66nA     933.8pA    5.813nA
-700mV    892pA      690.3pA    3.366nA
-580mV    404.5pA    544.7pA    1.659nA
-440mV    156.9pA    470.8pA    678.1pA
0V        22.24pA    395.4pA    43.62pA
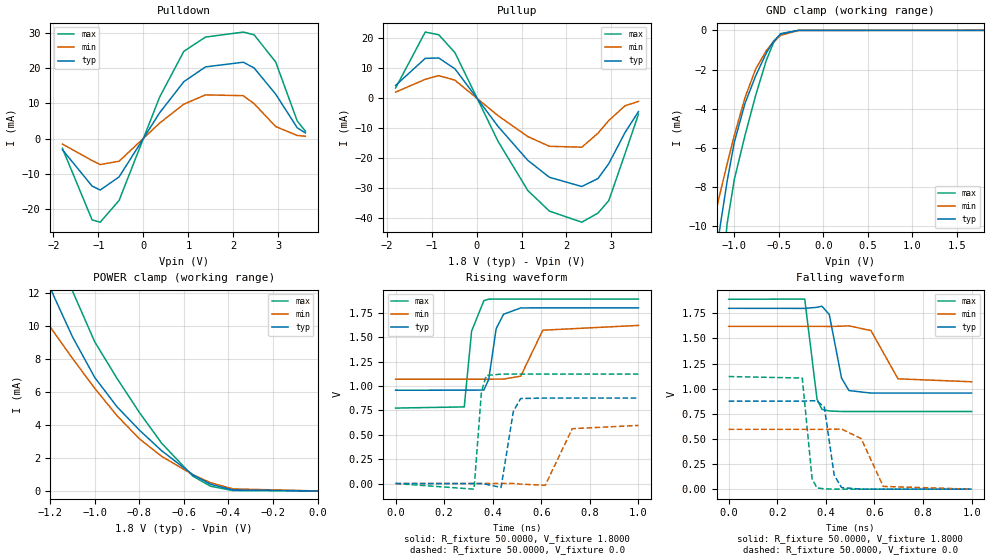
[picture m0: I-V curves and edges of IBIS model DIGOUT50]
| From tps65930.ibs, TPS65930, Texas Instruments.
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|   Model DIGOUT50
[Model]   DIGOUT50
Model_type   3-state
Polarity   Non-Inverting
Enable   Active-Low
Vmeas =   0.9000V
Cref =   30.0000pF
Rref =   100.0000M
Vref =   0.0V
C_comp   0.9655pF   0.8921pF   1.2889pF
[Temperature Range]   25.0000   0.1250k   -40.0000
[Pullup Reference]   1.8000V   1.6200V   1.8900V
[Pulldown Reference]   0.0V   0.0V   0.0V
[POWER Clamp Reference]   1.8000V   1.6200V   1.8900V
[GND Clamp Reference]   0.0V   0.0V   0.0V
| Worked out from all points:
|   slope of the pulldown table from 0 to 0.27 V, typ, clamps not added: 48.4 ohm
|   slope of the pullup table from 0 to 0.27 V, typ, clamps not added: 49.1 ohm
|   GND clamp passes 1 mA (typ) near -0.62 V on its own axis
|   POWER clamp passes 1 mA (typ) near -0.56 V on its own axis
|   rising waveform, R_fixture 50.0000, V_fixture 1.8000: 20-80 % time 33ps typ, 45.9ps min, 25.7ps max; typ from 0.956 V to 1.8 V
|   rising waveform, R_fixture 50.0000, V_fixture 0.0: 20-80 % time 28.6ps typ, 48.9ps min, 17.9ps max; typ from 0 V to 0.876 V
|   falling waveform, R_fixture 50.0000, V_fixture 1.8000: 20-80 % time 36.2ps typ, 55.2ps min, 26.5ps max; typ from 1.8 V to 0.956 V
|   falling waveform, R_fixture 50.0000, V_fixture 0.0: 20-80 % time 28.2ps typ, 51.3ps min, 20.6ps max; typ from 0.876 V to 0 V
[Pulldown]
|Voltage   I(typ)   I(min)   I(max)
-1.8V     -3.117mA   -1.519mA   -2.738mA
-1.14V    -13.4mA    -6.188mA   -22.96mA
-960mV    -14.52mA   -7.304mA   -23.61mA
-540mV    -10.8mA    -6.372mA   -17.45mA
360mV     7.32mA     4.409mA    11.75mA
900mV     16.14mA    9.778mA    24.72mA
1.38V     20.3mA     12.39mA    28.74mA
2.22V     21.63mA    12.17mA    30.15mA
2.46V     20.01mA    9.92mA     29.39mA
2.94V     12.61mA    3.44mA     21.71mA
3.42V     3.086mA    915.9uA    4.992mA
3.6V      1.642mA    693.7uA    2.136mA
[Pullup]
|Voltage   I(typ)   I(min)   I(max)
-1.8V     4.049mA    1.82mA     3.179mA
-1.14V    13.06mA    6.095mA    21.8mA
-840mV    13.19mA    7.322mA    20.91mA
-480mV    9.59mA     5.802mA    14.97mA
480mV     -9.593mA   -6.013mA   -14.56mA
1.14V     -20.85mA   -12.95mA   -30.88mA
1.62V     -26.49mA   -16.18mA   -37.74mA
2.34V     -29.55mA   -16.49mA   -41.42mA
2.7V      -26.9mA    -11.83mA   -38.39mA
2.94V     -21.95mA   -7.614mA   -34.24mA
3.3V      -11.63mA   -2.715mA   -18.68mA
3.6V      -4.628mA   -1.246mA   -5.519mA
[GND_clamp]
|Voltage   I(typ)   I(min)   I(max)
-1.8V     -31.87mA   -21.26mA   -53.26mA
-1.24V    -12.54mA   -9.856mA   -17.9mA
-1.16V    -10.01mA   -8.305mA   -13.47mA
-1.08V    -7.671mA   -6.799mA   -9.84mA
-1V       -5.7mA     -5.36mA    -7.597mA
-880mV    -3.718mA   -3.424mA   -5.353mA
-760mV    -2.315mA   -1.966mA   -3.305mA
-640mV    -1.146mA   -1.028mA   -1.511mA
-560mV    -555.3uA   -579.2uA   -630.5uA
-480mV    -186.7uA   -253uA     -164.7uA
-280mV    -757.7nA   -4.254uA   -228.1nA
1.8V      133.3pA    1.256uA    189.8pA
[POWER_clamp]
|Voltage   I(typ)   I(min)   I(max)
-1.8V     32.87mA    22.14mA    54.5mA
-1.3V     15.56mA    11.92mA    22.77mA
-1.18V    11.71mA    9.568mA    15.92mA
-1.1V     9.352mA    8.045mA    12.13mA
-1V       6.882mA    6.226mA    9.046mA
-900mV    5.107mA    4.564mA    6.828mA
-800mV    3.698mA    3.167mA    4.771mA
-700mV    2.442mA    2.101mA    2.899mA
-560mV    987.6uA    987.5uA    899uA
-480mV    405.9uA    499.3uA    282.8uA
-380mV    56.76uA    122uA      23.73uA
0V        133.3pA    1.586nA    442.2pA
[Ramp]
| variable   typ   min   max
dV/dt_r   0.5257/28.3152p   0.3573/48.4583p   0.6727/17.7294p
dV/dt_f   0.5063/35.8888p   0.3304/54.6548p   0.6702/26.2058p
R_load =   50.0000
[Rising Waveform]
R_fixture=   50.0000
V_fixture=   1.8000
V_fixture_min=  1.6200
V_fixture_max=  1.8900
|time   V(typ)   V(min)   V(max)
0s        956.2mV    1.069V     773mV
282.8ps   956.3mV    1.069V     785.1mV
313.1ps   956.7mV    1.069V     1.562V
363.6ps   957.8mV    1.069V     1.874V
383.8ps   1.069V     1.069V     1.889V
414.1ps   1.586V     1.07V      1.89V
444.4ps   1.734V     1.07V      1.89V
515.2ps   1.799V     1.1V       1.89V
606.1ps   1.8V       1.571V     1.89V
1ns       1.8V       1.62V      1.89V
[Rising Waveform]
R_fixture=   50.0000
V_fixture=   0.0
V_fixture_min=  0.0
V_fixture_max=  0.0
|time   V(typ)   V(min)   V(max)
0s        5.687nV    158.7nV    6.917nV
323.2ps   -22.96uV   2.139uV    -57.77mV
353.5ps   -315.9uV   -2.122uV   938.6mV
373.7ps   -8.462mV   -20.49uV   1.107V
434.3ps   -40.24mV   -34.76uV   1.121V
484.8ps   738.7mV    311.4uV    1.121V
515.2ps   871.1mV    -5.921mV   1.121V
616.2ps   876.1mV    -18.06mV   1.121V
727.3ps   876.1mV    561.9mV    1.121V
1ns       876.1mV    595.5mV    1.121V
[Falling Waveform]
R_fixture=   50.0000
V_fixture=   1.8000
V_fixture_min=  1.6200
V_fixture_max=  1.8900
|time   V(typ)   V(min)   V(max)
0s        1.8V       1.62V      1.89V
313.1ps   1.799V     1.62V      1.892V
363.6ps   1.81V      1.62V      895.7mV
383.8ps   1.821V     1.62V      794.7mV
414.1ps   1.738V     1.619V     778.2mV
464.6ps   1.106V     1.622V     773.1mV
494.9ps   981.4mV    1.626V     772.9mV
585.9ps   956.5mV    1.578V     773mV
697ps     956.2mV    1.098V     773mV
1ns       956.2mV    1.069V     773mV
[Falling Waveform]
R_fixture=   50.0000
V_fixture=   0.0
V_fixture_min=  0.0
V_fixture_max=  0.0
|time   V(typ)   V(min)   V(max)
0s        876.1mV    595.5mV    1.121V
303ps     875.6mV    595.5mV    1.106V
343.4ps   880.4mV    595.5mV    102.4mV
363.6ps   878.4mV    595.4mV    12.18mV
393.9ps   816mV      595.2mV    3.11mV
434.3ps   140.8mV    596.6mV    328.9uV
464.6ps   16.09mV    598.9mV    23.27uV
545.5ps   445.1uV    502.9mV    -3.784uV
636.4ps   -3.7uV     27.37mV    53.8nV
1ns       -8.885nV   2.204uV    8.317nV
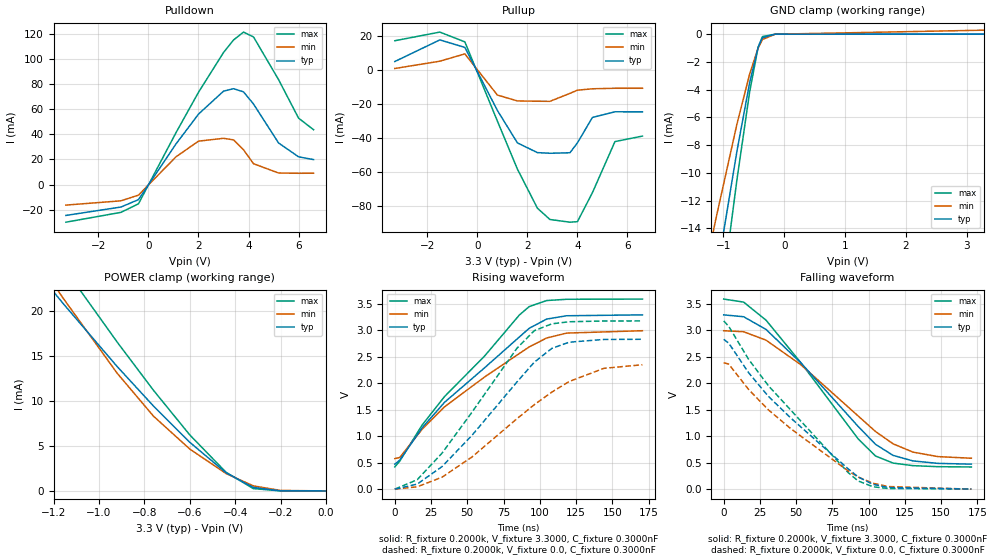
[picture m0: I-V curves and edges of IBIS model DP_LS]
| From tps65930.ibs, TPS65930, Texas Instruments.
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|   Model DP_LS
[Model]  DP_LS
Model_type 3-state
Polarity   Non-Inverting
Enable   Active-Low
|Vinl =   1.1550V
|Vinh =   2.1450V
Vmeas =  1.6500V
Cref =   0.3000nF
Rref =   100.0000M
Vref =   0.0V
C_comp   6.1523pF   6.1128pF   6.1708pF
[Temperature Range]   25.0000   0.1250k   -40.0000
[Pullup Reference]   3.3000V   3.0000V   3.6000V
[Pulldown Reference]   0.0V   0.0V   0.0V
[POWER Clamp Reference]   3.3000V   3.0000V   3.6000V
[GND Clamp Reference]   0.0V   0.0V   0.0V
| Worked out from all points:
|   slope of the pulldown table from 0 to 0.495 V, typ, clamps not added: 33.1 ohm
|   slope of the pullup table from 0 to 0.495 V, typ, clamps not added: 32.5 ohm
|   GND clamp passes 1 mA (typ) near -0.43 V on its own axis
|   POWER clamp passes 1 mA (typ) near -0.38 V on its own axis
|   rising waveform, R_fixture 0.2000k, V_fixture 3.3000, C_fixture 0.3000nF: 20-80 % time 64.7ns typ, 66.6ns min, 60.9ns max; typ from 0.474 V to 3.29 V
|   rising waveform, R_fixture 0.2000k, V_fixture 0.0, C_fixture 0.3000nF: 20-80 % time 53.8ns typ, 64.3ns min, 49.7ns max; typ from 0.003 V to 2.83 V
|   falling waveform, R_fixture 0.2000k, V_fixture 3.3000, C_fixture 0.3000nF: 20-80 % time 56.6ns typ, 59.9ns min, 53ns max; typ from 3.29 V to 0.477 V
|   falling waveform, R_fixture 0.2000k, V_fixture 0.0, C_fixture 0.3000nF: 20-80 % time 63.3ns typ, 62.9ns min, 60.6ns max; typ from 2.83 V to 0.007 V
[Pulldown]
|Voltage   I(typ)   I(min)   I(max)
-3.3V     -24.66mA   -16.41mA   -30.04mA
-1.1V     -17.95mA   -13mA      -22.2mA
-400mV    -12.07mA   -8.474mA   -15.4mA
1.1V      32.31mA    22.07mA    41.3mA
2V        56.12mA    34.56mA    73.51mA
3V        74.4mA     36.82mA    105.2mA
3.4V      76.38mA    35.58mA    115.2mA
3.8V      73.84mA    27.66mA    121.5mA
4.2V      64.12mA    16.57mA    117.6mA
5.2V      33.12mA    9.179mA    83.64mA
6V        22.07mA    8.949mA    52.91mA
6.6V      19.86mA    9.006mA    43.68mA
[Pullup]
|Voltage   I(typ)   I(min)   I(max)
-3.3V     4.986mA    892.9uA    17.22mA
-1.5V     17.71mA    5.182mA    22.3mA
-500mV    13.29mA    9.474mA    16.55mA
800mV     -23.75mA   -14.72mA   -30.01mA
1.6V      -42.83mA   -18.18mA   -58.24mA
2.4V      -48.58mA   -18.36mA   -81.24mA
2.9V      -48.96mA   -18.42mA   -87.9mA
3.7V      -48.66mA   -13.73mA   -89.49mA
4V        -42.83mA   -11.87mA   -89.19mA
4.6V      -27.88mA   -11.04mA   -72.1mA
5.5V      -24.57mA   -10.73mA   -42.09mA
6.6V      -24.6mA    -10.73mA   -38.85mA
[GND_clamp]
|Voltage   I(typ)   I(min)   I(max)
-3.3V     -81.85mA   -63mA      -101.5mA
-1.62V    -31.7mA    -23.93mA   -39.66mA
-1.55V    -29.68mA   -22.39mA   -37.14mA
-1.34V    -23.66mA   -17.84mA   -29.65mA
-1.27V    -21.68mA   -16.35mA   -27.18mA
-1.13V    -17.78mA   -13.42mA   -22.3mA
-780mV    -8.466mA   -6.506mA   -10.53mA
-570mV    -3.5mA     -2.877mA   -4.17mA
-430mV    -952.3uA   -990.8uA   -936.3uA
-360mV    -254.5uA   -387.4uA   -175.3uA
-150mV    -159.5nA   -2.336uA   -11.79nA
3.28V     -1.065nA   287.8uA    719.4fA
[POWER_clamp]
|Voltage   I(typ)   I(min)   I(max)
-3.28V    107.5mA    105.3mA    115.4mA
-1.32V    25.97mA    27.48mA    30.86mA
-1.28V    24.66mA    25.97mA    29.39mA
-1.24V    23.38mA    24.47mA    27.92mA
-1.16V    20.89mA    21.5mA     25.02mA
-920mV    13.83mA    13.09mA    16.55mA
-760mV    9.439mA    8.315mA    11.19mA
-600mV    5.408mA    4.656mA    6.228mA
-440mV    2.013mA    1.929mA    2.07mA
-320mV    385.2uA    564.3uA    258.4uA
-200mV    11.92uA    55.37uA    2.562uA
0V        2.348nA    59.16nA    498.2pA
[Ramp]
| variable   typ   min   max
dV/dt_r  0.1695/12.9594n   94.0119m/12.3471n   0.2654/13.6266n
dV/dt_f  0.2120/15.0408n   0.1440/14.2087n   0.2860/14.9171n
R_load = 50.0000
[Rising Waveform]
R_fixture= 0.2000k
V_fixture= 3.3000
V_fixture_min= 3.0000
V_fixture_max= 3.6000
C_fixture= 0.3000nF
|time   V(typ)   V(min)   V(max)
0s        474.5mV    579.1mV    422.8mV
3.434ns   551.2mV    600.9mV    533.6mV
18.89ns   1.162V     1.135V     1.215V
34.34ns   1.643V     1.557V     1.752V
61.82ns   2.291V     2.118V     2.512V
85.86ns   2.874V     2.562V     3.288V
92.73ns   3.039V     2.688V     3.449V
104.7ns   3.212V     2.855V     3.562V
118.5ns   3.275V     2.948V     3.586V
170.8ns   3.292V     2.993V     3.59V
[Rising Waveform]
R_fixture= 0.2000k
V_fixture= 0.0
V_fixture_min= 0.0
V_fixture_max= 0.0
C_fixture= 0.3000nF
|time   V(typ)   V(min)   V(max)
0s        3.146mV    3.904mV    3.322mV
15.45ns   98.36mV    47.45mV    181.4mV
32.63ns   430.2mV    229.9mV    684.7mV
53.23ns   1.019V     610.5mV    1.456V
84.14ns   2.022V     1.33V      2.659V
96.16ns   2.398V     1.596V     2.993V
108.2ns   2.658V     1.833V     3.122V
120.2ns   2.776V     2.034V     3.162V
144.2ns   2.828V     2.283V     3.176V
170.8ns   2.831V     2.351V     3.177V
[Falling Waveform]
R_fixture= 0.2000k
V_fixture= 3.3000
V_fixture_min= 3.0000
V_fixture_max= 3.6000
C_fixture= 0.3000nF
|time   V(typ)   V(min)   V(max)
0s        3.292V     2.993V     3.59V
13.74ns   3.257V     2.974V     3.533V
29.19ns   3.017V     2.815V     3.192V
53.23ns   2.387V     2.351V     2.39V
92.73ns   1.188V     1.385V     953.6mV
104.7ns   851.2mV    1.092V     630.5mV
116.8ns   642.3mV    860.5mV    497.4mV
130.5ns   537.7mV    704.2mV    448.6mV
147.7ns   491.4mV    619.2mV    429.3mV
170.8ns   476.9mV    588.4mV    423.4mV
[Falling Waveform]
R_fixture= 0.2000k
V_fixture= 0.0
V_fixture_min= 0.0
V_fixture_max= 0.0
C_fixture= 0.3000nF
|time   V(typ)   V(min)   V(max)
0s        2.831V     2.39V      3.177V
3.434ns   2.76V      2.364V     3.077V
17.17ns   2.201V     1.885V     2.454V
30.91ns   1.752V     1.498V     1.953V
46.36ns   1.344V     1.143V     1.493V
85.86ns   388.5mV    349mV      317.4mV
92.73ns   235.7mV    233.7mV    159.4mV
103ns     95.54mV    116.6mV    50.22mV
113.3ns   36.75mV    54.8mV     18.21mV
170.8ns   6.586mV    5.153mV    7.91mV
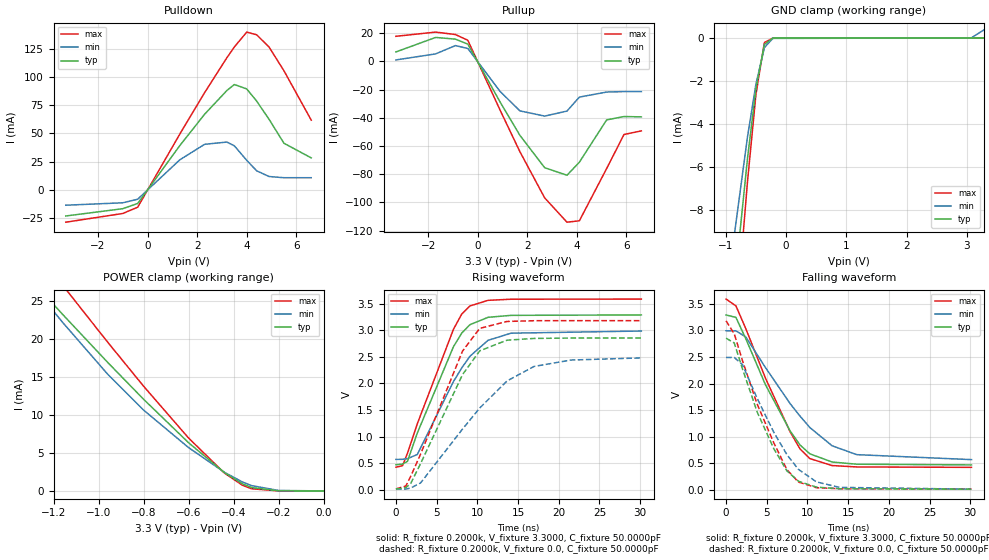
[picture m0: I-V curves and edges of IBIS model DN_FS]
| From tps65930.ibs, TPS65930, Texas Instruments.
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|   Model DN_FS
[Model]  DN_FS
Model_type 3-state
Polarity   Inverting
Enable   Active-Low
|Vinl =   1.1550V
|Vinh =   2.1450V
Vmeas =  1.6500V
Cref =   50.0000pF
Rref =   100.0000M
Vref =   0.0V
C_comp   6.1523pF   6.1128pF   6.1708pF
[Temperature Range]   25.0000   0.1250k   -40.0000
[Pullup Reference]   3.3000V   3.0000V   3.6000V
[Pulldown Reference]   0.0V   0.0V   0.0V
[POWER Clamp Reference]   3.3000V   3.0000V   3.6000V
[GND Clamp Reference]   0.0V   0.0V   0.0V
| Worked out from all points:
|   slope of the pulldown table from 0 to 0.495 V, typ, clamps not added: 32.2 ohm
|   slope of the pullup table from 0 to 0.495 V, typ, clamps not added: 30.4 ohm
|   GND clamp passes 1 mA (typ) near -0.42 V on its own axis
|   POWER clamp passes 1 mA (typ) near -0.36 V on its own axis
|   rising waveform, R_fixture 0.2000k, V_fixture 3.3000, C_fixture 50.0000pF: 20-80 % time 4.63ns typ, 5.26ns min, 4.69ns max; typ from 0.468 V to 3.29 V
|   rising waveform, R_fixture 0.2000k, V_fixture 0.0, C_fixture 50.0000pF: 20-80 % time 5.3ns typ, 8.19ns min, 5.04ns max; typ from 0.011 V to 2.86 V
|   falling waveform, R_fixture 0.2000k, V_fixture 3.3000, C_fixture 50.0000pF: 20-80 % time 5.43ns typ, 7.08ns min, 5.37ns max; typ from 3.29 V to 0.468 V
|   falling waveform, R_fixture 0.2000k, V_fixture 0.0, C_fixture 50.0000pF: 20-80 % time 4.53ns typ, 5.14ns min, 4.78ns max; typ from 2.85 V to 0.011 V
[Pulldown]
|Voltage   I(typ)   I(min)   I(max)
-3.3V     -23.55mA   -13.95mA   -29.08mA
-1V       -17.04mA   -11.78mA   -21.31mA
-400mV    -12.38mA   -8.592mA   -15.71mA
1.3V      39.22mA    26.54mA    49.51mA
2.3V      67.18mA    40.35mA    86.43mA
3.2V      88.36mA    42.36mA    117.6mA
3.5V      93.66mA    39mA       127.2mA
4V        89.71mA    26.02mA    140.4mA
4.4V      78.84mA    16.72mA    138mA
4.9V      62.6mA     11.63mA    127mA
5.5V      41.3mA     10.58mA    105.9mA
6.6V      28.24mA    10.56mA    61.91mA
[Pullup]
|Voltage   I(typ)   I(min)   I(max)
-3.3V     6.65mA     971uA      17.74mA
-1.7V     16.93mA    5.263mA    20.73mA
-900mV    15.74mA    11.16mA    19mA
-400mV    12.19mA    9.092mA    14.92mA
900mV     -28.79mA   -21.32mA   -34.55mA
1.7V      -52.48mA   -35.14mA   -64.08mA
2.7V      -75.46mA   -38.85mA   -96.84mA
3.6V      -80.8mA    -35.29mA   -114.1mA
4.1V      -71.55mA   -25.37mA   -113.1mA
5.2V      -41.54mA   -21.79mA   -76.05mA
5.9V      -39.17mA   -21.48mA   -51.9mA
6.6V      -39.4mA    -21.51mA   -49.33mA
[GND_clamp]
|Voltage   I(typ)   I(min)   I(max)
-3.3V     -84.07mA   -66.05mA   -103.3mA
-1.55V    -31.3mA    -24.26mA   -38.5mA
-1.34V    -25.1mA    -19.48mA   -30.87mA
-1.27V    -23.05mA   -17.91mA   -28.35mA
-1.2V     -21.02mA   -16.34mA   -25.84mA
-1.13V    -19mA      -14.8mA    -23.34mA
-640mV    -5.584mA   -4.582mA   -6.658mA
-500mV    -2.356mA   -2.137mA   -2.616mA
-360mV    -297.1uA   -445.6uA   -211.6uA
-220mV    -2.981uA   -18.22uA   -518.8nA
3.07V     -6.299nA   1.807uA    -156.6pA
3.28V     39.21pA    371.2uA    10.26pA
[POWER_clamp]
|Voltage   I(typ)   I(min)   I(max)
-3.28V    107.8mA    105.5mA    116.1mA
-1.32V    28.41mA    28mA       33.17mA
-1.28V    27.1mA     26.52mA    31.63mA
-1.16V    23.21mA    22.16mA    27.05mA
-960mV    16.91mA    15.36mA    19.57mA
-800mV    12.05mA    10.63mA    13.77mA
-600mV    6.341mA    5.7mA      6.96mA
-440mV    2.397mA    2.441mA    2.335mA
-360mV    930.6uA    1.174mA    740.2uA
-320mV    446.5uA    698.7uA    286.4uA
-200mV    13.06uA    62.21uA    2.792uA
0V        3.503nA    81.15nA    958.5pA
[Ramp]
| variable   typ   min   max
dV/dt_r  1.2075/5.6269n   0.9185/10.1363n   1.4105/5.5535n
dV/dt_f  1.1859/5.6789n   0.9025/7.3480n   1.4114/5.9441n
R_load = 50.0000
[Rising Waveform]
R_fixture= 0.2000k
V_fixture= 3.3000
V_fixture_min= 3.0000
V_fixture_max= 3.6000
C_fixture= 50.0000pF
|time   V(typ)   V(min)   V(max)
0s        467.9mV    569.2mV    422.2mV
808.1ps   480.5mV    569.9mV    449mV
1.414ns   531.4mV    581.4mV    683.4mV
2.626ns   1.065V     661.2mV    1.24V
7.071ns   2.693V     2.036V     3.021V
8.081ns   2.948V     2.291V     3.306V
9.091ns   3.107V     2.512V     3.46V
11.31ns   3.246V     2.812V     3.566V
14.14ns   3.283V     2.947V     3.587V
30.15ns   3.291V     2.988V     3.59V
[Rising Waveform]
R_fixture= 0.2000k
V_fixture= 0.0
V_fixture_min= 0.0
V_fixture_max= 0.0
C_fixture= 50.0000pF
|time   V(typ)   V(min)   V(max)
0s        10.54mV    7.553mV    12.64mV
1.212ns   36.05mV    10.03mV    65.73mV
1.818ns   115.8mV    29.02mV    249mV
3.03ns    489.5mV    124.8mV    668.9mV
8.182ns   2.167V     1.14V      2.61V
10.3ns    2.615V     1.537V     3.038V
13.64ns   2.815V     2.046V     3.168V
16.97ns   2.848V     2.32V      3.182V
21.52ns   2.855V     2.441V     3.183V
30.15ns   2.856V     2.481V     3.183V
[Falling Waveform]
R_fixture= 0.2000k
V_fixture= 3.3000
V_fixture_min= 3.0000
V_fixture_max= 3.6000
C_fixture= 50.0000pF
|time   V(typ)   V(min)   V(max)
0s        3.291V     2.993V     3.59V
1.212ns   3.245V     2.992V     3.462V
2.424ns   2.844V     2.877V     3.034V
4.848ns   1.975V     2.299V     2.099V
7.879ns   1.106V     1.62V      1.089V
9.091ns   842.6mV    1.386V     767.5mV
10.3ns    676.3mV    1.171V     586.8mV
13.03ns   522.4mV    827.9mV    455.9mV
16.06ns   481.3mV    661.1mV    429.7mV
30.15ns   468.1mV    567.7mV    422.1mV
[Falling Waveform]
R_fixture= 0.2000k
V_fixture= 0.0
V_fixture_min= 0.0
V_fixture_max= 0.0
C_fixture= 50.0000pF
|time   V(typ)   V(min)   V(max)
0s        2.854V     2.491V     3.181V
1.01ns    2.763V     2.49V      2.934V
2.02ns    2.274V     2.355V     2.431V
3.838ns   1.459V     1.715V     1.607V
5.859ns   775.4mV    1.084V     885.8mV
7.475ns   355.9mV    661.9mV    379.3mV
8.889ns   161.1mV    384.2mV    145.2mV
11.11ns   49.69mV    148mV      38.89mV
13.94ns   19.06mV    45.04mV    18.53mV
30.15ns   11.49mV    11.45mV    13.62mV
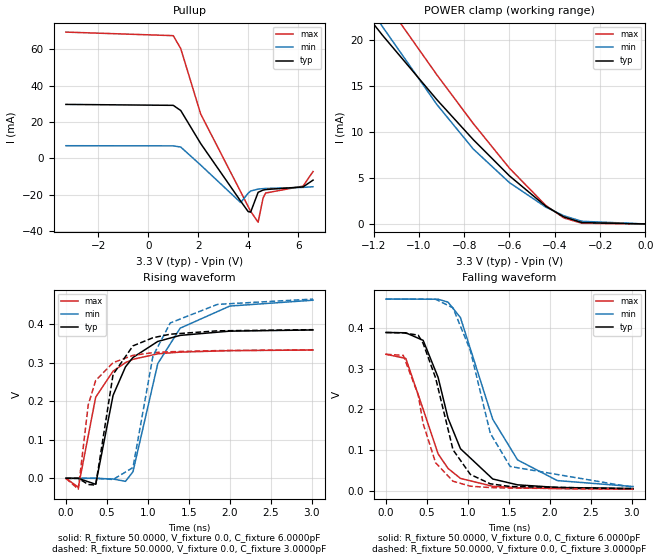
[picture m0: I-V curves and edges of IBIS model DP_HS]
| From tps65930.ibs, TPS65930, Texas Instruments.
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|   Model DP_HS
[Model]  DP_HS
Model_type I/O_open_source
Polarity   Non-Inverting
Enable   Active-High
Vinl =   1.1550V
Vinh =   2.1450V
Vmeas =  0.3000V
Cref =   5.0000pF
Rref =   50.0000
Vref =   0.0V
C_comp   6.1523pF   6.1128pF   6.1708pF
[Temperature Range]   25.0000   0.1250k   -40.0000
[Pullup Reference]   3.3000V   3.0000V   3.6000V
[Pulldown Reference]   0.0V   0.0V   0.0V
[POWER Clamp Reference]   3.3000V   3.0000V   3.6000V
[GND Clamp Reference]   0.0V   0.0V   0.0V
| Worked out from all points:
|   slope of the pullup table from 0 to 0.495 V, typ, clamps not added: 10.8 kohm
|   POWER clamp passes 1 mA (typ) near -0.38 V on its own axis
|   rising waveform, R_fixture 50.0000, V_fixture 0.0, C_fixture 6.0000pF: 20-80 % time 338ps typ, 406ps min, 296ps max; typ from 0 V to 0.385 V
|   rising waveform, R_fixture 50.0000, V_fixture 0.0, C_fixture 3.0000pF: 20-80 % time 220ps typ, 290ps min, 191ps max; typ from 0 V to 0.386 V
|   falling waveform, R_fixture 50.0000, V_fixture 0.0, C_fixture 6.0000pF: 20-80 % time 391ps typ, 479ps min, 327ps max; typ from 0.389 V to 0.006 V
|   falling waveform, R_fixture 50.0000, V_fixture 0.0, C_fixture 3.0000pF: 20-80 % time 317ps typ, 388ps min, 272ps max; typ from 0.389 V to 0.005 V
[Pullup]
|Voltage   I(typ)   I(min)   I(max)
-3.3V     29.62mA    6.891mA    69.41mA
1V        29.11mA    6.815mA    67.45mA
1.3V      26.26mA    6.17mA     60.35mA
2.1V      8.074mA    -3.767mA   24.32mA
3.7V      -23.59mA   -24.36mA   -18.43mA
4V        -29.32mA   -19.25mA   -26.51mA
4.1V      -29.65mA   -18.04mA   -29.21mA
4.4V      -18.73mA   -16.97mA   -35.18mA
4.6V      -17.52mA   -16.71mA   -21.82mA
4.7V      -17.22mA   -16.62mA   -19.13mA
6.2V      -15.78mA   -16.03mA   -15.33mA
6.6V      -12.03mA   -15.68mA   -7.305mA
[POWER_clamp]
|Voltage   I(typ)   I(min)   I(max)
-3.28V    107.5mA    105.3mA    115.4mA
-1.32V    25.64mA    27.45mA    30.4mA
-1.28V    24.31mA    25.93mA    28.93mA
-1.24V    23.01mA    24.43mA    27.48mA
-1.16V    20.52mA    21.45mA    24.6mA
-920mV    13.51mA    12.98mA    16.21mA
-760mV    9.177mA    8.157mA    10.93mA
-600mV    5.228mA    4.491mA    6.062mA
-440mV    1.936mA    1.837mA    2.017mA
-360mV    762.5uA    886.4uA    652.5uA
-280mV    147.6uA    287.8uA    73.11uA
0V        3.69nA     62.74nA    1.774nA
[Ramp]
| variable   typ   min   max
dV/dt_r  0.4475/0.3224n   0.6163/0.5357n   0.3454/0.2254n
dV/dt_f  0.4601/0.3614n   0.6699/0.5835n   0.3471/0.2825n
R_load = 50.0000k
[Rising Waveform]
R_fixture= 50.0000
V_fixture= 0.0
V_fixture_min= 0.0
V_fixture_max= 0.0
C_fixture= 6.0000pF
|time   V(typ)   V(min)   V(max)
0s        -25.64uV   44.95uV    -33.33uV
151.5ps   -8.421uV   -7.938uV   -23.09mV
363.6ps   -15.5mV    11.58uV    210.5mV
575.8ps   215.3mV    -1.813mV   278mV
727.3ps   289.2mV    -7.807mV   300.1mV
818.2ps   313.4mV    16.97mV    308.7mV
1.121ns   355mV      297.5mV    322.9mV
1.394ns   370.7mV    389.4mV    327.3mV
2ns       381.7mV    446.8mV    331.1mV
3.015ns   384.8mV    461.9mV    332.8mV
[Rising Waveform]
R_fixture= 50.0000
V_fixture= 0.0
V_fixture_min= 0.0
V_fixture_max= 0.0
C_fixture= 3.0000pF
|time   V(typ)   V(min)   V(max)
0s        -42.96uV   56.84uV    -50.85uV
151.5ps   -13.94uV   -19.6uV    -28.13mV
272.7ps   -15.98mV   7.706uV    190.5mV
363.6ps   -17.56mV   14.58uV    253.8mV
575.8ps   269.6mV    -3.044mV   300mV
818.2ps   343.5mV    27.93mV    318.8mV
1.061ns   364.5mV    316.3mV    326mV
1.273ns   373.8mV    403mV      328.3mV
1.849ns   382.5mV    451.1mV    331.2mV
3.015ns   385.5mV    464.9mV    333.1mV
[Falling Waveform]
R_fixture= 50.0000
V_fixture= 0.0
V_fixture_min= 0.0
V_fixture_max= 0.0
C_fixture= 6.0000pF
|time   V(typ)   V(min)   V(max)
0s        389.3mV    471.5mV    335.8mV
242.4ps   388.6mV    471.5mV    325.6mV
454.5ps   369.9mV    471.2mV    200.4mV
636.4ps   279mV      471.1mV    90.93mV
757.6ps   178.7mV    464mV      55.13mV
909.1ps   103.6mV    425.9mV    30.58mV
1.303ns   29.12mV    176mV      11.12mV
1.606ns   14.73mV    76mV       7.705mV
2.091ns   8.248mV    25.15mV    5.559mV
3.015ns   5.579mV    10.6mV     4.259mV
[Falling Waveform]
R_fixture= 50.0000
V_fixture= 0.0
V_fixture_min= 0.0
V_fixture_max= 0.0
C_fixture= 3.0000pF
|time   V(typ)   V(min)   V(max)
0s        389.3mV    471.5mV    335.7mV
212.1ps   388.4mV    471.5mV    333mV
393.9ps   382.8mV    471.1mV    235.9mV
454.5ps   362.3mV    471.1mV    164.8mV
606.1ps   277.5mV    471mV      69.07mV
818.2ps   101mV      449.9mV    23.67mV
1.03ns    40.32mV    345.1mV    11.42mV
1.273ns   17.29mV    141.7mV    7.974mV
1.515ns   10.66mV    59.9mV     6.751mV
3.015ns   5.17mV     8.554mV    4.096mV
